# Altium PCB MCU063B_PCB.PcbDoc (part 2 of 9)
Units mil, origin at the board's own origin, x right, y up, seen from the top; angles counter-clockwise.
Board outline 4165.01 x 2371.03 mil, 10 copper layers (Top Layer, Internal Plane 2, Signal Layer 3, Signal Layer 4, Internal Plane 5, Internal Plane 6, Signal Layer 7, Signal Layer 8, Internal Plane 9, Bottom), stack 59.9 mil thick; 440 components, 394 nets, 1760 pads, 1251 vias.

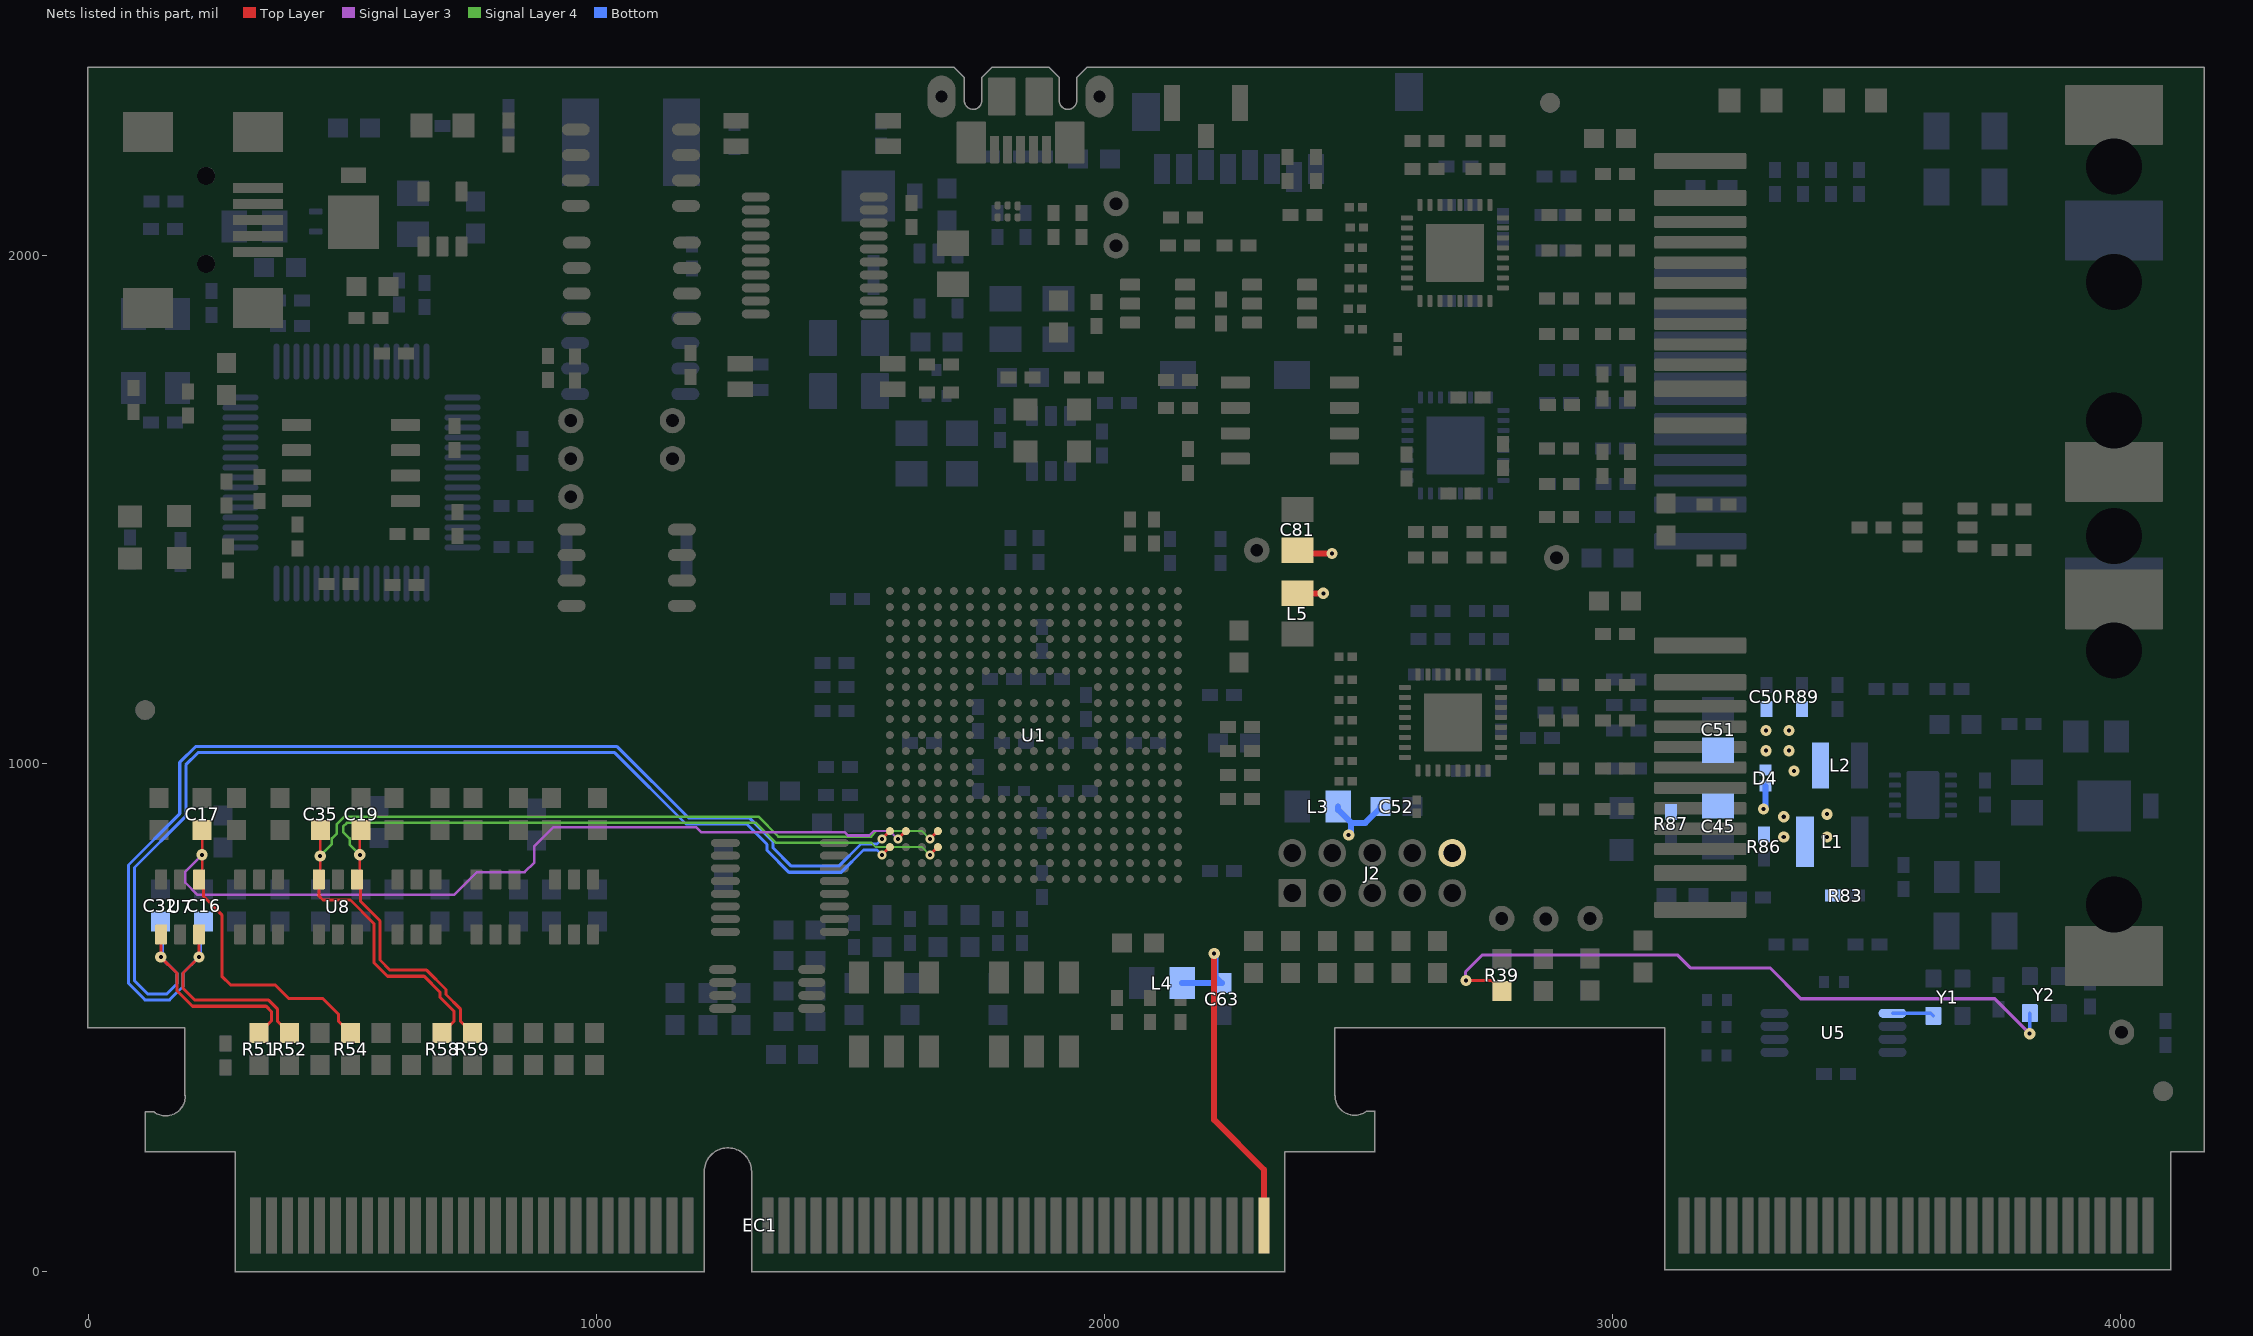
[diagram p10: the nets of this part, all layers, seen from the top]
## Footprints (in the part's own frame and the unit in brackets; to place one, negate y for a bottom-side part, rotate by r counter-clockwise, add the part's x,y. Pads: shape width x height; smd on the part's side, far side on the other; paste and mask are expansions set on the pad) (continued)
D0008B_N [mil] "SOIC, 8-Leads, Body 4.9x3.9mm, Pitch 1.27mm, IPC Medium Density"
  oval 55x23.62 smd: 1(-108.5,75) 2(-108.5,25) 3(-108.5,-25) 4(-108.5,-75) 5(108.5,-75) 6(108.5,-25) 7(108.5,25) 8(108.5,75)
  silkscreen extent -130,-98 35,98, body extent -118,-96 118,96, height 64
DBQ0016A_N [mm] "SOP, 16-Leads, Body 4.9x3.9mm, Pitch 0.635mm, IPC Medium Density"
  oval 1.45x0.4 smd: 1(-2.725,2.222) 2(-2.725,1.587) 3(-2.725,0.953) 4(-2.725,0.318) 5(-2.725,-0.318) 6(-2.725,-0.953) 7(-2.725,-1.587) 8(-2.725,-2.222) 9(2.725,-2.222) 10(2.725,-1.587) 11(2.725,-0.953) 12(2.725,-0.318) 13(2.725,0.318) 14(2.725,0.953) 15(2.725,1.587) 16(2.725,2.222)
  silkscreen extent -3.35,-2.5 1.1,2.68, body extent -3.01,-2.45 3.01,2.45, height 1.63
DBV0005A_N [mm] "SOT23, 5-Leads, Body 2.9x1.6mm, Pitch 0.95mm, Lead Span 2.8mm, IPC Medium Density"
  rrect17% 1x0.6 smd: 1(-1.375,0.95) 2(-1.375,0) 3(-1.375,-0.95) 4(1.375,-0.95) 5(1.375,0.95)
  silkscreen extent -0.25,-1.55 0.25,1.55, body extent -1.42,-1.46 1.42,1.46, height 1.09
DBV0006A_N [mm] "SOT23, 6-Leads, Body 2.9x1.6mm, Pitch 0.95mm, Lead Span 2.8mm, IPC Medium Density"
  rrect17% 1x0.6 smd: 1(-1.375,0.95) 2(-1.375,0) 3(-1.375,-0.95) 4(1.375,-0.95) 5(1.375,0) 6(1.375,0.95)
  silkscreen extent -1.68,-1.55 0.5,1.55, body extent -1.42,-1.46 1.42,1.46, height 1.12
DDC0006A_N [mm]
  rrect17% 1x0.6 smd: 1(-1.375,0.95) 2(-1.375,0) 3(-1.375,-0.95) 4(1.375,-0.95) 5(1.375,0) 6(1.375,0.95)
  silkscreen extent -1.75,-1.52 0.7,1.53, body extent -1.43,-1.48 1.43,1.49, height 0.92
DGK0008A_N [mm] "TSOP, 8-Leads, Body 3x3mm, Pitch 0.65mm, IPC Medium Density"
  oval 1.35x0.45 smd: 1(-2.225,0.975) 2(-2.225,0.325) 3(-2.225,-0.325) 4(-2.225,-0.975) 5(2.225,-0.975) 6(2.225,-0.325) 7(2.225,0.325) 8(2.225,0.975)
  silkscreen extent -2.75,-1.55 0.95,1.55, body extent -2.45,-1.5 2.45,1.5, height 0.96
DRC0010J [mm] "VSON-10"
  rrect42% 0.6x0.24 smd: 1(-1.4,1) 2(-1.4,0.5) 3(-1.4,0) 4(-1.4,-0.5) 5(-1.4,-1) 6(1.4,-1) 7(1.4,-0.5) 8(1.4,0) 9(1.4,0.5) 10(1.4,1)
  rrect12% 1.65x2.4 smd paste-1 mask-2: 11(0,0)
  Top Layer region: -0.375,-1.65 -0.375,-1.2 -0.775,-1.2 -0.794,-1.196 -0.81,-1.185 -0.821,-1.169 -0.825,-1.15 -0.825,-1.15 -0.825,1.15 -0.821,1.169 -0.81,1.185 -0.794,1.196 -0.775,1.2 -0.775,1.2 -0.375,1.2 -0.375,1.65 -0.371,1.669 -0.36,1.685 -0.344,1.696 -0.325,1.7 -0.325,1.7 -0.325,1.7 -0.175,1.7 -0.175,1.7 -0.156,1.696 -0.14,1.685 -0.129,1.669 -0.125,1.65 -0.125,1.65 -0.125,1.2 0.125,1.2 0.125,1.65 0.129,1.669 0.14,1.685 0.156,1.696 0.175,1.7 0.175,1.7 0.175,1.7 0.325,1.7 0.325,1.7 0.344,1.696 0.36,1.685 0.371,1.669 0.375,1.65 0.375,1.65 0.375,1.2 0.775,1.2 0.794,1.196 0.81,1.185 0.821,1.169 0.825,1.15 0.825,1.15 0.825,-1.15 0.821,-1.169 0.81,-1.185 0.794,-1.196 0.775,-1.2 0.775,-1.2 0.375,-1.2 0.375,-1.65 0.371,-1.669 0.36,-1.685 0.344,-1.696 0.325,-1.7 0.325,-1.7 0.175,-1.7 0.156,-1.696 0.14,-1.685 0.129,-1.669 0.125,-1.65 0.125,-1.65 0.125,-1.2 -0.125,-1.2 -0.125,-1.65 -0.129,-1.669 -0.14,-1.685 -0.156,-1.696 -0.175,-1.7 -0.175,-1.7 -0.325,-1.7 -0.344,-1.696 -0.36,-1.685 -0.371,-1.669 -0.375,-1.65
  body extent -1.5,-1.5 1.5,1.5, height 1
DRL0005A [mm] "SOTFL, 5-Flat Leads, Body 1.2x1.6x0.6mm, Pitch 0.5mm, TI recommended"
  rrect33% 0.67x0.3 smd: 1(-0.74,0.5) 2(-0.74,0) 3(-0.74,-0.5) 4(0.74,-0.5) 5(0.74,0.5)
  silkscreen extent -0.9,-0.95 0.5,0.95, body extent -0.85,-0.85 0.85,0.85, height 0.62
DRY0006A [mm] "USON-6"
  rrect67% 0.45x0.3 smd paste-0.05 mask-0.05: 1(-0.275,0.5)
  rrect67% 0.4x0.3 smd paste-0.05 mask-0.05: 2(-0.3,0) 3(-0.3,-0.5) 4(0.3,-0.5) 5(0.3,0) 6(0.3,0.5)
  body extent -0.5,-0.72 0.5,0.73, height 0.58
ECS_ECS-2520S [mm] "SMD, 4-Leads, Body 2x2.5mm"
  rrect12% 0.8x0.9 smd: 1(-0.725,0.925) 2(-0.725,-0.925) 3(0.725,-0.925) 4(0.725,0.925)
  silkscreen extent -1.7,0.9 -1.5,1.1, body extent -1.05,-1.3 1.05,1.3, height 1
ECS_ECX-53B [mm] "SMD, 4-Leads, Body 5x3.2mm"
  rect 1.25x1.6 smd: 1(-1.1,1.85) 2(-1.1,-1.85) 3(1.1,-1.85) 4(1.1,1.85)
  silkscreen extent -2.05,-2.7 1.83,2.73, body extent -1.7,-2.6 1.7,2.6, height 0.86
EtherCAT_label [mil] "ETHERCAT_LABEL"
FCC_disclaimer [mil]
Fiducial10-20 [mm]
  round 1 smd mask+0.5: 1(0,0)
  Top Layer keep-out circle w1.178: c0,0 r0.5
FP-TMM-105-01-T-D_HDR10-MFG [mm]
  rrect7% 1.39x1.39 hole 0.89 paste-1000 mask+0: 1(-4,-1)
  round 1.39 hole 0.89 paste-1000 mask+0: 2(-4,1) 3(-2,-1) 4(-2,1) 5(0,-1) 6(0,1) 7(2,-1) 8(2,1) 9(4,-1) 10(4,1)
  body extent -5.1,-2.13 5.1,2.13, height 0.25
Label_650x200 [mil] "Thermal Transfer Label"
  round 1 on Mech13: 0(0,0)
  silkscreen extent -325,-100 325,100, body extent -325,-100 325,100, height 1
LQFP64_N [mm] "Thin QFP, 64-Leads, Body 10x10mm, Pitch 0.5mm, IPC Medium Density"
  oval 1.8x0.3 smd: 1(-5.55,3.75) 2(-5.55,3.25) 3(-5.55,2.75) 4(-5.55,2.25) 5(-5.55,1.75) 6(-5.55,1.25) 7(-5.55,0.75) 8(-5.55,0.25) 9(-5.55,-0.25) 10(-5.55,-0.75) 11(-5.55,-1.25) 12(-5.55,-1.75) 13(-5.55,-2.25) 14(-5.55,-2.75) 15(-5.55,-3.25) 16(-5.55,-3.75) 33(5.55,-3.75) 34(5.55,-3.25) 35(5.55,-2.75) 36(5.55,-2.25) 37(5.55,-1.75) 38(5.55,-1.25) 39(5.55,-0.75) 40(5.55,-0.25) 41(5.55,0.25) 42(5.55,0.75) 43(5.55,1.25) 44(5.55,1.75) 45(5.55,2.25) 46(5.55,2.75) 47(5.55,3.25) 48(5.55,3.75)
  oval 0.3x1.8 smd: 17(-3.75,-5.55) 18(-3.25,-5.55) 19(-2.75,-5.55) 20(-2.25,-5.55) 21(-1.75,-5.55) 22(-1.25,-5.55) 23(-0.75,-5.55) 24(-0.25,-5.55) 25(0.25,-5.55) 26(0.75,-5.55) 27(1.25,-5.55) 28(1.75,-5.55) 29(2.25,-5.55) 30(2.75,-5.55) 31(3.25,-5.55) 32(3.75,-5.55) 49(3.75,5.55) 50(3.25,5.55) 51(2.75,5.55) 52(2.25,5.55) 53(1.75,5.55) 54(1.25,5.55) 55(0.75,5.55) 56(0.25,5.55) 57(-0.25,5.55) 58(-0.75,5.55) 59(-1.25,5.55) 60(-1.75,5.55) 61(-2.25,5.55) 62(-2.75,5.55) 63(-3.25,5.55) 64(-3.75,5.55)
  silkscreen extent -5.67,-4.25 4.25,4.57, body extent -5,-5 5,5, height 1.6
Molex_1051640001 [mm] "Receptacle, USB 2.0, Micro B, 5 Pos, 0.65mm Pitch, R/A, SMT"
  rrect22% 0.45x1.38 smd: 1(1.3,4.11) 2(0.65,4.11) 3(0,4.11) 4(-0.65,4.11) 5(-1.3,4.11)
  rrect7% 1.475x2.1 smd: 6(-2.462,3.75) 11(2.462,3.75)
  rrect100% 1.4x2.1 hole 0.6 slot 1.3 at 90 deg: 7(-3.95,1.45) 10(3.95,1.45)
  rrect7% 1.375x1.9 smd: 8(-0.937,1.45) 9(0.937,1.45)
  silkscreen extent 1.2,5.1 1.4,5.4, body extent -4.1,-0.7 4.1,4.47, height 2.45
PFL3215 [mm] "Coilcraft"
  rect 0.89x2.54 smd: 1(-1.37,0) 2(1.37,0)
  body extent -1.22,-1.14 1.22,1.14, height 1.5
POWERMITE [mil] "On Semi recommended land pattern, 457-04.pdf Rev 04E dated 2008-11-26"
  rect 105x100 smd: 1(-46,0)
  rect 30x50 smd: 2(46,0)
  silkscreen extent -124,-63 61,63, body extent -94,-40 59,40, height 45
PW0008A_N [mm] "TSOP, 8-Leads, Body 3x4.4mm, Pitch 0.65mm, IPC Medium Density"
  oval 1.4x0.45 smd: 1(-2.95,0.975) 2(-2.95,0.325) 3(-2.95,-0.325) 4(-2.95,-0.975) 5(2.95,-0.975) 6(2.95,-0.325) 7(2.95,0.325) 8(2.95,0.975)
  silkscreen extent -3.4,-1.55 1.85,1.55, body extent -3.21,-1.5 3.21,1.5, height 1.2
PW0020A_N [mm] "TSOP, 20-Leads, Body 6.5x4.4mm, Pitch 0.65mm, IPC Medium Density"
  oval 1.4x0.45 smd: 1(-2.95,2.925) 2(-2.95,2.275) 3(-2.95,1.625) 4(-2.95,0.975) 5(-2.95,0.325) 6(-2.95,-0.325) 7(-2.95,-0.975) 8(-2.95,-1.625) 9(-2.95,-2.275) 10(-2.95,-2.925) 11(2.95,-2.925) 12(2.95,-2.275) 13(2.95,-1.625) 14(2.95,-0.975) 15(2.95,-0.325) 16(2.95,0.325) 17(2.95,0.975) 18(2.95,1.625) 19(2.95,2.275) 20(2.95,2.925)
  Top Overlay keep-out lines w0.2: -1.85,-3.3 1.85,-3.3
  silkscreen extent -3.5,-3.3 1.85,3.4, body extent -3.21,-3.25 3.21,3.25, height 1
RHB0032B#1 [mm] "QFN, 32-Leads, Body 5x5mm, Pitch 0.5mm, Thermal Pad 2.9x2.9mm"
  rrect40% 0.6x0.25 smd: 1(-2.4,1.75) 2(-2.4,1.25) 3(-2.4,0.75) 4(-2.4,0.25) 5(-2.4,-0.25) 6(-2.4,-0.75) 7(-2.4,-1.25) 8(-2.4,-1.75) 17(2.4,-1.75) 18(2.4,-1.25) 19(2.4,-0.75) 20(2.4,-0.25) 21(2.4,0.25) 22(2.4,0.75) 23(2.4,1.25) 24(2.4,1.75)
  rrect40% 0.25x0.6 smd: 9(-1.75,-2.4) 10(-1.25,-2.4) 11(-0.75,-2.4) 12(-0.25,-2.4) 13(0.25,-2.4) 14(0.75,-2.4) 15(1.25,-2.4) 16(1.75,-2.4) 25(1.75,2.4) 26(1.25,2.4) 27(0.75,2.4) 28(0.25,2.4) 29(-0.25,2.4) 30(-0.75,2.4) 31(-1.25,2.4) 32(-1.75,2.4)
  rrect8% 1.27x1.27 on Bottom Paste: 33(-0.735,-0.735) 33(-0.735,0.735) 33(0.735,-0.735) 33(0.735,0.735)
  rrect3% 2.9x2.9 smd paste-1.725: 33(0,0)
  silkscreen extent -2.72,-2.73 2.72,2.73, body extent -2.57,-2.57 2.58,2.58, height 1.01
RHB0032B#2 [mm] "QFN, 32-Leads, Body 5x5mm, Pitch 0.5mm, Thermal Pad 2.9x2.9mm"
  rrect40% 0.6x0.25 smd: 1(-2.4,1.75) 2(-2.4,1.25) 3(-2.4,0.75) 4(-2.4,0.25) 5(-2.4,-0.25) 6(-2.4,-0.75) 7(-2.4,-1.25) 8(-2.4,-1.75) 17(2.4,-1.75) 18(2.4,-1.25) 19(2.4,-0.75) 20(2.4,-0.25) 21(2.4,0.25) 22(2.4,0.75) 23(2.4,1.25) 24(2.4,1.75)
  rrect40% 0.25x0.6 smd: 9(-1.75,-2.4) 10(-1.25,-2.4) 11(-0.75,-2.4) 12(-0.25,-2.4) 13(0.25,-2.4) 14(0.75,-2.4) 15(1.25,-2.4) 16(1.75,-2.4) 25(1.75,2.4) 26(1.25,2.4) 27(0.75,2.4) 28(0.25,2.4) 29(-0.25,2.4) 30(-0.75,2.4) 31(-1.25,2.4) 32(-1.75,2.4)
  rrect8% 1.27x1.27 on Top Paste: 33(-0.735,-0.735) 33(-0.735,0.735) 33(0.735,-0.735) 33(0.735,0.735)
  rrect3% 2.9x2.9 smd paste-1.725: 33(0,0)
  silkscreen extent -2.72,-2.73 2.72,2.73, body extent -2.57,-2.57 2.58,2.58, height 1.01
SOD-882L [mm] "Central Semiconductor"
  rect 0.55x0.6 smd: 1(-0.4,0)
  rect 0.55x0.6 smd paste-0.05: 2(0.4,0)
  silkscreen extent -1.1,-0.35 -0.87,0.35, body extent -0.52,-0.32 0.52,0.32, height 0.41
SOIC-8 [mm] "duplicate of SO-8.  SOIC, 8-Leads, Body 5.0x4.0mm (max), Pitch 1.27mm, IPC Medium Density"
  rrect17% 1.45x0.6 smd: 1(-2.725,1.905) 2(-2.725,0.635) 3(-2.725,-0.635) 4(-2.725,-1.905) 5(2.725,-1.905) 6(2.725,-0.635) 7(2.725,0.635) 8(2.725,1.905)
  silkscreen extent -3.5,-2.5 0.9,2.5, body extent -3,-2.45 3,2.45, height 1.63
SOT-416 [mm] "NXP recommended footprint."
  rect 0.6x0.5 smd: 1(-0.65,0.5) 2(-0.65,-0.5) 3(0.65,0)
  silkscreen extent -0.13,-0.9 0.5,0.9, body extent -0.8,-0.9 0.8,0.9, height 0.82
SW_218-2LP [mm] "SMD, 4-Leads, Body 3.71x5.8mm, Pitch 1.27mm"
  rect 1.27x0.76 smd: 1(-3.81,0.635) 2(-3.81,-0.635) 3(3.81,-0.635) 4(3.81,0.635)
  silkscreen extent -2.9,-1.86 2.9,2.09, body extent -4.22,-1.86 4.22,1.85, height 2.62
SW_B3U-1100P [mm] "SMD, 3-Leads, Body 3x2.5mm"
  rect 0.8x1.8 smd: 1(-1.7,0) 2(1.7,0)
  rect 0.8x1.2 smd: 3(0,1.65)
  silkscreen extent -2.83,-1.25 1.5,1.25, body extent -2,-1.25 2,1.9, height 1.6
SW_CAS-D20TA [mm] "SMD, 6-Leads, Body 5.4x3.9mm, Pitch 1.75mm"
  rect 1.6x1 smd: 1(-1.85,1.75) 2(-1.85,0) 3(-1.85,-1.75) 4(1.85,1.75) 5(1.85,0) 6(1.85,-1.75)
  silkscreen extent -1.95,-2.7 1.95,2.9, body extent -2.1,-2.7 2.1,2.7, height 2.5
TI_Stacked_Overlay_Small [mil]
  silkscreen extent -418,-98 418,98
TP_50MIL-25MILHOLE [mil]
  round 50 hole 25: 1(0,0)
WE-MAIA_2510 [mm] "WURTH"
  rect 0.85x2.3 smd: 1(-0.975,0) 2(0.975,0)
  silkscreen extent -0.3,-1.25 0.3,1.25, body extent -1.35,-1.1 1.35,1.1, height 1
WEEE_Minimum [mil] "WEEElie bin"
  silkscreen extent -95,-172 99,104
WL-SMCW_Blue_0805 [mm] "SMD, 2-Leads, Body 2x1.25mm"
  rect 1.1x1.2 smd: 1(-1.05,0) 2(1.05,0)
  silkscreen extent -2.4,-1.1 1.5,1.1, body extent -1,-0.62 1,0.63, height 0.7
WL-SMCW_Green_0805 [mm] "SMD, 2-Leads, Body 2x1.25mm"
  rect 1.1x1.2 smd: 1(-1.05,0) 2(1.05,0)
  silkscreen extent -2.4,-1.1 1.5,1.1, body extent -1,-0.62 1,0.63, height 0.7
WL-SMCW_RED_0805 [mm] "SMD, 2-Leads, Body 1.6x0.8mm"
  rect 1.1x1.2 smd: 1(-1.05,0) 2(1.05,0)
  silkscreen extent -2.4,-1.1 1.5,1.1, body extent -1,-0.62 1,0.63, height 0.7
Wurth_7498010210A [mm] "Connector, RJ45, 1x1, Gold, R/A, SMT"
  rrect12% 4.6x0.81 smd: 1(-20.69,6.61) 2(-20.69,4.77) 11(-20.69,-4.77) 12(-20.69,-6.61)
  rrect16% 4.6x0.61 smd: 3(-20.69,3.57) 4(-20.69,2.55) 5(-20.69,1.53) 6(-20.69,0.51) 7(-20.69,-0.51) 8(-20.69,-1.53) 9(-20.69,-2.55) 10(-20.69,-3.57)
  rrect3% 4.9x3 smd: 13(0,8.92) 14(0,-8.92)
  round 2.5 hole 2.8 unplated mask+0.102: ALIGN1(0,6.35) ALIGN2(0,-6.35)
  body extent -21.42,-9.65 5.43,9.65, height 15.22
Wurth_65100516121 [mm] "Connector, Receptacle, USB Mini B 2.0, 5 Position, SMT"
  rect 0.5x2.5 smd: 1(-1.6,8.5) 2(-0.8,8.5) 3(0,8.5) 4(0.8,8.5) 5(1.6,8.5)
  rect 2x2.5 smd: 6(-4.4,8.5) 7(4.4,8.5) 8(-4.4,3) 9(4.4,3)
  round 0.9 hole 0.9 unplated mask+0: ALIGN1(-2.2,5.9) ALIGN2(2.2,5.9)
  silkscreen extent -3.85,0.15 3.85,9.6, body extent -4.8,0 4.8,9.25, height 3.91
ZWT0337A [mm] "BGA, 337-Leads, Body 16x16mmx1.4mm, Pitch 0.80mm"
  round 0.4 smd: A1(-7.2,7.2) A2(-6.4,7.2) A3(-5.6,7.2) A4(-4.8,7.2) A5(-4,7.2) A6(-3.2,7.2) A7(-2.4,7.2) A8(-1.6,7.2) A9(-0.8,7.2) A10(0,7.2) A11(0.8,7.2) A12(1.6,7.2) A13(2.4,7.2) A14(3.2,7.2) A15(4,7.2) A16(4.8,7.2) A17(5.6,7.2) A18(6.4,7.2) A19(7.2,7.2) B1(-7.2,6.4) B2(-6.4,6.4) B3(-5.6,6.4) B4(-4.8,6.4) B5(-4,6.4) B6(-3.2,6.4) B7(-2.4,6.4) B8(-1.6,6.4) B9(-0.8,6.4) B10(0,6.4) B11(0.8,6.4) B12(1.6,6.4) B13(2.4,6.4) B14(3.2,6.4) B15(4,6.4) B16(4.8,6.4) B17(5.6,6.4) B18(6.4,6.4) B19(7.2,6.4) C1(-7.2,5.6) C2(-6.4,5.6) C3(-5.6,5.6) C4(-4.8,5.6) C5(-4,5.6) C6(-3.2,5.6) C7(-2.4,5.6) C8(-1.6,5.6) C9(-0.8,5.6) C10(0,5.6) C11(0.8,5.6) C12(1.6,5.6) C13(2.4,5.6) C14(3.2,5.6) C15(4,5.6) C16(4.8,5.6) C17(5.6,5.6) C18(6.4,5.6) C19(7.2,5.6) D1(-7.2,4.8) D2(-6.4,4.8) D3(-5.6,4.8) D4(-4.8,4.8) D5(-4,4.8) D6(-3.2,4.8) D7(-2.4,4.8) D8(-1.6,4.8) D9(-0.8,4.8) D10(0,4.8) D11(0.8,4.8) D12(1.6,4.8) D13(2.4,4.8) D14(3.2,4.8) D15(4,4.8) D16(4.8,4.8) D17(5.6,4.8) D18(6.4,4.8) D19(7.2,4.8) E1(-7.2,4) E2(-6.4,4) E3(-5.6,4) E4(-4.8,4) E5(-4,4) E6(-3.2,4) E7(-2.4,4) E8(-1.6,4) E9(-0.8,4) E10(0,4) E11(0.8,4) E12(1.6,4) E13(2.4,4) E14(3.2,4) E15(4,4) E16(4.8,4) E17(5.6,4) E18(6.4,4) E19(7.2,4) F1(-7.2,3.2) F2(-6.4,3.2) F3(-5.6,3.2) F4(-4.8,3.2) F5(-4,3.2) F6(-3.2,3.2) F7(-2.4,3.2) F8(-1.6,3.2) F9(-0.8,3.2) F10(0,3.2) F11(0.8,3.2) F12(1.6,3.2) F13(2.4,3.2) F14(3.2,3.2) F15(4,3.2) F16(4.8,3.2) F17(5.6,3.2) F18(6.4,3.2) F19(7.2,3.2) G1(-7.2,2.4) G2(-6.4,2.4) G3(-5.6,2.4) G4(-4.8,2.4) G5(-4,2.4) G6(-3.2,2.4) G14(3.2,2.4) G15(4,2.4) G16(4.8,2.4) G17(5.6,2.4) G18(6.4,2.4) G19(7.2,2.4) H1(-7.2,1.6) H2(-6.4,1.6) H3(-5.6,1.6) H4(-4.8,1.6) H5(-4,1.6) H6(-3.2,1.6) H8(-1.6,1.6) H9(-0.8,1.6) H10(0,1.6) H11(0.8,1.6) H12(1.6,1.6) H14(3.2,1.6) H15(4,1.6) H16(4.8,1.6) H17(5.6,1.6) H18(6.4,1.6) H19(7.2,1.6) J1(-7.2,0.8) J2(-6.4,0.8) J3(-5.6,0.8) J4(-4.8,0.8) J5(-4,0.8) J6(-3.2,0.8) J8(-1.6,0.8) J9(-0.8,0.8) J10(0,0.8) J11(0.8,0.8) J12(1.6,0.8) J14(3.2,0.8) J15(4,0.8) J16(4.8,0.8) J17(5.6,0.8) J18(6.4,0.8) J19(7.2,0.8) K1(-7.2,0) K2(-6.4,0) K3(-5.6,0) K4(-4.8,0) K5(-4,0) K6(-3.2,0) K8(-1.6,0) K9(-0.8,0) K10(0,0) K11(0.8,0) K12(1.6,0) K14(3.2,0) K15(4,0) K16(4.8,0) K17(5.6,0) K18(6.4,0) K19(7.2,0) L1(-7.2,-0.8) L2(-6.4,-0.8) L3(-5.6,-0.8) L4(-4.8,-0.8) L5(-4,-0.8) L6(-3.2,-0.8) L8(-1.6,-0.8) L9(-0.8,-0.8) L10(0,-0.8) L11(0.8,-0.8) L12(1.6,-0.8) L14(3.2,-0.8) L15(4,-0.8) L16(4.8,-0.8) L17(5.6,-0.8) L18(6.4,-0.8) L19(7.2,-0.8) M1(-7.2,-1.6) M2(-6.4,-1.6) M3(-5.6,-1.6) M4(-4.8,-1.6) M5(-4,-1.6) M6(-3.2,-1.6) M8(-1.6,-1.6) M9(-0.8,-1.6) M10(0,-1.6) M11(0.8,-1.6) M12(1.6,-1.6) M14(3.2,-1.6) M15(4,-1.6) M16(4.8,-1.6) M17(5.6,-1.6) M18(6.4,-1.6) M19(7.2,-1.6) N1(-7.2,-2.4) N2(-6.4,-2.4) N3(-5.6,-2.4) N4(-4.8,-2.4) N5(-4,-2.4) N6(-3.2,-2.4) N14(3.2,-2.4) N15(4,-2.4) N16(4.8,-2.4) N17(5.6,-2.4) N18(6.4,-2.4) N19(7.2,-2.4) P1(-7.2,-3.2) P2(-6.4,-3.2) P3(-5.6,-3.2) P4(-4.8,-3.2) P5(-4,-3.2) P6(-3.2,-3.2) P7(-2.4,-3.2) P8(-1.6,-3.2) P9(-0.8,-3.2) P10(0,-3.2) P11(0.8,-3.2) P12(1.6,-3.2) P13(2.4,-3.2) P14(3.2,-3.2) P15(4,-3.2) P16(4.8,-3.2) P17(5.6,-3.2) P18(6.4,-3.2) P19(7.2,-3.2) R1(-7.2,-4) R2(-6.4,-4) R3(-5.6,-4) R4(-4.8,-4) R5(-4,-4) R6(-3.2,-4) R7(-2.4,-4) R8(-1.6,-4) R9(-0.8,-4) R10(0,-4) R11(0.8,-4) R12(1.6,-4) R13(2.4,-4) R14(3.2,-4) R15(4,-4) R16(4.8,-4) R17(5.6,-4) R18(6.4,-4) R19(7.2,-4) T1(-7.2,-4.8) T2(-6.4,-4.8) T3(-5.6,-4.8) T4(-4.8,-4.8) T5(-4,-4.8) T6(-3.2,-4.8) T7(-2.4,-4.8) T8(-1.6,-4.8) T9(-0.8,-4.8) T10(0,-4.8) T11(0.8,-4.8) T12(1.6,-4.8) T13(2.4,-4.8) T14(3.2,-4.8) T15(4,-4.8) T16(4.8,-4.8) T17(5.6,-4.8) T18(6.4,-4.8) T19(7.2,-4.8) U1(-7.2,-5.6) U2(-6.4,-5.6) U3(-5.6,-5.6) U4(-4.8,-5.6) U5(-4,-5.6) U6(-3.2,-5.6) U7(-2.4,-5.6) U8(-1.6,-5.6) U9(-0.8,-5.6) U10(0,-5.6) U11(0.8,-5.6) U12(1.6,-5.6) U13(2.4,-5.6) U14(3.2,-5.6) U15(4,-5.6) U16(4.8,-5.6) U17(5.6,-5.6) U18(6.4,-5.6) U19(7.2,-5.6) V1(-7.2,-6.4) V2(-6.4,-6.4) V3(-5.6,-6.4) V4(-4.8,-6.4) V5(-4,-6.4) V6(-3.2,-6.4) V7(-2.4,-6.4) V8(-1.6,-6.4) V9(-0.8,-6.4) V10(0,-6.4) V11(0.8,-6.4) V12(1.6,-6.4) V13(2.4,-6.4) V14(3.2,-6.4) V15(4,-6.4) V16(4.8,-6.4) V17(5.6,-6.4) V18(6.4,-6.4) V19(7.2,-6.4) W1(-7.2,-7.2) W2(-6.4,-7.2) W3(-5.6,-7.2) W4(-4.8,-7.2) W5(-4,-7.2) W6(-3.2,-7.2) W7(-2.4,-7.2) W8(-1.6,-7.2) W9(-0.8,-7.2) W10(0,-7.2) W11(0.8,-7.2) W12(1.6,-7.2) W13(2.4,-7.2) W14(3.2,-7.2) W15(4,-7.2) W16(4.8,-7.2) W17(5.6,-7.2) W18(6.4,-7.2) W19(7.2,-7.2)
  silkscreen extent -8.15,-8.15 8.15,8.15, body extent -8,-8 8,8, height 1.34

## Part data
C1 C1:A C2 C4 C6 C6:A C7 C7:A C8:A C9:A C10:A C11:A C12:A C14:A C16:A C20:A C21:A C22:A C23:A C24:A C25:A C26:A C27:A C28:A C115 C134: library part CMP-0006343-2, "CAP, CERM, 0.1 uF, 10 V, +/- 10%, X7R, 0402", Cap_Case=0402, Manufacturer="Samsung Electro-Mechanics", TempCo=X7R, Tolerance_%=10%, Value1=Unknown, Value2=10V, ValueDisplayed=0.1uF
C2:A C3:A C5:A C13:A C15:A C83: library part CMP-0006950-5, "CAP, CERM, 4.7 uF, 6.3 V, +/- 10%, X5R, 0603", Cap_Case=0603, Manufacturer=Kemet, Supplier Part Number 1=399-3482-1-ND, TempCo=X5R, Tolerance_%=10%, Value1="0.006 ohm", Value2=6.3V, ValueDisplayed=4.7uF
C3 C5: library part CMP-0006236-2, "CAP, CERM, 0.01 uF, 50 V, +/- 5%, X7R, 0402", Cap_Case=0402, Manufacturer=Kemet, Supplier Part Number 1=399-7758-1-ND, TempCo=X7R, Tolerance_%=5%, Value1=Unknown, Value2=50V, ValueDisplayed=0.01uF
C4:A: library part CMP-0006203-2, "CAP, CERM, 0.01 uF, 10 V, +/- 10%, X7R, 0402", Cap_Case=0402, Manufacturer=AVX, Supplier Part Number 1=478-7890-1-ND, TempCo=X7R, Tolerance_%=10%, Value1=Unknown, Value2=10V, ValueDisplayed=0.01uF
C8 C9 C10 C13 C44: library part CMP-0006862-5, "CAP, CERM, 0.1 uF, 10 V, +/- 10%, X7R, 0603", Cap_Case=0603, Manufacturer=Kemet, Supplier Part Number 1=399-1095-1-ND, TempCo=X7R, Tolerance_%=10%, Value1=Unknown, Value2=10V, ValueDisplayed=0.1uF
C11 C12 C15: library part CMP-0006871-4, "CAP, CERM, 1 uF, 6.3 V, +80/-20%, Y5V, 0603", Cap_Case=0603, Manufacturer=Kemet, Supplier Part Number 1=399-3217-1-ND, TempCo=Y5V, Tolerance_%=80%, Value1=Unknown, Value2=6.3V, ValueDisplayed=1uF
C14: library part CMP-0006907-5, "CAP, CERM, 2.2 uF, 6.3 V, +/- 10%, X5R, 0603", Cap_Case=0603, Manufacturer=Kemet, Supplier Part Number 1=399-3362-1-ND, TempCo=X5R, Tolerance_%=10%, Value1=Unknown, Value2=6.3V, ValueDisplayed=2.2uF
C16 C17 C18 C19 C20 C21 C22 C23 C24 C25 C26 C27 C32 C33 C34 C35 C36 C37 C38 C39 C40 C41 C42 C43: library part CMP-0006920-4, "CAP, CERM, 330 pF, 50 V, +/- 5%, C0G/NP0, 0603", Cap_Case=0603, Manufacturer=Kemet, Supplier Part Number 1=399-1068-1-ND, TempCo=C0G/NP0, Tolerance_%=5%, Value1=Unknown, Value2=50V, ValueDisplayed=330pF
C17:A C86: library part CMP-0006319-2, "CAP, CERM, 3300 pF, 50 V, +/- 10%, X7R, AEC-Q200 Grade 1, 0402", Cap_Case=0402, Manufacturer=TDK, Supplier Part Number 1=445-6891-1-ND, TempCo=X7R, Tolerance_%=10%, Value1="0.785178 ohm", Value2=50V, ValueDisplayed=3300pF
C18:A C19:A: library part CMP-0750098-1, "CAP, CERM, 27 pF, 50 V,+/- 5%, C0G/NP0, 0402", Cap_Case=0402, Manufacturer=Kemet, TempCo=C0G/NP0, Tolerance_%=5%, Value2=50V, ValueDisplayed=27pF
C28 C29 C30 C31: library part CMP-0007324-5, "CAP, CERM, 22 uF, 10 V, +/- 20%, X5R, 0603", Cap_Case=0603, Manufacturer=MuRata, Supplier Part Number 1=490-10476-1-ND, TempCo=X5R, Tolerance_%=20%, Value1=Unknown, Value2=10V, ValueDisplayed=22uF
C29:A: library part CMP-0082066-1, "CAP, CERM, 10 pF, 3000 V,+/- 5%, C0G/NP0, AEC-Q200 Grade 1, 1812", Cap_Case=1812, Manufacturer=Kemet, Supplier Part Number 1=399-7113-1-ND, TempCo=C0G/NP0, Tolerance_%=5%, Value2=3000V, ValueDisplayed=10pF
C45 C47 C51: library part CMP-0008294-2, "CAP, CERM, 22 uF, 16 V, +/- 20%, X5R, 0805", Cap_Case=0805, Manufacturer=MuRata, Supplier Part Number 1=490-10747-1-ND, TempCo=X5R, Tolerance_%=20%, Value1=Unknown, Value2=16V, ValueDisplayed=22uF
C46 C48 C49 C54 C55 C56 C57 C58 C59 C60 C61 C62 C65 C66 C67 C68 C69 C70 C71 C72 C73 C74 C75 C76 C77 C78 C79 C80: library part CMP-0006201-2, "CAP, CERM, 0.1 uF, 16 V, +/- 10%, X7R, 0402", Cap_Case=0402, Manufacturer=AVX, Supplier Part Number 1=478-7888-1-ND, TempCo=X7R, Tolerance_%=10%, Value1=Unknown, Value2=16V, ValueDisplayed=0.1uF
C50: library part CMP-0006213-2, "CAP, CERM, 33 pF, 25 V, +/- 5%, C0G/NP0, 0402", Cap_Case=0402, Manufacturer="Wurth Elektronik", Supplier Part Number 1=710-885012005043, TempCo=C0G/NP0, Tolerance_%=5%, Value1=Unknown, Value2=25V, ValueDisplayed=33pF
C52 C53 C63 C64: library part CMP-0006906-5, "CAP, CERM, 2.2 uF, 10 V, +/- 10%, X5R, 0603", Cap_Case=0603, Manufacturer=Kemet, Supplier Part Number 1=399-4911-1-ND, TempCo=X5R, Tolerance_%=10%, Value1=Unknown, Value2=10V, ValueDisplayed=2.2uF
C81: library part CMP-0007732-2, "CAP, CERM, 10 uF, 10 V, +/- 10%, X5R, 0805", Cap_Case=0805, Manufacturer=Kemet, Supplier Part Number 1=399-4925-1-ND, TempCo=X5R, Tolerance_%=10%, Value1="0.003 ohm", Value2=10V, ValueDisplayed=10uF
C82: library part CMP-0007318-5, "CAP, CERM, 10 uF, 10 V, +/- 20%, X5R, 0603", Cap_Case=0603, Manufacturer=MuRata, TempCo=X5R, Tolerance_%=20%, Value1=Unknown, Value2=10V, ValueDisplayed=10uF
C84: library part CMP-0011440-2, "CAP, TA, 0.1 uF, 35 V, +/- 10%, 20 ohm, SMD", Cap_Case=A, Manufacturer=Vishay-Sprague, Supplier Part Number 1=718-1109-1-ND, Tolerance_%=10%, Value1="20 ohm", Value2=35V, ValueDisplayed=0.1uF
C85: library part CMP-0081926-1, "CAP, TA, 68 µF, 10 V, +/- 20%, 1.5 ohm, SMD", Cap_Case=3216-18, Manufacturer=AVX, Supplier Part Number 1=478-4925-1-ND, Tolerance_%=20%, Value1="1.5 ohm", Value2=10V, ValueDisplayed=68µF
C87 C94 C104 C111 C122 C129: library part CMP-0006340-2, "CAP, CERM, 10 uF, 6.3 V, +/- 20%, X5R, 0402", Cap_Case=0402, Manufacturer="Samsung Electro-Mechanics", TempCo=X5R, Tolerance_%=20%, Value1=Unknown, Value2=6.3V, ValueDisplayed=10uF
C88 C93 C96 C97 C99 C102 C105 C110 C113 C114 C117 C120 C123 C128 C131 C132 C135 C138: library part CMP-0006347-2, "CAP, CERM, 1 uF, 16 V, +/- 10%, X5R, 0402", Cap_Case=0402, Manufacturer="Taiyo Yuden", Supplier Part Number 1=587-3709-2-ND, TempCo=X5R, Tolerance_%=10%, Value1=Unknown, Value2=16V, ValueDisplayed=1uF
C89 C92 C95 C98 C100 C101 C106 C109 C112 C116 C118 C119 C124 C127 C130 C133 C136 C137: library part CMP-0064930-2, "CAP, CERM, 0.1 uF, 10 V,+/- 10%, X5R, 0402", Cap_Case=0402, Manufacturer="Taiyo Yuden", Supplier Part Number 1=587-1227-1-ND, TempCo=X5R, Tolerance_%=10%, Value1=Unknown, Value2=10V, ValueDisplayed=0.1uF
C90 C91 C107 C108 C125 C126: library part CMP-0006227-2, "CAP, CERM, 0.01 uF, 16 V, +/- 10%, X7R, 0402", Cap_Case=0402, Manufacturer="Wurth Elektronik", Supplier Part Number 1=710-885012205031, TempCo=X7R, Tolerance_%=10%, Value1=Unknown, Value2=16V, ValueDisplayed=0.01uF
C103 C121 C139: library part CMP-0008501-2, "CAP, CERM, 4700 pF, 100 V, +/- 10%, X7R, 1206", Cap_Case=1206, Manufacturer=AVX, Supplier Part Number 1=478-1521-1-ND, TempCo=X7R, Tolerance_%=10%, Value1="0.178 ohm", Value2=100V, ValueDisplayed=4700pF
D1 D2 D7: library part CMP-0002951-3, "LED, Red, SMD", Color=Red, Manufacturer="Wurth Elektronik", Power_TotalModule=72mW, Value1=0.072W, Value2=1.9V
D1:A D3 D6: library part CMP-0028747-2, "Diode, Schottky, 10 V, 1 A, AEC-Q101, POWERMITE", Manufacturer="ON Semiconductor", Value1=1A, Value2=0.53V
D2:A D5 D8: library part CMP-0002960-2, "LED, Bright Green, SMD", Color="Bright Green", Manufacturer="Wurth Elektronik", Power_TotalModule=72mW, Supplier Part Number 1=732-4986-1-ND, Value1=0.072W, Value2=2V
D3:A D4:A: library part CMP-0002959-3, "LED, Blue, SMD", Color=Blue, Manufacturer="Wurth Elektronik", Power_TotalModule=105mW, Value1=0.105W, Value2=3.2V
D4: library part CMP-0028751-2, "Diode, Schottky, 20 V, 0.5 A, 1.0x0.35x0.6mm", Manufacturer="Central Semiconductor", Value1=0.5A, Value2=0.5V
EC1: library part CMP-0003813-2, "C2000 controlCARD-120HSEC Edge Connector for Samtec HSEC8-160-01-L-DV-A-BL", Manufacturer=Any
EC2: library part CMP-0081961-1, "C2000 controlCARD-180HSEC (60-pin addon) Edge connector for Samtec HSEC8-130-01-L-DV-A", Manufacturer=Any
FID1 FID2 FID3 FID4 FID5 FID6: library part CMP-0077181-1, "Fiducial mark.  There is nothing to buy or mount.", Manufacturer=N/A
J1: library part CMP-0075148-2, "Connector, Micro SD, R/A, SMD", Manufacturer=3M, Supplier Part Number 1=3M5607CT-ND
J1:A: library part CMP-0054809-1, "Connector, Receptacle, USB Mini B 2.0, SMT", Color=Black, Current_A=1A, Manufacturer="Wurth Elektronik", Supplier Part Number 1=732-2109-1-ND, Voltage_V=30V
J2: library part CMP-0086568-1, "Board-To-Board Connector, TMM Series, 10 Contacts, Header, 2 mm, Through Hole, 2 Rows", Current_A=3.2A, Manufacturer=Samtec, Voltage_V=281V
J3: library part CMP-0055311-1, "Receptacle, USB 2.0, Micro B, 5 Position, R/A, SMT", Color=Black, Current_A=1.8A, Manufacturer=Molex, Supplier Part Number 1=WM11263CT-ND, Voltage_V=30V
J4 J5 J6: library part CMP-0086350-1, "Connector, RJ45, 1x1, Gold, R/A, SMT", Manufacturer="Wurth Elektronik"
L1: library part CMP-0060725-1, "Inductor, Shielded, Composite, 2.2 uH, 1.1 A, 0.114 ohm, SMD", Manufacturer=Coilcraft, Supplier Part Number 1=994-PFL3215-222MEB, Value1="0.114 ohm", Value2=1.1A, ValueDisplayed=2.2uH
L1:A L2:A: library part CMP-0003398-1, "Ferrite Bead, 600 ohm @ 100 MHz, 0.5 A, 0805", Manufacturer="Laird-Signal Integrity Products", Supplier Part Number 1=240-2399-1-ND, Value1="0.3 ohm", Value2=0.5A, ValueDisplayed="600 ohm"
L2: library part CMP-0064350-1, "Inductor, Shielded, Powdered Iron, 3.3 uH, 1.25 A, 0.264 ohm, AEC-Q200 Grade 1, SMD", Manufacturer="Wurth Elektronik", Supplier Part Number 1=732-6915-1-ND, Value1="0.264 ohm", Value2=1.25A, ValueDisplayed=3.3uH
L3 L4: library part CMP-0003306-1, "Ferrite Bead, 60 ohm @ 100 MHz, 3 A, 0805", Manufacturer="Taiyo Yuden", Supplier Part Number 1=587-1932-1-ND, Value1="0.025 ohm", Value2=3A, ValueDisplayed="60 ohm"
L5: library part CMP-0003363-1, "Ferrite Bead, 220 ohm @ 100 MHz, 2 A, 0805", Manufacturer=MuRata, Supplier Part Number 1=490-1054-1-ND, Value1="0.045 ohm", Value2=2A, ValueDisplayed="220 ohm"
LBL1: library part CMP-0003625-1, "Thermal Transfer Printable Labels, 0.650\" W x 0.200\" H - 10,000 per roll", Manufacturer=Brady, Supplier Part Number 1=97C5133
Logo1: library part CMP-0074844-1
Logo2: library part CMP-0074838-1, "Texas Instrument Corporate Signature"
Logo3: library part CMP-0074847-1, "FCC_disclaimer"
Logo4: library part CMP-0074769-1
Logo5: library part CMP-0084011-3, "EtherCAT logo"
Q1: library part CMP-0081965-1, "MOSFET, N-CH, 30 V, 0.154 A, AEC-Q101, SOT-416", Alternate Manufacturer=None, Manufacturer="ON Semiconductor", Supplier Part Number 1=NTA7002NT1GOSCT-ND, Value1="7 ohm", Value2="? nC"
R1 R2 R120 R121: library part CMP-0026938-5, "RES, 4.7 k, 5%, 0.063 W, AEC-Q200 Grade 0, 0402", Manufacturer=Vishay-Dale, Power_W=63mW, Supplier Part Number 1=541-4.7KJCT-ND, TempCo="200 ppm/C", Tolerance_%=5%, Value2=0.063W, Value_Code=4k70, ValueDisplayed=4.7k
R1:A R9 R10 R87 R142: library part CMP-0026962-3, "RES, 680, 5%, 0.063 W, AEC-Q200 Grade 0, 0402", Manufacturer=Vishay-Dale, Power_W=63mW, Supplier Part Number 1=541-680JCT-ND, TempCo="200 ppm/C", Tolerance_%=5%, Value2=0.063W, Value_Code=680R, ValueDisplayed=680
R2:A R4:A R8:A R15:A R90: library part CMP-0026825-5, "RES, 10 k, 5%, 0.063 W, AEC-Q200 Grade 0, 0402", Manufacturer=Vishay-Dale, Power_W=63mW, Supplier Part Number 1=541-10KJCT-ND, TempCo="200 ppm/C", Tolerance_%=5%, Value2=0.063W, Value_Code=10k0, ValueDisplayed=10k
R3 R4 R5 R6 R7 R8 R15: library part CMP-0026916-3, "RES, 39, 5%, 0.063 W, AEC-Q200 Grade 0, 0402", Manufacturer=Vishay-Dale, Power_W=63mW, Supplier Part Number 1=541-39JCT-ND, TempCo="200 ppm/C", Tolerance_%=5%, Value2=0.063W, Value_Code=39R0, ValueDisplayed=39
R3:A R11:A R12:A R14:A R83 R95 R96 R102 R106: library part CMP-0026822-3, "RES, 0, 5%, 0.063 W, AEC-Q200 Grade 0, 0402", Manufacturer=Vishay-Dale, Power_W=63mW, Supplier Part Number 1=541-0.0JCT-ND, TempCo="200 ppm/C", Tolerance_%=5%, Value2=0.063W, Value_Code=0000, ValueDisplayed=0
R5:A R6:A R7:A R10:A: library part CMP-0026852-3, "RES, 1.0 k, 5%, 0.063 W, AEC-Q200 Grade 0, 0402", Manufacturer=Vishay-Dale, Power_W=63mW, Supplier Part Number 1=541-1.0KJCT-ND, TempCo="200 ppm/C", Tolerance_%=5%, Value2=0.063W, Value_Code=1k00, ValueDisplayed=1.0k
R9:A R16 R17 R20 R26 R36 R37 R112 R115 R127 R137 R152 R160: library part CMP-0026890-5, "RES, 2.2 k, 5%, 0.063 W, AEC-Q200 Grade 0, 0402", Manufacturer=Vishay-Dale, Power_W=63mW, Supplier Part Number 1=541-2.2KJCT-ND, TempCo="200 ppm/C", Tolerance_%=5%, Value2=0.063W, Value_Code=2k20, ValueDisplayed=2.2k
R11 R12 R143 R144: library part CMP-0026863-2, "RES, 1.5 M, 5%, 0.063 W, AEC-Q200 Grade 0, 0402", Manufacturer=Vishay-Dale, Power_W=63mW, Supplier Part Number 1=541-1.5MJCT-ND, TempCo="200 ppm/C", Tolerance_%=5%, Value2=0.063W, Value_Code=1M50, ValueDisplayed=1.5M
R13 R14 R18 R19 R113 R128 R151: library part CMP-0078669-1, "RES, 10.0 k, 1%, 0.063 W, 0402", Manufacturer="Yageo America", Power_W=63mW, Supplier Part Number 1=311-10.0KLRCT-ND, TempCo="100 ppm/C", Tolerance_%=1%, Value2=0.063W, Value_Code=10k0, ValueDisplayed=10.0k
R13:A: library part CMP-0026834-3, "RES, 12 k, 5%, 0.063 W, AEC-Q200 Grade 0, 0402", Manufacturer=Vishay-Dale, Power_W=63mW, Supplier Part Number 1=541-12KJCT-ND, TempCo="200 ppm/C", Tolerance_%=5%, Value2=0.063W, Value_Code=12k0, ValueDisplayed=12k
R21 R22 R23 R24 R25 R27 R28 R29 R30 R33 R34 R39 R43 R47 R48 R50 R51 R52 R53 R54 R55 R56 R57 R58 R59 R60 R61 R62 R63 R64 R65 R66 R67 R68 R69 R70 R71 R72 R73 R74 R75 R76 R81: library part CMP-0025697-4, "RES, 0, 5%, 0.1 W, AEC-Q200 Grade 0, 0603", Manufacturer=Vishay-Dale, Power_W=100mW, Supplier Part Number 1=541-0.0GCT-ND, TempCo="200 ppm/C", Tolerance_%=5%, Value2=0.1W, Value_Code=0000, ValueDisplayed=0
R31 R32: library part CMP-0026949-3, "RES, 56 k, 5%, 0.063 W, AEC-Q200 Grade 0, 0402", Manufacturer=Vishay-Dale, Power_W=63mW, Supplier Part Number 1=541-56KJCT-ND, TempCo="200 ppm/C", Tolerance_%=5%, Value2=0.063W, Value_Code=56k0, ValueDisplayed=56k
R35 R38 R40 R42: library part CMP-0026765-1, "RES, 10.0, 0.1%, 0.063 W, 0402", Manufacturer="TE Connectivity", Power_W=63mW, Supplier Part Number 1=A102583CT-ND, TempCo="25 ppm/C", Tolerance_%=0.1%, Value2=0.063W, Value_Code=10R0, ValueDisplayed=10.0
R41 R44 R45 R46: library part CMP-0081856-1, "RES, 0, 0%, 0.2 W, AEC-Q200 Grade 0, 0402", Manufacturer=Vishay-Dale, Power_W=200mW, Supplier Part Number 1=541-0.0YBTR-ND, Tolerance_%=0%, Value2=0.2W, Value_Code=0
R49: library part CMP-0022895-5, "RES, 1.00 k, 1%, 0.1 W, 0603", Manufacturer=Yageo, Power_W=100mW, Supplier Part Number 1=311-1.00KHRCT-ND, TempCo="100 ppm/C", Tolerance_%=1%, Value2=0.1W, Value_Code=1k00, ValueDisplayed=1.00k
R77 R78 R79 R80: library part CMP-0078660-1, "RES, 0.1, 1%, 0.25 W, 0402", Manufacturer=Panasonic, Power_W=250mW, Supplier Part Number 1=P17368CT-ND, TempCo="300 ppm/C", Tolerance_%=1%, Value2=0.25W, Value_Code=R100, ValueDisplayed=0.1
R82 R85: library part CMP-0020802-2, "RES, 0, 5%, 0.125 W, 0805", Manufacturer=Rohm, Power_W=125mW, Supplier Part Number 1=RHM0.0ARCT-ND, TempCo="400 ppm/C", Tolerance_%=5%, Value2=0.125W, Value_Code=0000, ValueDisplayed=0
R84: library part CMP-0026879-3, "RES, 22 k, 5%, 0.063 W, AEC-Q200 Grade 0, 0402", Manufacturer=Vishay-Dale, Power_W=63mW, Supplier Part Number 1=541-22KJCT-ND, TempCo="200 ppm/C", Tolerance_%=5%, Value2=0.063W, Value_Code=22k0, ValueDisplayed=22k
R86: library part CMP-0026300-2, "RES, 340 k, 1%, 0.063 W, AEC-Q200 Grade 0, 0402", Manufacturer=Vishay-Dale, Power_W=63mW, Supplier Part Number 1=541-340KLCT-ND, TempCo="100 ppm/C", Tolerance_%=1%, Value2=0.063W, Value_Code=340k
R88: library part CMP-0026676-1, "RES, 2.00 k, 1%, 0.1 W, AEC-Q200 Grade 0, 0402", Manufacturer=Panasonic, Power_W=100mW, Supplier Part Number 1=P2.00KLCT-ND, TempCo="100 ppm/C", Tolerance_%=1%, Value2=0.1W, Value_Code=2k00, ValueDisplayed=2.00k
R89: library part CMP-0026160-2, "RES, 205 k, 1%, 0.063 W, AEC-Q200 Grade 0, 0402", Manufacturer=Vishay-Dale, Power_W=63mW, Supplier Part Number 1=541-205KLCT-ND, TempCo="100 ppm/C", Tolerance_%=1%, Value2=0.063W, Value_Code=205k
R91: library part CMP-0025698-4, "RES, 100 k, 5%, 0.1 W, AEC-Q200 Grade 0, 0603", Manufacturer=Vishay-Dale, Power_W=100mW, Supplier Part Number 1=541-100KGCT-ND, TempCo="200 ppm/C", Tolerance_%=5%, Value2=0.1W, Value_Code=100k
R92: library part CMP-0026677-1, "RES, 200 k, 1%, 0.1 W, 0402", Manufacturer=Panasonic, Power_W=100mW, Supplier Part Number 1=P200KLCT-ND, TempCo="100 ppm/C", Tolerance_%=1%, Value2=0.1W, Value_Code=200k
R93: library part CMP-0025557-3, "RES, 75.0 k, 0.5%, 0.1 W, 0603", Manufacturer="Yageo America", Power_W=100mW, TempCo="50 ppm/C", Tolerance_%=0.5%, Value2=0.1W, Value_Code=75k0, ValueDisplayed=75.0k
R94: library part CMP-0026950-3, "RES, 56, 5%, 0.063 W, AEC-Q200 Grade 0, 0402", Manufacturer=Vishay-Dale, Power_W=63mW, Supplier Part Number 1=541-56JCT-ND, TempCo="200 ppm/C", Tolerance_%=5%, Value2=0.063W, Value_Code=56R0, ValueDisplayed=56
R97 R98 R99 R100 R101: library part CMP-0020620-3, "RES, 10 k, 5%, 0.125 W, AEC-Q200 Grade 0, 0805", Manufacturer=Panasonic, Power_W=125mW, Supplier Part Number 1=P10KACT-ND, TempCo="200 ppm/C", Tolerance_%=5%, Value2=0.125W, Value_Code=10k0, ValueDisplayed=10k
R103 R104 R105: library part CMP-0025875-3, "RES, 100 k, 5%, 0.1 W, AEC-Q200 Grade 0, 0603", Manufacturer=Panasonic, Power_W=100mW, Supplier Part Number 1=P100KGCT-ND, TempCo="200 ppm/C", Tolerance_%=5%, Value2=0.1W, Value_Code=100k
R107 R108 R110 R111 R118 R119 R125 R126 R139 R140 R149 R150: library part CMP-0026738-1, "RES, 49.9, 1%, 0.063 W, 0402", Manufacturer="Yageo America", Power_W=63mW, Supplier Part Number 1=311-49.9LRCT-ND, TempCo="100 ppm/C", Tolerance_%=1%, Value2=0.063W, Value_Code=49R9, ValueDisplayed=49.9
R109 R124 R148: library part CMP-0026413-2, "RES, 4.87 k, 1%, 0.063 W, AEC-Q200 Grade 0, 0402", Manufacturer=Vishay-Dale, Power_W=63mW, Supplier Part Number 1=541-4.87KLCT-ND, TempCo="100 ppm/C", Tolerance_%=1%, Value2=0.063W, Value_Code=4k87, ValueDisplayed=4.87k
R114 R130 R154: library part CMP-0026237-2, "RES, 2.49 k, 1%, 0.063 W, AEC-Q200 Grade 0, 0402", Manufacturer=Vishay-Dale, Power_W=63mW, Supplier Part Number 1=541-2.49KLCT-ND, TempCo="100 ppm/C", Tolerance_%=1%, Value2=0.063W, Value_Code=2k49, ValueDisplayed=2.49k
R116 R117 R129 R138 R153 R161: library part CMP-0025813-4, "RES, 470, 5%, 0.1 W, AEC-Q200 Grade 0, 0603", Manufacturer=Vishay-Dale, Power_W=100mW, Supplier Part Number 1=541-470GCT-ND, TempCo="200 ppm/C", Tolerance_%=5%, Value2=0.1W, Value_Code=470R, ValueDisplayed=470
R122 R123 R131 R132 R133 R134 R135 R136 R145 R146 R147 R155 R156 R157 R158 R159: library part CMP-0027010-2, "RES, 2.2 k, 5%, 0.05 W, 0201", Manufacturer=Vishay-Dale, Power_W=50mW, Supplier Part Number 1=541-2.2KAGCT-ND, TempCo="200 ppm/C", Tolerance_%=5%, Value2=0.05W, Value_Code=2k20, ValueDisplayed=2.2k
R141: library part CMP-0026081-3, "RES, 1.27 k, 1%, 0.063 W, AEC-Q200 Grade 0, 0402", Manufacturer=Vishay-Dale, Power_W=63mW, Supplier Part Number 1=541-1.27KLCT-ND, TempCo="100 ppm/C", Tolerance_%=1%, Value2=0.063W, Value_Code=1k27, ValueDisplayed=1.27k
S1: library part CMP-0002193-2, "Switch, SPST-NO, Off-Mom, 12 V, SMD", CurrentRating_mA=50A, Manufacturer="Omron Electronic Components", Supplier Part Number 1=SW1021CT-ND
S1:A S2: library part CMP-0002230-1, "Switch, SPST, 2 Pos, 25mA, 24VDC, SMD", CurrentRating_mA=25A, Manufacturer="CTS Electrocomponents", Supplier Part Number 1=CT2182LPST-ND
S3 S4: library part CMP-0002233-1, "Switch, Dual SPDT,  2 Pos, 0.1A, 6VDC, SMD", CurrentRating_mA=100A, Manufacturer="Copal Electronics", Supplier Part Number 1=CASD20JCT-ND
TP1 TP1:A TP2 TP2:A TP3 TP3:A TP4 TP5 TP6 TP7 TP8 TP9 TP10: library part CMP-0078143-3, "TEST POINT.  No entry in BOM.", Manufacturer=N/A
U1: library part CMP-0081777-3, "TMS320F28388DZWTS, ZWT0337A (NFBGA-337)", Alternate Manufacturer="Texas Instruments"
U1:A: library part CMP-0073823-1, "Low-Noise, High PSRR, RF 200-mA Low-Dropout Linear Regulators, DBV0005A (SOT-23-5)", Alternate Manufacturer="Texas Instruments", Alternate PartNumber=TPS73033DBVT
U2: library part CMP-0051789-2, "Dual Buffer/Driver with Open-Drain Output, DBV0006A, LARGE T&R", F @ Nom Voltage(Max)(Mhz)=150, Generic Part Number=SN74LVC2G07, ICC @ Nom Voltage(Max)(mA)=0.01, Manufacturer="Texas Instruments", Operating Temperature Range(C)="-40 to 125", Rating=Catalog, tpd @ Nom Voltage(Max)(ns)=8.6,4.4,3.7,2.9, Voltage(Nom)(V)=1.8,2.5,3.3,5
U2:A: library part CMP-0004796-1, "Dual High Speed USB To Multipurpose UART/FIFO IC, LQFP-64", Manufacturer=FTDI, Supplier Part Number 1=768-1024-1-ND
U3: library part CMP-0080903-1, "High-Accuracy, Fixed-Threshold OV/UV Monitor, DDC0006A (SOT-23-T-6)", Alternate Manufacturer="Texas Instruments", Alternate PartNumber=TPS3702CX33DDCR
U3:A: library part CMP-0043096-2, "Low-Capacitance + / - 15 kV ESD-Protection Array for High-Speed Data Interfaces, 2 Channels, -40 to +85 degC, 5-pin SOT (DRL), Green (RoHS & no Sb/Br)", Breakdown Voltage(Min)(V)=11, IO Capacitance(Typ)(pF)=1.5, IO Leakage Current(nA)=1, Manufacturer="Texas Instruments"
U4: library part CMP-0080906-1, "High-Accuracy, Fixed-Threshold OV/UV Monitor, DDC0006A (SOT-23-T-6)", Alternate Manufacturer="Texas Instruments", Alternate PartNumber=TPS3702CX12DDCR
U4:A: library part CMP-0005261-2, "2K Microwire Compatible Serial EEPROM, SOIC-8", Manufacturer=Microchip, Supplier Part Number 1=93LC56C-I/SN-ND
U5: library part CMP-0065661-2, "Low Jitter, 1:4 LVCMOS Fan-out Clock Buffer, PW0008A (TSSOP-8)", Alternate Manufacturer="Texas Instruments"
U5:A U6:A U8:A U9:A: library part CMP-0029375-1, "25 Mbps Dual Channels, 2 / 0, Digital Isolator, 3.3 V / 5 V, -40 to +125 degC, 8-pin SOIC (D), Green (RoHS & no Sb/Br)", Insulation Rating(VRMS)=2500, Manufacturer="Texas Instruments", Rating=Catalog, Supply Voltage(s)(V)="3.3, 5"
U6: library part CMP-0032596-2, "Low Noise, Very Low Drift, Precision Series Voltage Reference, DGK0008A (VSSOP-8)", Manufacturer="Texas Instruments", Rating=Catalog, Temp Coeff(Max)(ppm/ degree C)=3
U7 U8 U9 U10 U11 U12: library part CMP-0066599-1, "Automotive Low-Capacitance 4-Channel +/-15-kV ESD Protection Array for High-Speed Data Interfaces, DBV0006A (SOT-23-6)", Alternate Manufacturer="Texas Instruments"
U7:A: library part CMP-0047070-3, "Octal Buffer/Driver With 3-State OUtputs, PW0020A (TSSOP-20)", Alternate Manufacturer="Texas Instruments", Alternate PartNumber=SN74ALVC244PW, F @ Nom Voltage(Max)(Mhz)=100, Generic Part Number=SN74ALVC244, ICC @ Nom Voltage(Max)(mA)=0.024, Operating Temperature Range(C)="-40 to 85", Rating=Catalog, tpd @ Nom Voltage(Max)(ns)=4.4,3.1,2.8, Voltage(Nom)(V)=1.8,2.5,2.7,3.3
U13: library part CMP-0041147-1, "High-Speed, Single-Supply, Rail-to-Rail Operational Amplifier MicroAmplifier(TM) Series, 2.7 to 5.5 V, -55 to 150 degC, 16-pin SOP (DBQ16), Green (RoHS & no Sb/Br)", Manufacturer="Texas Instruments", Total Supply Voltage(Max)(+5V is 5, +/-5V is 10)=5.5, Total Supply Voltage(Min)(+5V is 5, +/-5V is 10)=2.7
U14: library part CMP-0037884-5, "Dual, Adjustable, 600mA and 1000mA, 2.25MHz Step-Down Converter with 1-Wire Interface in QFN, DRC0010J (VSON-10)", Dynamic Voltage Scaling=TRUE, Manufacturer="Texas Instruments", Operating Temperature Range="-40 to 85 C", Rating=Catalog, Switch Current Limit(Typ)(A)=1
U15: library part CMP-0074276-1, "Single, Current-Limited, Power-Distribution Switch, DBV0005A (SOT-23-5)", Alternate Manufacturer="Texas Instruments", Alternate PartNumber=TPS2051BDBVT
U16: library part CMP-0043122-3, "4-Channel USB ESD Solution with Power Clamp, DRY0006A (USON-6)", Breakdown Voltage(Min)(V)=6, IO Capacitance(Typ)(pF)=0.8, IO Leakage Current(nA)=10, Manufacturer="Texas Instruments", Operating Temperature Range="-40 to 85 C", Rating=Catalog
U17 U19 U21: library part CMP-0076010-4, "Robust, Low Power 10/100 Ethernet Physical Layer Transceiver, RHB0032B (VQFN-32)", Alternate Manufacturer="Texas Instruments", Alternate PartNumber=DP83822IRHBT
U18: library part CMP-0082059-1, "16 Kb I2C EEPROM Serial, SOIC-8", Manufacturer="ON Semiconductor", Supplier Part Number 1=CAT24C16WI-GT3CT-ND
U20: library part CMP-0051777-2, "Dual Inverter Buffer/Driver with Open-Drain Output, DBV0006A, LARGE T&R", F @ Nom Voltage(Max)(Mhz)=150, Generic Part Number=SN74LVC2G06, ICC @ Nom Voltage(Max)(mA)=0.01, Manufacturer="Texas Instruments", Operating Temperature Range(C)="-40 to 125,-40 to 85", Rating=Catalog, tpd @ Nom Voltage(Max)(ns)=8.2,4.4,3.9,3.4, Voltage(Nom)(V)=1.8,2.5,3.3,5
Y1: library part CMP-0082061-2, "Oscillator, 25 MHz, 15 pF, SMD", Frequency_Fixed=25MHz, Frequency Stability="10 ppm", Load Capacitance="15 pF", Manufacturer="ECS Inc.", Supplier Part Number 1=XC2198CT-ND
Y1:A: library part CMP-0004646-3, "Crystal, 12 MHz, 20pF, SMD", Frequency_Fixed=12MHz, Frequency Stability=+/-50ppm, Manufacturer="ECS Inc.", Supplier Part Number 1=XC1118CT-ND
Y2: library part CMP-0082062-2, "Oscillator, 20 MHz, 15 pF, SMD", Frequency_Fixed=20MHz, Frequency Stability="10 ppm", Load Capacitance="15 pF", Manufacturer="ECS Inc.", Supplier Part Number 1=XC2196CT-ND
ZZ1: library part CMP-0003616-3
ZZ2: library part CMP-0077236-1
ZZ3: library part CMP-0077237-1
ZZ4: library part CMP-0077238-1

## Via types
v1: diameter 22, hole 8, Top Layer to Bottom, tented both sides, 895 vias
v2: diameter 18, hole 8, Top Layer to Bottom, tented both sides, 334 vias
v3: diameter 19.68, hole 7.87, Top Layer to Bottom, tented both sides, 19 vias
v4: diameter 18, hole 7.87, Top Layer to Bottom, tented both sides, 1 vias
v5: diameter 18/18/18/18/18/18 (per signal layer), hole 8, Top Layer to Bottom, tented both sides, 1 vias
v6: diameter 22/22/22/22/22/22 (per signal layer), hole 8, Top Layer to Bottom, tented both sides, 1 vias

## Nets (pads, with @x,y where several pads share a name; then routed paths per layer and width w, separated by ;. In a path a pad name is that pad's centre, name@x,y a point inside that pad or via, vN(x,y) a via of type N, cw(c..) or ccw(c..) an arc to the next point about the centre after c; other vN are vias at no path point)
1V2: C50.1 C51.1 C81.2 D4.2 L2.2 L5.1 R89.2 | length 122
  Top Layer w12: L5.1@2380.01,1335 v1(2431.01,1335) ; C81.2@2380.01,1420 2386.7,1413.31 v1(2448.21,1413.31)
  other v1: 3357.21,985.31 3302.21,1025.31 3347.21,1025.31 3302.21,1065.31 3347.21,1065.31
3V3: C45.1 C52.2 C63.2 D4.1 EC1.119 J2.10 L1.2 L3.1 L4.1 R83.1 R86.2 R87.2 | length 905.4
  Top Layer w12: v1(2216.21,626.31) 2216.21,298.79 2313.98,201.02 EC1.119@2313.98,91
  Bottom w12: L4.1@2153.39,567.91 C63.2@2231.5,567.91 2218.8,580.61 2218.8,621.02 2216.21,623.61 v1(2216.21,626.31) ; L3.1@2460.01,915 2460.01,909 2485.8,883.21 ; v1(2480.9,859.6) 2485.8,864.5 2485.8,883.21 ; C52.2@2542.53,915 2542.53,911.93 2513.81,883.21 2485.8,883.21 ; v1(3297.21,910.31) 3301.11,914.22 D4.1@3301.11,955.64
  other v1: 3337.21,855.31 3422.21,855.31 3337.21,895.31 3422.21,900.31
20MHZ_CLK: R39.1 Y2.3 | length 1325.7
  Top Layer w6.25: v1(2711.9,573) 2761.8,573 2761.97,573.17 2782.31,552.83 R39.1@2782.31,551.85
  Signal Layer 3 w6.25: v1@2710.9,573 2710.9,590 2744.33,623.44 3127.76,623.44 3153.51,597.69 3310.2,597.69 3370.7,537.19 3752.33,537.19 v1(3821.21,468.31)
  Bottom w6.25: v1(3821.21,468.31) 3821.21,508.32 Y2.3@3821.47,508.58
25MHZ_CLK: U5.1 Y1.3 | length 82.3
  Bottom w6.25: U5.1@3551.15,508.39 3626.66,508.39 Y1.3@3631.47,503.58
1415_N: C19.1 R59.1 U1.U4 U8.4 | length 1814.2
  Top Layer w5: U8.4@528.82,772.01 534.61,777.79 v1(534.61,820.31) C19.1@534.61,868.82
  Top Layer w6: U8.4@528.82,772.01 536.21,764.62 536.21,728.28 574.21,690.28 574.21,613.28 594.18,593.31 666.18,593.31 704.21,555.28 704.21,545.28 732.42,517.07 732.42,493.37 R59.1@756.42,469.37
  Top Layer w6.25: v2(1656.7,819.88) U1.U4@1672.44,835.63
  Signal Layer 4 w4: 1541.21,844.31 1550.21,835.31 1641.26,835.31 v2(1656.7,819.88)
  Signal Layer 4 w5: v1(534.61,820.31) 514.71,840.21 514.71,852.56 501.61,865.66 501.61,875.74 509.18,883.31 1314.21,883.31 1353.21,844.31 1541.21,844.31
1415_P: C35.1 R58.1 U1.T4 U8.6 | length 1896.3
  Top Layer w5: C35.1@449.61,868.82 456.61,861.82 v1(456.61,818.31) 456.61,774.6 U8.6@454.02,772.01
  Top Layer w6: U8.6@454.02,772.01 454.02,739.5 462.21,731.31 516.21,731.31 562.21,685.31 562.21,608.31 589.21,581.31 661.21,581.31 692.21,550.31 692.21,540.31 712.21,520.31 720.42,512.1 720.42,493.37 R58.1@696.42,469.37
  Top Layer w6.25: v2(1656.7,851.38) U1.T4@1672.44,867.12
  Signal Layer 4 w4: 1541.21,856.31 1552.21,867.31 1640.76,867.31 v2(1656.7,851.38)
  Signal Layer 4 w5: v1(456.61,818.31) 479.71,841.41 479.71,852.56 489.61,862.46 489.61,880.71 504.21,895.31 1319.18,895.31 1358.18,856.31 1541.21,856.31
A0A1_N: C16.1 R52.1 U1.T1 U7.3 | length 2653.3
  Top Layer w6: U7.3@218.42,657.87 v1(218.42,619.41) 186.71,587.71 186.71,557.78 210.18,534.31 355.18,534.31 372.42,517.07 372.42,493.37 R52.1@396.42,469.37
  Top Layer w6.25: v2(1562.21,851.38) U1.T1@1577.96,867.12
  Bottom w6: v1(218.42,619.41) 186.71,587.71 186.71,561.34 163.2,537.83 159.68,534.31 112.24,534.31 108.72,537.83 79.21,567.34 79.21,800.31 180.21,901.31 180.21,1002.28 211.24,1033.31 1041.21,1033.31 1181.52,893 1300.97,893 1348,845.97 1348,834 1384,798 1477.4,798 1521.03,841.63 1543.07,841.63 1552.46,841.63 v2(1562.21,851.38) ; v1@221.01,619.41 221.01,669.5 C16.1@225.01,673.5
A0A1_P: C32.1 R51.1 U1.U1 U7.1 | length 2591.8
  Top Layer w6: v1(143.01,619) 174.71,587.3 174.71,552.8 194.65,532.87 205.21,522.31 350.21,522.31 360.42,512.1 360.42,493.37 R51.1@336.42,469.37 ; v1@143.62,619.61 U7.1@143.62,657.87
  Top Layer w6.25: v2(1562.21,819.88) U1.U1@1577.96,835.63
  Bottom w6: v1(143.01,619) 174.71,587.3 174.71,566.31 154.71,546.31 117.21,546.31 91.21,572.31 91.21,795.34 192.21,896.34 192.21,997.31 216.21,1021.31 1036.24,1021.31 1176.55,881 1296,881 1336,841 1336,829.03 1379.03,786 1482.37,786 1526,829.63 1532.49,829.63 1552.46,829.63 v2(1562.21,819.88) ; C32.1@145.01,673.5 146.01,672.5 v1@146.01,619
A2A3_N: C17.1 R54.1 U1.T2 U7.4 | length 2210.5
  Top Layer w5: U7.4@218.42,772.01 224.21,777.79 v1(224.21,820.31) C17.1@224.21,868.82
  Top Layer w6: U7.4@218.42,772.01 227.21,763.22 227.21,738.28 263.21,702.28 263.21,581.31 280.5,564.02 368.5,564.02 395.21,537.31 462.18,537.31 492.42,507.07 492.42,493.37 R54.1@516.42,469.37
  Top Layer w6.25: v2(1593.7,851.38) U1.T2@1609.45,867.12
  Signal Layer 3 w4: 1537.65,858.31 1546.46,867.12 1577.96,867.12 v2(1593.7,851.38)
  Signal Layer 3 w5: v1(224.21,820.31) 191.21,787.31 191.21,765.31 215.21,741.31 720.21,741.31 765.21,786.31 859.21,786.31 878.21,805.31 878.21,837.28 915.74,874.81 1196.43,874.81 1206.93,864.31 1489.18,864.31 1495.18,858.31 1537.65,858.31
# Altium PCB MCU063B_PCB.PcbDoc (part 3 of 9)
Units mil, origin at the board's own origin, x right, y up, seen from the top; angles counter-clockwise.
Board outline 4165.01 x 2371.03 mil, 10 copper layers (Top Layer, Internal Plane 2, Signal Layer 3, Signal Layer 4, Internal Plane 5, Internal Plane 6, Signal Layer 7, Signal Layer 8, Internal Plane 9, Bottom), stack 59.9 mil thick; 440 components, 394 nets, 1760 pads, 1251 vias.

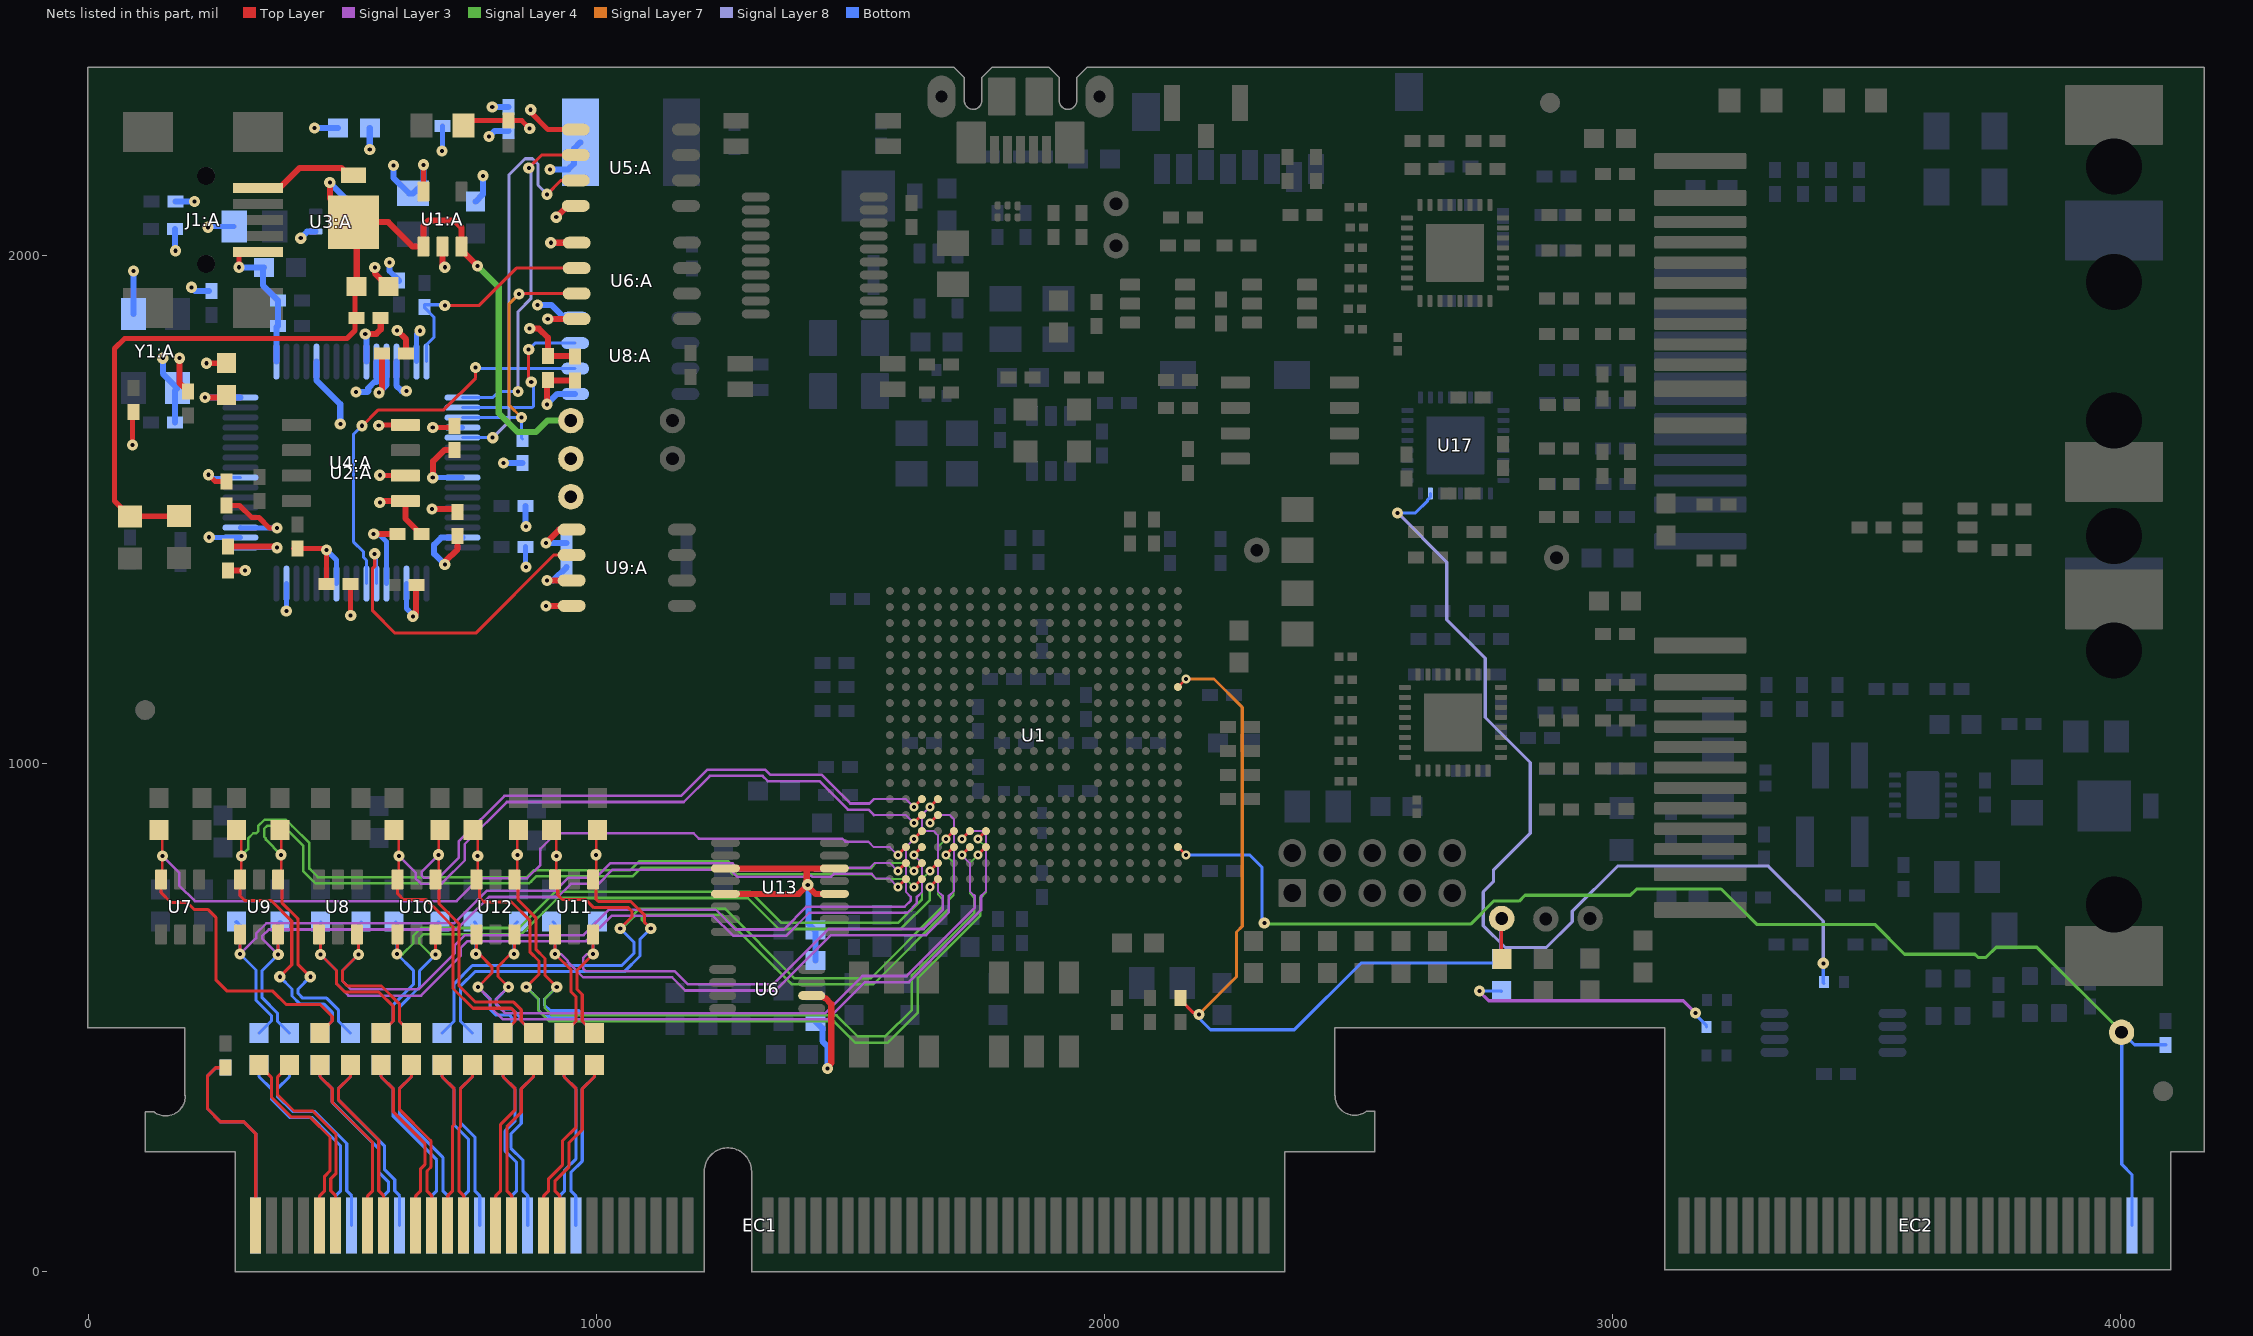
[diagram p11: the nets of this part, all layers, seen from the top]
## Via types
v1: diameter 22, hole 8, Top Layer to Bottom, tented both sides, 895 vias
v2: diameter 18, hole 8, Top Layer to Bottom, tented both sides, 334 vias
v3: diameter 19.68, hole 7.87, Top Layer to Bottom, tented both sides, 19 vias
v4: diameter 18, hole 7.87, Top Layer to Bottom, tented both sides, 1 vias
v5: diameter 18/18/18/18/18/18 (per signal layer), hole 8, Top Layer to Bottom, tented both sides, 1 vias
v6: diameter 22/22/22/22/22/22 (per signal layer), hole 8, Top Layer to Bottom, tented both sides, 1 vias

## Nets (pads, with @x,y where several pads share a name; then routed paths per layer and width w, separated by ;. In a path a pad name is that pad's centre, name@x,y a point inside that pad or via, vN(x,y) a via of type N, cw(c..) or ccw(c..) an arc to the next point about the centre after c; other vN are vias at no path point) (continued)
A2A3_P: C33.1 R53.1 U1.U2 U7.6 | length 2292.6
  Top Layer w5: C33.1@139.21,868.82 146.21,861.82 v1(146.21,818.31) 146.21,774.6 U7.6@143.62,772.01
  Top Layer w6: U7.6@143.62,772.01 143.62,745.9 163.21,726.31 195.21,726.31 209.21,712.31 236.21,712.31 251.21,697.31 251.21,574.31 273.5,552.02 363.53,552.02 390.24,525.31 457.21,525.31 480.42,502.1 480.42,493.37 R53.1@456.42,469.37
  Top Layer w6.25: v2(1593.7,819.88) U1.U2@1609.45,835.63
  Signal Layer 3 w4: 1535.77,846.31 1546.46,835.63 1577.96,835.63 v2(1593.7,819.88)
  Signal Layer 3 w5: v1(146.21,818.31) 179.21,785.31 179.21,760.34 210.24,729.31 725.18,729.31 770.18,774.31 864.18,774.31 890.21,800.34 890.21,832.31 920.71,862.81 1191.46,862.81 1201.71,852.56 1201.71,852.31 1484.21,852.31 1490.21,846.31 1535.77,846.31
A4A5_N: C18.1 R56.1 U1.T3 U8.3 | length 1828.8
  Top Layer w6: U8.3@532.01,663.74 532.01,624.18 v1(532.19,624) 500.69,592.5 500.69,571.83 510.21,562.31 577.18,562.31 612.42,527.07 612.42,493.37 R56.1@636.42,469.37
  Top Layer w6.25: v2(1625.2,851.38) U1.T3@1640.95,867.12
  Signal Layer 3 w4: 1619.21,737.31 1609.21,747.31 1609.21,835.38 v2(1625.2,851.38)
  Signal Layer 3 w5: v1(532.19,624) 500.69,592.5 500.69,571.83 517.21,555.31 650.21,555.31 721.21,626.31 721.21,642.28 741.24,662.31 975.21,662.31 1025.21,712.31 1235.18,712.31 1274.18,673.31 1369.21,673.31 1414.21,718.31 1607.21,718.31 1619.21,730.31 1619.21,737.31
  Bottom w6: v1(532.19,624) 532.19,682.49 C18.1@538.2,688.5
A4A5_P: C34.1 R55.1 U1.U3 U8.1 | length 1834.2
  Top Layer w6: U8.1@457.21,663.74 v1(457.19,624) 488.69,592.5 488.69,566.86 498.21,557.34 ; 498.72,556.83 505.24,550.31 572.21,550.31 600.42,522.1 600.42,493.37 R55.1@576.42,469.37
  Top Layer w6.25: v2(1625.2,819.88) U1.U3@1640.95,835.63
  Signal Layer 3 w4: v2(1625.2,819.88) 1641.21,803.87 1641.21,747.31 1631.21,737.31
  Signal Layer 3 w5: v1(457.19,624) 488.69,592.5 488.69,566.86 512.24,543.31 655.18,543.31 696.69,584.83 733.21,621.34 733.21,637.31 746.21,650.31 980.18,650.31 1030.18,700.31 1230.21,700.31 1269.21,661.31 1374.18,661.31 1419.18,706.31 1612.18,706.31 1631.21,725.34 1631.21,737.31
  Bottom w6: v1(457.19,624) 457.19,687.49 C34.1@458.2,688.5
ADC_3V0_REF: R48.2 U6.6 | length 277.6
  Top Layer w12: U6.6@1424.02,543.3 1443.28,543.3 1448.01,538.57 1450.37,538.57 1462.59,526.35 1462.59,410.29 1455.01,402.71 v1(1455.01,400)
  Bottom w12: R48.2@1431.42,492.12 1432.4,492.12 1445.1,479.42 1445.1,453.8 1455.01,443.89 v1(1455.01,400)
ADC_A0A1_N: EC1.11 R52.2 | length 403.3
  Top Layer w6: R52.2@396.42,406.38 372.42,382.38 372.42,348.58 405,316 441.97,316 488,269.97 488,193.54 477.46,183 477.46,158.87 487.21,149.12 EC1.11@487.21,91
ADC_A0A1_P: EC1.9 R51.2 | length 403.3
  Top Layer w6: R51.2@336.42,406.38 360.42,382.38 360.42,343.61 400.03,304 437,304 476,265 476,198.51 465.46,187.97 465.46,158.87 455.71,149.12 EC1.9@455.71,91
ADC_A2A3_N: EC1.17 R54.2 | length 362.3
  Top Layer w6: R54.2@516.42,406.38 516.42,383.69 492.42,359.69 492.42,338.55 571.95,259.02 571.95,158.87 581.7,149.12 EC1.17@581.7,91
ADC_A2A3_P: EC1.15 R53.2 | length 362.3
  Top Layer w6: R53.2@456.42,406.38 456.42,383.69 480.42,359.69 480.42,333.58 483.93,330.06 559.95,254.05 559.95,158.87 550.2,149.12 EC1.15@550.2,91
ADC_A4A5_N: EC1.23 R56.2 | length 358.4
  Top Layer w6: R56.2@636.42,406.38 636.42,383.69 612.42,359.69 612.42,319.55 671,260.97 674.51,257.46 674.51,205.51 671,202 666.44,197.44 666.44,158.87 676.19,149.12 EC1.23@676.19,91
ADC_A4A5_P: EC1.21 R55.2 | length 358.4
  Top Layer w6: R55.2@576.42,406.38 576.42,383.69 600.42,359.69 600.42,314.58 662.51,252.49 662.51,210.49 654.44,202.41 654.44,158.87 644.69,149.12 EC1.21@644.69,91
ADC_B0B1_N: EC1.14 R61.2 | length 411.4
  Bottom w6: R61.2@396.42,406.38 396.42,383.69 372.42,359.69 372.42,345 402.42,315 445.97,315 508.96,252.01 508.96,158.87 518.71,149.12 EC1.14@518.71,91
ADC_B0B1_P: EC1.12 R60.2 | length 411.4
  Bottom w6: R60.2@336.42,406.38 336.42,383.69 360.42,359.69 360.42,340.03 397.45,303 441,303 496.96,247.04 496.96,158.87 487.21,149.12 EC1.12@487.21,91
ADC_B2B3_N: EC1.20 R63.2 | length 375.3
  Bottom w6: R63.2@516.42,406.38 516.42,383.69 492.42,359.69 492.42,338.55 583,247.97 583,201.42 603.45,180.97 603.45,158.87 613.19,149.12 EC1.20@613.19,91
ADC_B2B3_P: EC1.18 R62.2 | length 375.3
  Bottom w6: R62.2@456.42,406.38 456.42,383.69 480.42,359.69 480.42,333.58 571,243 571,196.45 591.45,176 591.45,158.87 581.7,149.12 EC1.18@581.7,91
ADC_B4B5_N: EC1.26 R65.2 | length 364.8
  Bottom w6: R65.2@636.42,406.38 636.42,383.69 612.42,359.69 612.42,310.55 697.93,225.04 697.93,158.87 707.68,149.12 EC1.26@707.68,91
ADC_B4B5_P: EC1.24 R64.2 | length 364.8
  Bottom w6: R64.2@576.42,406.38 576.42,383.69 600.42,359.69 600.42,305.58 685.93,220.06 685.93,158.87 676.19,149.12 EC1.24@676.19,91
ADC_C2C3_N: EC1.33 R68.2 | length 341.2
  Top Layer w6: EC1.33@833.67,91 833.67,149.12 823.92,158.87 823.92,284.95 852.42,313.45 852.42,359.69 876.42,383.69 R68.2@876.42,406.38
ADC_C2C3_P: EC1.31 R67.2 | length 341.2
  Top Layer w6: EC1.31@802.17,91 802.17,149.12 811.92,158.87 811.92,289.92 840.42,318.42 840.42,359.69 816.42,383.69 R67.2@816.42,406.38
ADC_C4C5_N: EC1.39 R70.2 | length 351.7
  Top Layer w6: EC1.39@928.15,91 928.15,149.12 918.41,158.87 918.41,178 946,205.59 946,253 972.42,279.42 972.42,359.69 996.42,383.69 R70.2@996.42,406.38
ADC_C4C5_P: EC1.37 R69.2 | length 351.7
  Top Layer w6: EC1.37@896.66,91 896.66,149.12 906.41,158.87 906.41,182.97 934,210.56 934,257.97 960.42,284.39 960.42,359.69 936.42,383.69 R69.2@936.42,406.38
ADC_D0D1_N: EC1.30 R73.2 | length 341.2
  Bottom w6: R73.2@756.42,406.38 756.42,383.69 732.42,359.69 732.42,293.55 760.93,265.04 760.93,158.87 770.67,149.12 EC1.30@770.67,91
ADC_D0D1_P: EC1.28 R72.2 | length 341.2
  Bottom w6: R72.2@696.42,406.38 696.42,383.69 720.42,359.69 720.42,288.58 748.93,260.07 748.93,158.87 739.18,149.12 EC1.28@739.18,91
ADC_D2D3_N: EC1.36 R75.2 | length 347.5
  Bottom w6: EC1.36@865.16,91 865.16,149.12 855.41,158.87 855.41,219.55 832,242.97 832,271.03 852.42,291.45 852.42,359.69 876.42,383.69 R75.2@876.42,406.38
ADC_D2D3_P: EC1.34 R74.2 | length 347.5
  Bottom w6: R74.2@816.42,406.38 816.42,383.69 840.42,359.69 840.42,296.42 820,276 820,238 838.97,219.03 843.41,214.58 843.41,158.87 833.67,149.12 EC1.34@833.67,91
ADC_D4D5_N: EC1.42 R81.2 | length 338.7
  Bottom w6: EC1.42@959.65,91 959.65,149.12 949.9,158.87 949.9,194.93 972.42,217.45 972.42,359.69 996.42,383.69 R81.2@996.42,406.38
ADC_D4D5_P: EC1.40 R76.2 | length 338.7
  Bottom w6: EC1.40@928.15,91 928.15,149.12 937.9,158.87 937.9,199.9 960.42,222.42 960.42,359.69 936.42,383.69 R76.2@936.42,406.38
ADC_IN1415_N: EC1.27 R59.2 | length 330.6
  Top Layer w6: EC1.27@739.18,91 739.18,149.12 729.43,158.87 729.43,281.46 732.42,284.45 732.42,359.69 756.42,383.69 R59.2@756.42,406.38
ADC_IN1415_P: EC1.25 R58.2 | length 329.5
  Top Layer w6: R58.2@696.42,406.38 696.42,383.69 720.42,359.69 720.42,289.42 717.43,286.43 ; EC1.25@707.68,91 707.68,149.12 717.43,158.87 717.43,246.03 717.43,285.38
ADC_REF: C12.1 R49.2 U13.3 U13.5 U13.12 U13.14 | length 633.8
  Top Layer w12: U13.5@1254.14,743.6 1398.61,743.6 1413.62,758.61 v1@1416.21,758.61 ; U13.3@1254.14,793.6 1415.21,793.6 ; U13.12@1468.7,743.6 1431.21,743.6 v1@1416.21,758.61 ; U13.14@1468.7,793.6 1415.21,793.6 ; 1415.21,793.6 1414.29,792.69 1414.29,763.23 v1(1416.21,761.31) v1@1416.21,758.61
  Bottom w12: v1(1416.21,761.31) 1417.73,759.78 1417.73,684.82 1430.44,672.12 C12.1@1431.42,672.12 R49.2@1431.42,612.12
B0B1_N: C20.1 R61.1 U1.W2 U9.3 | length 1694.9
  Top Layer w6: U9.3@373.82,663.74 374,663.56 v1(374,624)
  Top Layer w6.25: v2(1593.7,756.89) U1.W2@1609.45,772.63
  Signal Layer 3 w4: 1541.69,782.83 1551.21,773.31 1577.28,773.31 v2(1593.7,756.89)
  Signal Layer 3 w5: v1(374,624) 342.5,655.5 342.5,660.31 355.5,673.31 725.18,673.31 789.18,737.31 924.18,737.31 950.18,763.31 1004.18,763.31 1032.18,791.31 1263.21,791.31 1277.21,777.31 1407.46,777.31 1408.96,778.81 1423.46,778.81 1424.96,777.31 1462.18,777.31 1467.69,782.83 1541.69,782.83
  Bottom w6: C20.1@377.21,688.82 374,685.61 v1(374,624) 342.5,592.5 342.5,539.02 372.42,509.1 372.42,493.37 R61.1@396.42,469.37 ; C20.1@378.76,687.26 C20.1@380.01,688.5
B0B1_P: C36.1 R60.1 U1.V2 U9.1 | length 1713.6
  Top Layer w6: v1(299,625) U9.1@299.02,663.74
  Top Layer w6.25: v2(1593.7,788.38) U1.V2@1609.45,804.13
  Signal Layer 3 w4: 1538.72,794.83 1548.21,804.31 1577.77,804.31 v2(1593.7,788.38)
  Signal Layer 3 w5: v1(299,625) 330.5,656.5 330.5,665.28 350.53,685.31 720.21,685.31 784.21,749.31 919.21,749.31 945.21,775.31 999.21,775.31 1027.21,803.31 1268.18,803.31 1282.18,789.31 1402.49,789.31 1403.99,790.81 1428.43,790.81 1429.93,789.31 1457.21,789.31 1459.21,791.31 1462.72,794.83 1538.72,794.83
  Bottom w6: C36.1@290.01,688.5 C36.1@290.95,687.56 ; C36.1@292.21,688.82 299,682.02 v1(299,625) 330.5,593.5 330.5,534.05 360.42,504.13 360.42,493.37 R60.1@336.42,469.37
B2B3_N: C21.1 R63.1 U1.W3 U9.4 | length 1981.5
  Top Layer w5: U9.4@373.82,772.01 379.61,777.79 v1(379.61,820.31) C21.1@379.61,868.82
  Top Layer w6: U9.4@373.82,772.01 381.21,764.62 381.21,726.28 409.21,698.28 412.72,694.77 412.72,604.8 v1(437.21,580.31)
  Top Layer w6.25: v2(1625.2,756.89) U1.W3@1640.95,772.63
  Signal Layer 4 w4: 1541.21,782.31 1551.21,772.31 1609.77,772.31 v2(1625.2,756.89)
  Signal Layer 4 w5: v1(379.61,820.31) 349.71,850.21 349.71,852.56 346.61,855.66 346.61,871.71 352.21,877.31 384.21,877.31 423.21,838.31 423.21,788.34 443.72,767.83 447.24,764.31 868.18,764.31 871.69,767.83 882.18,778.31 1072.18,778.31 1089.18,795.31 1255.21,795.31 1268.21,782.31 1541.21,782.31
  Bottom w6: v1(437.21,580.31) 413.21,556.31 413.21,547.31 422.21,538.31 469.39,538.31 492.42,515.28 492.42,493.37 R63.1@516.42,469.37
B2B3_P: C37.1 R62.1 U1.V3 U9.6 | length 2064.9
  Top Layer w5: C37.1@294.61,868.82 301.61,861.82 v1(301.61,818.31) 301.61,774.6 U9.6@299.02,772.01
  Top Layer w6: U9.6@299.02,772.01 299.02,739.5 308.21,730.31 360.21,730.31 400.72,689.8 400.72,603.83 v1(377.21,580.31)
  Top Layer w6.25: v2(1625.2,788.38) U1.V3@1640.95,804.13
  Signal Layer 4 w4: 1541.21,794.31 1551.21,804.31 1609.27,804.31 v2(1625.2,788.38)
  Signal Layer 4 w5: v1(301.61,818.31) 314.71,831.41 314.71,852.56 324.96,862.81 331.11,862.81 334.61,866.31 334.61,876.68 347.24,889.31 389.18,889.31 401.69,876.8 435.21,843.28 435.21,793.31 452.21,776.31 863.21,776.31 877.21,790.31 1067.21,790.31 1084.21,807.31 1260.18,807.31 1273.18,794.31 1541.21,794.31
  Bottom w6: v1(377.21,580.31) 401.21,556.31 401.21,542.34 417.24,526.31 464.42,526.31 480.42,510.31 480.42,493.37 R62.1@456.42,469.37
B4B5_N: C22.1 R65.1 U1.W4 U10.3 | length 1486
  Top Layer w6: U10.3@683.82,663.74 683.82,624.18 v1(684,624)
  Top Layer w6.25: v2(1656.7,756.89) U1.W4@1672.44,772.63
  Signal Layer 4 w5: v1(684,624) 674.31,624 652,646.31 652,656.13 660.18,664.31 853.18,664.31 924.18,735.31 1298.21,735.31 1359.21,674.31 1599.18,674.31 1656.7,731.83 v2(1656.7,756.89)
  Bottom w6: R65.1@636.42,469.37 612.42,493.37 612.42,520.52 652,560.1 652,592 v1(684,624) 684,682.49 C22.1@690.01,688.5
B4B5_P: C38.1 R64.1 U1.V4 U10.1 | length 1520.2
  Top Layer w6: v1(608,625) 609.02,626.02 U10.1@609.02,663.74
  Top Layer w6.25: v2(1656.7,788.38) U1.V4@1672.44,804.13
  Signal Layer 4 w4: 1640.71,732.81 1641.21,733.31 1641.21,772.89 v2(1656.7,788.38)
  Signal Layer 4 w5: v1(608,625) 618.69,625 640,646.31 640,661.1 655.21,676.31 848.21,676.31 919.21,747.31 1303.18,747.31 1364.18,686.31 1594.21,686.31 1640.71,732.81
  Bottom w6: R64.1@576.42,469.37 600.42,493.37 600.42,525.5 640,565.07 640,593 v1(608,625) 608,685.51 C38.1@605.01,688.5
C2C3_N: C23.1 R68.1 U1.P3 U10.4 | length 1717.6
  Top Layer w5: U10.4@683.82,772.01 689.61,777.79 v1(689.61,820.31) C23.1@689.61,868.82
  Top Layer w6: U10.4@683.82,772.01 690.69,765.13 690.69,723.8 730.21,684.28 730.21,562.31 762.21,530.31 837.42,530.31 852.42,515.31 852.42,493.37 R68.1@876.42,469.37
  Top Layer w6.25: v2(1625.2,914.37) U1.P3@1640.95,930.12
  Signal Layer 3 w4: 1546.46,930.12 1600.58,930.12 1609.45,930.12 v2(1625.2,914.37)
  Signal Layer 3 w5: v1(689.61,820.31) 656.61,787.31 656.61,778.91 660.21,775.31 690.21,775.31 729.21,814.31 729.21,846.28 819.24,936.31 1167.21,936.31 1218.72,987.83 1332.19,987.83 1342.52,977.5 1443.99,977.5 1500.18,921.31 1537.66,921.31 1546.46,930.12
C2C3_P: C39.1 R67.1 U1.R3 U10.6 | length 1790.2
  Top Layer w5: C39.1@604.61,868.82 611.61,861.82 v1(611.61,818.31) 611.61,774.6 U10.6@609.02,772.01
  Top Layer w6: U10.6@609.02,772.01 609.02,743.5 620.21,732.31 665.21,732.31 718.21,679.31 718.21,557.34 757.24,518.31 832.45,518.31 840.42,510.34 840.42,493.37 R67.1@816.42,469.37
  Top Layer w6.25: v2(1625.2,882.87) U1.R3@1640.95,898.62
  Signal Layer 3 w4: 1546.46,898.62 1609.45,898.62 v2(1625.2,882.87)
  Signal Layer 3 w5: v1(611.61,818.31) 644.61,785.31 644.61,773.94 651.72,766.83 655.24,763.31 695.18,763.31 698.69,766.83 741.21,809.34 741.21,841.31 824.21,924.31 1172.18,924.31 1223.69,975.83 1327.22,975.83 1337.55,965.5 1439.02,965.5 1459.02,945.5 1495.21,909.31 1535.77,909.31 1546.46,898.62
C4C5_N: C24.1 R70.1 U1.P4 U11.3 | length 1370.4
  Top Layer w6: U11.3@993.82,663.74 993.82,625.18 v1(994,625) 962.5,593.5 962.5,555.28 972.42,545.36 972.42,493.37 R70.1@996.42,469.37
  Top Layer w6.25: v2(1656.7,914.37) U1.P4@1672.44,930.12
  Signal Layer 3 w4: v2(1656.7,914.37) 1640.95,898.62 1640.95,875 1648.82,867.12 1664.57,867.12 1672.44,859.25 1672.44,749.01 1672.51,749.01 1682.21,739.31
  Signal Layer 3 w5: v1(994,625) 981.89,625 974.21,617.31 974.21,596.31 979.21,591.31 1154.18,591.31 1180.18,565.31 1348.21,565.31 1457.21,674.31 1644.21,674.31 1682.21,712.31 1682.21,739.31
  Bottom w6: v1(994,625) 994,682.49 C24.1@1000.01,688.5
C4C5_P: C40.1 R69.1 U1.R4 U11.1 | length 1423.2
  Top Layer w6: v1(919,625) 950.5,593.5 950.5,550.31 960.42,540.39 960.42,493.37 R69.1@936.42,469.37 ; v1(919,625) U11.1@919.02,663.74
  Top Layer w6.25: v2(1656.7,882.87) U1.R4@1672.44,898.62
  Signal Layer 3 w4: v2(1656.7,882.87) 1672.44,898.62 1696.07,898.62 1703.94,890.75 1703.94,749.01 ; 1694.21,739.31 1703.91,749.01
  Signal Layer 3 w5: v1(919,625) 930.52,625 944.21,611.31 944.21,609.34 974.24,579.31 1149.21,579.31 1175.21,553.31 1353.18,553.31 1462.18,662.31 1649.18,662.31 1694.21,707.34 1694.21,739.31
  Bottom w6: C40.1@915.01,688.5 919,684.51 v1(919,625)
D0D1_N: C25.1 R73.1 U1.U5 U11.4 | length 1719.8
  Top Layer w5: U11.4@993.82,772.01 999.61,777.79 v1(999.61,820.31) C25.1@999.61,868.82
  Top Layer w6: U11.4@993.82,772.01 999.21,766.62 999.21,733.31 1004.21,728.31 1068.18,728.31 1095.21,701.28 1095.21,687.31 v1(1107.21,675.31)
  Top Layer w6.25: v2(1688.19,819.88) U1.U5@1703.94,835.63
  Signal Layer 4 w4: v2(1688.19,819.88) 1703.21,804.86 1703.21,741.31 1694.21,732.31
  Signal Layer 4 w5: v1@1103.21,675.31 v1(1107.21,675.31) 1089.21,693.31 1089.21,696.31 1095.21,702.31 1248.21,702.31 1385.21,565.31 1545.18,565.31 1694.21,714.34 1694.21,732.31
  Bottom w6: R73.1@756.42,469.37 732.42,493.37 732.42,561.52 761.21,590.31 1055.18,590.31 1086.21,621.34 1086.21,654.31 v1(1107.21,675.31)
D0D1_P: C41.1 R72.1 U1.T5 U11.6 | length 1817
  Top Layer w5: C41.1@914.61,868.82 921.61,861.82 v1(921.61,818.31) 921.61,774.6 U11.6@919.02,772.01
  Top Layer w6: U11.6@919.02,772.01 924.21,766.82 924.21,741.31 933.21,732.31 979.21,732.31 995.21,716.31 1063.21,716.31 1070.21,709.31 1070.21,698.31 v1(1047.21,675.31)
  Top Layer w6.25: v2(1688.19,851.38) U1.T5@1703.94,867.12
  Signal Layer 4 w4: 1682.21,732.31 1672.21,742.31 1672.21,835.39 v2(1688.19,851.38)
  Signal Layer 4 w5: v1(1047.21,675.31) 1051.21,675.31 1074.72,698.83 1074.72,703.8 1085.24,714.31 1253.18,714.31 1390.18,577.31 1540.21,577.31 1682.21,719.31 1682.21,732.31
  Bottom w6: R72.1@696.42,469.37 720.42,493.37 720.42,566.5 756.24,602.31 1050.21,602.31 1074.21,626.31 1074.21,648.31 v1(1047.21,675.31)
D2D3_N: C26.1 R75.1 U1.U6 U12.3 | length 1555.4
  Top Layer w6: v1(827.21,560.31) 806.5,581.02 806.5,600.31 831.19,625 v1(838,625) 838.82,625.82 U12.3@838.82,663.74
  Top Layer w6.25: v2(1719.69,819.88) U1.U6@1735.44,835.63
  Signal Layer 3 w4: v2(1719.69,819.88) 1735.44,804.13 1735.44,749.01 1743.31,741.14
  Signal Layer 3 w5: v1(827.21,560.31) 803.21,536.31 803.21,526.31 821.21,508.31 1450.21,508.31 1520.21,578.31 1523.72,581.83 1610.75,581.83 1745.21,716.28 1745.21,739.24 1743.31,741.14
  Bottom w6: v1(827.21,560.31) 803.21,536.31 803.21,526.31 812.21,517.31 833.45,517.31 852.42,498.34 852.42,493.37 R75.1@876.42,469.37 ; v1(838,625) 838,681.49 C26.1@845.01,688.5
D2D3_P: C42.1 R74.1 U1.T6 U12.1 | length 1684.2
  Top Layer w6: U12.1@764.02,663.74 764.02,626.02 v1(763,625) 769.81,625 794.5,600.31 794.5,587.6 v1(767.21,560.31)
  Top Layer w6.25: v2(1719.69,851.38) U1.T6@1735.44,867.12
  Signal Layer 3 w4: v2(1719.69,851.38) 1735.44,867.12 1759.06,867.12 1766.93,859.25 1766.93,749.01 1759.06,741.14
  Signal Layer 3 w5: v1(767.21,560.31) 791.21,536.31 791.21,521.34 816.24,496.31 1455.18,496.31 1528.69,569.83 1615.72,569.83 1757.21,711.31 1757.21,739.29 1759.06,741.14
  Bottom w6: C42.1@760.01,688.5 763,685.51 v1(763,625) ; v1(767.21,560.31) 791.21,536.31 791.21,516.31 802.21,505.31 828.48,505.31 834.45,499.34 834.45,487.4 R74.1@816.42,469.37
D4D5_N: C27.1 R81.1 U1.U7 U12.4 | length 1727.6
  Top Layer w5: U12.4@838.82,772.01 844.61,777.79 v1(844.61,820.31) C27.1@844.61,868.82
  Top Layer w6: U12.4@838.82,772.01 846.21,764.62 846.21,731.28 881.21,696.28 881.21,634.28 899.21,616.28 899.21,583.31 v1(922.21,560.31)
  Top Layer w6.25: v2(1751.18,819.88) U1.U7@1766.93,835.63
  Signal Layer 4 w4: 1744.21,735.31 1735.21,744.31 1735.21,803.9 v2(1751.18,819.88)
  Signal Layer 4 w5: v1(922.21,560.31) 898.21,536.31 898.21,519.31 913.21,504.31 1473.18,504.31 1514.69,462.8 1568.69,462.8 1621.21,515.31 1621.21,583.28 1744.21,706.28 1744.21,735.31
  Bottom w6: v1(922.21,560.31) 898.21,536.31 898.21,524.31 908.21,514.31 965.18,514.31 972.42,507.07 972.42,493.37 R81.1@996.42,469.37
D4D5_P: C43.1 R76.1 U1.T7 U12.6 | length 1860.1
  Top Layer w5: C43.1@759.61,868.82 766.61,861.82 v1(766.61,818.31) 766.61,774.6 U12.6@764.02,772.01
  Top Layer w6: U12.6@764.02,772.01 770.21,765.82 770.21,736.31 779.21,727.31 833.21,727.31 869.21,691.31 869.21,629.31 887.21,611.31 887.21,585.31 v1(862.21,560.31)
  Top Layer w6.25: v2(1751.18,851.38) U1.T7@1766.93,867.12
  Signal Layer 4 w4: v2(1751.18,851.38) 1767.21,835.35 1767.21,746.31 1756.21,735.31
  Signal Layer 4 w5: v1(862.21,560.31) 886.21,536.31 886.21,514.34 908.24,492.31 1468.21,492.31 1506.21,454.31 1509.72,450.8 1573.66,450.8 1577.18,454.31 1633.21,510.34 1633.21,578.31 1756.21,701.31 1756.21,735.31
  Bottom w6: v1(862.21,560.31) 886.21,536.31 886.21,514.34 898.24,502.31 955.84,502.31 960.42,497.73 960.42,493.37 R76.1@936.42,469.37
EMU0: EC1.2 R2.2 | length 402.3
  Bottom w6.25: R2.2@270.01,401.38 250.89,401.38 235.01,385.5 235.01,320 260.01,295 306.11,295 329.73,271.38 EC1.2@329.73,91
EMU1: EC1.1 R1.1 | length 402.3
  Top Layer w6.25: R1.1@270.01,401.38 250.89,401.38 235.01,385.5 235.01,320 260.01,295 306.11,295 329.73,271.38 EC1.1@329.73,91
EMU_1V8: C5:A.2 C6:A.2 C7:A.2 C8:A.2 U2:A.12 U2:A.37 U2:A.49 U2:A.64 | length 639.3
  Top Layer w12: v1(230.17,1720.27) 267.32,1720.27 C5:A.2@272.16,1725.11 ; C7:A.2@274.77,1427.45 369.28,1427.45 v1(371.96,1424.77) ; v1(561.96,1451.77) C8:A.2@608.34,1451.77 ; v1(572.21,1729.88) 578.54,1736.21 C6:A.2@578.54,1806.61
  Bottom w10: U2:A.49@299.68,1425 371.73,1425 v1(371.96,1424.77) ; v1(561.96,1451.77) 571.96,1451.77 587.08,1436.65 U2:A.37@587.08,1354.13 ; 587.08,1743.08 U2:A.12@587.08,1791.14
  Bottom w12: v1(230.17,1720.27) U2:A.64@299.68,1720.27 ; v1(572.21,1729.88) 587.08,1744.75 U2:A.12@587.08,1791.14
EMU_3V3: C2:A.1 C9:A.2 C10:A.2 C11:A.2 C12:A.2 C20:A.2 C22:A.2 C25:A.2 C27:A.2 L1:A.2 L2:A.2 R1:A.1 R2:A.2 R4:A.2 R8:A.1 R10:A.1 TP2:A.1 U1:A.5 U2:A.20 U2:A.31 U2:A.42 U2:A.50 U2:A.56 U4:A.6 U4:A.8 U5:A.1 U6:A.1 U8:A.8 U9:A.1 | length 1754.7
  Top Layer w10: v1(236.95,1568.41) 250.13,1555.23 C10:A.2@272.16,1555.23 ; R8:A.1@404.15,1423.21 466.28,1423.21 v1(469.27,1420.22) 468.69,1419.64 C12:A.2@468.69,1353.11 ; v1@573.16,1666.61 U4:A.8@624.44,1666.61 ; v1@574.75,1566.61 U4:A.6@624.44,1566.61 ; v1(659.95,2178.41) 659.76,2178.21 U1:A.5@659.76,2125.74 U1:A.5@663.89,2121.61 ; v1(678.18,1661.22) C9:A.2@717.75,1661.22 ; v1@868.46,2284.27 905.1,2247.63 U5:A.1@960.9,2247.63
  Top Layer w12: v1(701.96,1391.77) 701.96,1396.77 727.16,1421.96 C11:A.2@727.16,1447.99 ; v1(869,1856) 887,1856 905,1838 C22:A.2@905,1802.24 905.12,1802.37 956.96,1802.37 C25:A.2@958.34,1800.99 ; v1(901.21,1434.31) 927.21,1460.32 U9:A.1@951.51,1460.32 ; v1(910.52,2025) U6:A.1@961.51,2025
  Bottom w6.25: v1(236.95,1568.41) 242.59,1562.77 U2:A.56@299.68,1562.79
  Bottom w10: v1(235.95,2055.41) 237.16,2056.61 L2:A.2@287.16,2056.61 ; v1@236.96,1446.77 239.05,1444.68 U2:A.50@299.68,1444.68 ; v1@469.27,1420.03 488.65,1400.65 U2:A.42@488.65,1354.13 ; v1(678.18,1661.22) U2:A.20@736.69,1661.22 ; v1@697.06,2206.09 R1:A.1@697.06,2254.68 ; v1@860.78,1472.58 R4:A.2@860.78,1501.61
  Bottom w12: v1(554.21,2208.31) 554.21,2250.76 C2:A.1@554.46,2251.02 ; v1(593.03,1985.8) 593.03,1969.36 R10:A.1@612.16,1950.23 ; v1(601.21,2177.31) 601.21,2152.31 631.46,2122.06 L1:A.2@639.53,2122.06 659.95,2142.48 v1(659.95,2178.41) ; v1(701.96,1391.77) 680.99,1412.74 680.99,1430.8 694.88,1444.68 U2:A.31@736.69,1444.68 ; v1(795.36,2292.31) 795.28,2292.39 C20:A.2@826.96,2292.39 ; v1(817.38,1591.38) R2:A.2@855,1591.38 ; R4:A.2@860.58,1506.77 860.58,1468.15 v1(861.96,1466.77) ; v1(884.21,1902.31) 912.21,1902.31 937.15,1877.37 U8:A.8@958.34,1877.37 ; v1(901.21,1434.31) 941.45,1434.31 C27:A.2@941.82,1433.94
  other v1: 238.23,1445.34 573.95,1567.41 571.95,1665.41 696.68,2205.72 870.96,2286.77
EMU_5V0: C1:A.2 C3:A.1 D1:A.1 D3:A.2 D4:A.2 TP1:A.1 U1:A.1 U1:A.3 U3:A.1 | length 2091.7
  Top Layer w10: D4:A.2@178.95,1486.74 82.33,1486.74 D3:A.2@82.16,1486.57 51.96,1516.76 51.96,1816.77 71.75,1836.55 509.46,1836.55 525.39,1852.48 525.39,1935.59 C3:A.1@528.54,1938.74
  Top Layer w12: D1:A.1@475.62,2112.15 v1(475.62,2143.35) ; C3:A.1@528.54,1938.74 528.54,2059.23 D1:A.1@522.16,2065.61 590.72,2065.61 638.86,2017.48 U1:A.1@659.76,2017.48 659.76,2058.6 669.53,2068.38 721.33,2068.38 734.56,2055.15 734.56,2010.96 v1(766.21,1979.31)
  Signal Layer 4 w12: v1(766.21,1979.31) 808.07,1937.45 808.07,1689.45 845.21,1652.31 881.21,1652.31 903.9,1675 TP1:A.1@950.01,1675
  Bottom w12: v1(475.62,2143.35) 506.29,2112.68 U3:A.1@506.29,2086.3
EMU_GND: C1:A.1 C2:A.2 C3:A.2 C4:A.1 C5:A.1 C6:A.1 C7:A.1 C8:A.1 C9:A.1 C10:A.1 C11:A.1 C12:A.1 C13:A.2 C14:A.1 C15:A.2 C16:A.1 C17:A.1 C18:A.1 C19:A.1 C20:A.1 C22:A.1 C25:A.1 C27:A.1 C29:A.2 D2:A.1 J1:A.5 R5:A.2 R11:A.2 R12:A.1 R13:A.1 R14:A.1 TP3:A.1 U1:A.2 U2:A.1 U2:A.5 U2:A.10 U2:A.11 U2:A.13 U2:A.15 U2:A.25 U2:A.35 U2:A.47 U2:A.51 U3:A.4 U4:A.5 U5:A.4 U6:A.4 U8:A.5 U9:A.3 U9:A.4 Y1:A.2 Y1:A.4 | length 3136.3
  Top Layer w10: v1(86.96,1626.77) 86.96,1682.79 C19:A.1@87.16,1682.99 ; v1(232.96,1787.77) 271.82,1787.77 C5:A.1@272.16,1788.11 ; C10:A.1@272.16,1507.99 297.9,1507.99 321.87,1484.02 336.26,1484.02 356.51,1463.77 v1(371.96,1463.77) ; v1(296.96,1976.77) 296.96,2000.82 305.78,2009.64 J1:A.5@341.82,2009.64 ; v1@390.11,1299.8 v1@390.23,1299.92 ; C12:A.1@515.94,1353.11 515.94,1292.32 v1@516.83,1291.42 ; R14:A.1@643.96,1351.61 R14:A.1@643.96,1352.77 ; D2:A.1@736.96,2256.77 745.43,2265.23 C4:A.1@823.43,2265.23 ; C4:A.1@826.96,2268.77 C4:A.1@823.43,2265.23 ; v1(868.96,2249.77) 853.5,2265.23 C4:A.1@823.43,2265.23
  Top Layer w12: v1(179.96,1797.77) 179.96,1748.77 R12:A.1@196.96,1731.77 ; C7:A.1@274.77,1380.2 v1(309.1,1380.2) ; v1(545.39,1845.57) 566.95,1845.57 575.78,1854.4 C1:A.1@575.78,1876.61 ; v1(564.21,1976.31) 564.21,1965.31 590.78,1938.74 C3:A.2@591.53,1938.74 ; v1(573.96,1513.77) 576.8,1516.61 U4:A.5@624.44,1516.61 624.44,1482.29 C8:A.1@653.96,1452.77 ; v1(608.21,1852.31) 625.78,1834.74 C6:A.1@625.78,1806.61 ; v1(638.96,1289.77) 644.96,1295.77 R14:A.1@644.96,1352.77 ; C8:A.1@655.58,1451.77 C8:A.1@655.58,1452.77 ; v1(676.96,1500.77) 721.62,1500.77 C11:A.1@727.16,1495.23 ; v1(678.18,1562.63) 679.04,1563.49 679.04,1594.97 700.95,1616.89 C9:A.1@720.66,1616.89 ; U1:A.2@697.16,2017.48 697.16,1981.57 v1(701.96,1976.77) ; v1(901.21,1310.32) U9:A.4@951.51,1310.32 ; v1(903,1707) 903,1753 C22:A.1@905,1755 906.25,1753.75 C25:A.1@958.34,1753.75 ; v1(903.2,1360.32) U9:A.3@951.51,1360.32 ; v1(904.52,1875) U6:A.4@961.51,1875 ; v1(921.21,2075.31) 943.53,2097.63 U5:A.4@959.68,2097.63
  Bottom w10: U2:A.51@299.68,1464.37 300.28,1463.77 v1(371.96,1463.77) ; v1@390.23,1299.92 U2:A.47@390.23,1354.13 ; U2:A.35@626.45,1354.13 626.45,1305.28 637.96,1293.77 v1@637.96,1288.77 ; U2:A.15@646.13,1791.14 646.13,1844.94 v1(652.96,1851.77) ; v1@678.18,1562.79 U2:A.25@736.69,1562.79 ; v1@860.78,1395.58 R5:A.2@860.78,1426.61
  Bottom w12: Y1:A.4@88.85,1884.44 88.85,1968.96 v1(89.21,1969.31) ; v1(146.96,1797.77) 146.96,1767.28 Y1:A.2@175.46,1738.77 170.78,1734.09 C14:A.1@170.78,1671.61 ; R11:A.2@170.78,2051.61 170.78,2010.19 v1(171.68,2009.28) ; C17:A.1@171.71,2106.02 208.91,2106.02 v1(209.21,2106.31) ; v1(203.21,1937.31) 210.29,1930.23 C18:A.1@237.74,1930.23 ; v1(296.96,1976.77) 297.12,1976.61 C15:A.2@345.66,1976.61 343.89,1974.84 343.89,1941.25 C16:A.1@373.54,1911.61 R13:A.1@373.54,1861.61 370.54,1858.62 U2:A.1@370.54,1791.14 ; v1(418.35,2034) 431.28,2046.93 U3:A.4@447.63,2046.93 ; v1(445.5,2251.02) C2:A.2@491.47,2251.02 ; U2:A.5@449.28,1791.14 449.28,1754.45 496.21,1707.52 v1(496.21,1668.31) ; v1(527.21,1731.31) 549.21,1731.31 551.21,1733.31 551.21,1738.58 563.51,1750.88 567.39,1750.88 U2:A.11@567.39,1791.14 ; v1(545.39,1845.57) 547.71,1843.25 U2:A.10@547.71,1791.14 ; U2:A.13@606.76,1791.14 606.76,1743.75 617.21,1733.31 v1(626.21,1733.31) ; v1@637.96,1288.77 v1(638.96,1289.77) ; C13:A.2@762.5,2105.91 776.96,2120.37 v1(776.96,2156.77) ; v1(789.21,2234.31) 800.04,2245.15 C20:A.1@826.96,2245.15 ; v1(903,1707) 923.37,1727.37 U8:A.5@958.34,1727.37 ; v1(903.2,1360.32) 915.44,1360.32 C27:A.1@941.82,1386.69 ; v1(909.21,2169.31) 945.21,2169.31 956.21,2180.31 956.21,2210.26 C29:A.2@968.58,2222.63
  other v1: 516.64,1291.04 389.95,1300.27 861.96,1386.77
EMU_SCI-RX: U2:A.38 U9:A.2 | length 646.2
  Top Layer w6.25: v1(563.96,1412.77) 563.96,1388.32 559.9,1384.25 559.9,1300.71 603.84,1256.77 762.66,1256.77 916.21,1410.32 U9:A.2@951.51,1410.32
  Bottom w6: v1@563.96,1411.77 567.39,1408.34 U2:A.38@567.39,1354.13
EMU_SCI-TX: U2:A.39 U8:A.6 | length 809.3
  Top Layer w6.2: v1@538.96,1663.77 571.13,1695.94 699.89,1695.94 762.47,1758.51 v1(762.47,1779.53)
  Bottom w6: v1(538.96,1664.77) 521.96,1647.77 521.96,1436.77 541.96,1416.77 541.96,1405.77 547.71,1400.02 U2:A.39@547.71,1354.13
  Bottom w6.25: v1@762.14,1779.86 v1(762.47,1779.53) 764.63,1777.37 U8:A.6@958.34,1777.37
EMU_TCK: R3:A.1 U2:A.16 U6:A.2 | length 457.1
  Top Layer w6.2: v1(701.96,1901.77) 769.66,1901.77
  Top Layer w6.25: 769.66,1901.77 842.9,1975 892.21,1975 U6:A.2@962.73,1975
  Bottom w6.25: U2:A.16@665.82,1791.14 665.82,1823.88 680.75,1838.81 680.75,1878.51 662.16,1897.1 662.16,1902.99 700.74,1902.99 v1(701.96,1901.77)
EMU_TDI: U2:A.17 U5:A.2 | length 669.5
  Top Layer w6.25: v1(867.21,2172.31) 892.53,2197.63 U5:A.2@959.68,2197.63
  Signal Layer 8 w6: v1(845.83,1731.96) 845.83,1889.39 871.21,1914.77 871.21,2168.31 v1(867.21,2172.31)
  Bottom w6: U2:A.17@736.69,1720.27 796.37,1720.27 808.07,1731.96 v1(845.83,1731.96)
EMU_TDO: U2:A.18 U8:A.7 | length 352.9
  Top Layer w6: v1(867,1815) 867,1756 v1(872,1751)
  Bottom w6: U2:A.18@736.69,1700.59 873.93,1700.59 876.21,1702.86 876.21,1746.79 v1(872,1751) ; v1(867,1815) 879.37,1827.37 U8:A.7@958.34,1827.37
EMU_TMS: R2:A.1 U2:A.19 U6:A.3 | length 535.2
  Top Layer w6.25: v1(848.21,1924.31) 848.9,1925 U6:A.3@961.51,1925
  Signal Layer 7 w6: v1(848.21,1924.31) 827.83,1903.93 827.83,1705.99 v1(852.92,1680.9)
  Bottom w6: U2:A.19@736.69,1680.9 v1(852.92,1680.9) 852.92,1640.71 R2:A.1@855,1638.62
EMU_TRSTn: U2:A.21 U5:A.3 | length 799.5
  Top Layer w6.25: v1(903.21,2120.31) 930.53,2147.63 U5:A.3@959.68,2147.63
  Signal Layer 8 w6: v1(796.21,1641.31) 827.83,1672.93 827.83,2158.39 859.75,2190.31 874.66,2190.31 885.21,2179.77 885.21,2138.31 v1(903.21,2120.31)
  Bottom w6: U2:A.21@736.69,1641.53 795.99,1641.53 v1(796.21,1641.31)
EMU_USB_5V0: D1:A.2 J1:A.1 | length 209.9
  Top Layer w12: J1:A.1@334.66,2132.99 376.89,2132.99 416.21,2172.31 498.21,2172.31 512.91,2157.61 D1:A.2@522.16,2157.61
ENET_PHY_CLK: R35.2 U17.23 | length 1979.7
  Signal Layer 8 w6.25: v1(2577.21,1493.31) 2674.08,1396.44 2674.08,1283.07 2749.83,1207.32 2749.83,1090.5 2838.33,1002 2838.33,862.8 2765.76,790.24 2765.76,767.26 2745.88,747.38 2745.88,680.87 2788.56,638.19 2820.18,638.19 2820.49,637.88 2835.51,637.88 2835.82,638.19 2870.19,638.19 2920.88,688.88 2920.88,709.14 3009.87,798.13 3306.87,798.13 3415,690 v1(3415,606.8)
  Bottom w6.25: v1(2577.21,1493.31) 2577.21,1494.31 2578.21,1493.31 2612.4,1493.31 2636.22,1517.14 2636.22,1519.05 2641.86,1524.69 U17.23@2641.86,1531.57 ; v1(3415,606.8) 3415,568.21 R35.2@3416.42,566.8
ERRORSTS: EC2.178 R18.2 TP1.1 U1.U19 | length 2637.6
  Top Layer w6.25: U1.U19@2144.88,835.63 v2(2160.63,819.88)
  Signal Layer 4 w6.25: v1(2314.8,686.4) 2312.9,686.4 2312.1,685.6 2313.65,684.05 2720.8,684.05 2765.87,729.13 2816.43,729.13 2827.98,740.68 3035.05,740.68 3047.5,753.13 3213.94,753.13 3283.69,683.38 3516.29,683.38 3574.92,624.75 3713.22,624.75 3719.79,618.17 3734.81,618.17 3755.13,638.5 3835.3,638.5 TP1.1@4002.3,471.5
  Bottom w6.25: v2(2160.63,819.88) 2286.27,819.88 2310.33,795.82 2310.33,687.37 2310.76,687.8 2312.16,686.4 v1(2314.8,686.4) ; EC2.178@4022.55,91 4022.55,190.95 4002.3,211.2 4002.3,471.5 4027.42,446.38 R18.2@4089,446.38
F2838x_25MHZ_CLK: R42.2 R43.2 | length 525
  Signal Layer 3 w6.25: v1@2737.21,552.31 2756.39,533.12 3139.39,533.12 v1(3163.68,508.84)
  Bottom w6.25: v1@2737.21,552.31 2780.85,552.31 R43.2@2781.31,551.85 ; v1(3163.68,508.84) 3163.68,505.18 3185.32,483.53 R42.2@3185.32,481.57
  other v1: 2738.21,552.31
F2838x_CLK: R17.2 R39.2 R43.1 TP6.1 U1.G19 | length 1678.6
  Top Layer w6.25: U1.G19@2144.88,1150.59 v2(2160.63,1166.34) ; R17.2@2150.01,538.62 2150.01,534.69 2175.37,509.33 2183.19,509.33 v1(2186.21,506.31) ; TP6.1@2781.01,695 2781.01,616.14 R39.2@2782.31,614.84
  Signal Layer 7 w6.25: v2(2160.63,1166.34) 2215.82,1166.34 2271.58,1110.57 2271.58,679.83 2260.21,668.46 2260.21,580.31 v1(2186.21,506.31)
  Bottom w6.25: v1(2186.21,506.31) 2189.22,503.3 2189.22,495.91 2209.02,476.11 2373.96,476.11 2505.29,607.44 2773.9,607.44 R43.1@2781.31,614.84 2780.01,616.14 TP6.1@2780.01,695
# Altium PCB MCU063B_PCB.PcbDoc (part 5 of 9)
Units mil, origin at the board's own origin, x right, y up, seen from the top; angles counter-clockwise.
Board outline 4165.01 x 2371.03 mil, 10 copper layers (Top Layer, Internal Plane 2, Signal Layer 3, Signal Layer 4, Internal Plane 5, Internal Plane 6, Signal Layer 7, Signal Layer 8, Internal Plane 9, Bottom), stack 59.9 mil thick; 440 components, 394 nets, 1760 pads, 1251 vias.

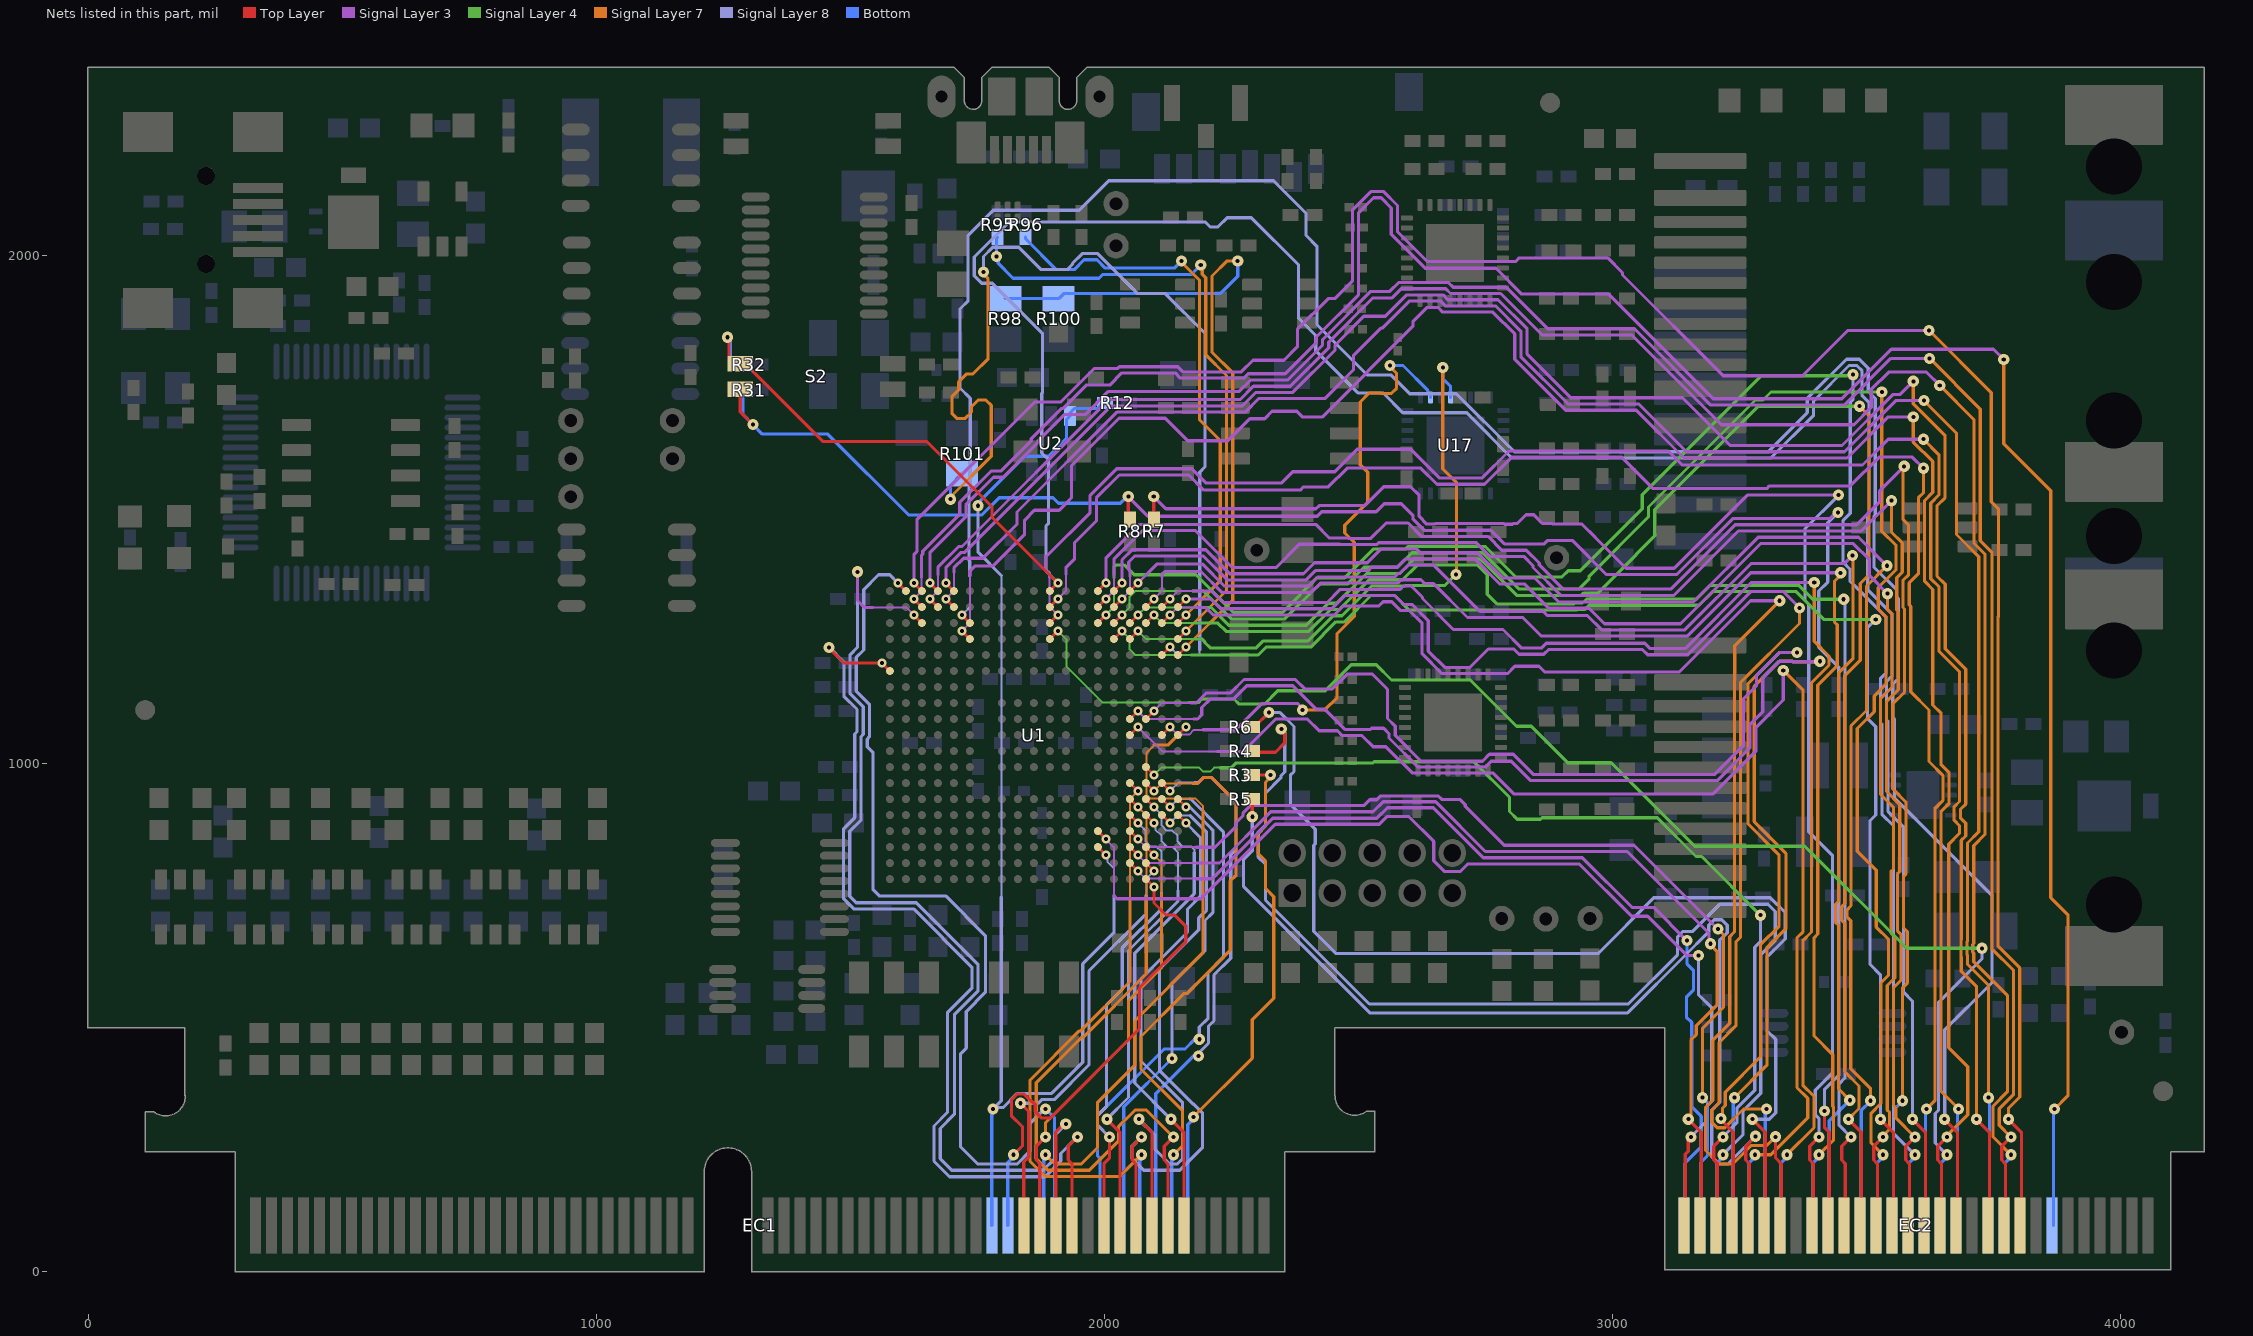
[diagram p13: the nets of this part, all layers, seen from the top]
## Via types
v1: diameter 22, hole 8, Top Layer to Bottom, tented both sides, 895 vias
v2: diameter 18, hole 8, Top Layer to Bottom, tented both sides, 334 vias
v3: diameter 19.68, hole 7.87, Top Layer to Bottom, tented both sides, 19 vias
v4: diameter 18, hole 7.87, Top Layer to Bottom, tented both sides, 1 vias
v5: diameter 18/18/18/18/18/18 (per signal layer), hole 8, Top Layer to Bottom, tented both sides, 1 vias
v6: diameter 22/22/22/22/22/22 (per signal layer), hole 8, Top Layer to Bottom, tented both sides, 1 vias

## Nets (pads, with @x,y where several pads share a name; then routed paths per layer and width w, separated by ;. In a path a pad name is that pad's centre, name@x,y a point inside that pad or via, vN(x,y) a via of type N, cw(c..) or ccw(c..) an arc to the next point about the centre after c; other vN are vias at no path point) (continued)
MCU_GPIO34: EC1.86 R12.1 U1.U14 U2.3 | length 2482.5
  Top Layer w6.25: U1.U14@1987.4,835.63 v2(2003.15,819.88)
  Signal Layer 8 w4: 1797.21,737.31 1797.21,750.2 1797.68,750.67 1797.68,1369.84 ; v2(2003.15,819.88) 2005.83,817.2 2005.83,806.92 2018.9,793.85 2018.9,741
  Signal Layer 8 w6.25: v1(1751.56,1507.31) 1751.56,1415.96 1797.68,1369.84 ; 1797.21,737.31 1797.21,336.21 v1(1780.99,320) 1784.01,323.01 1801.28,323.01 1828.95,350.69 1896.21,350.69 1957.46,411.93 1957.46,605.56 2018.9,667 2018.9,741
  Bottom w6.25: v1(1751.56,1507.31) 1754.58,1510.33 1754.58,1516.06 1843.19,1604.68 1890.32,1604.68 1925.73,1640.09 1925.73,1677.46 U2.3@1932.41,1684.13 1932.41,1690 1941.1,1698.69 1986.14,1698.69 1997.45,1710 R12.1@2001.39,1710 ; EC1.86@1778.55,91 1778.55,317.55 v1(1780.99,320)
MCU_GPIO35: EC2.121 U1.T14 | length 2071.8
  Top Layer w6.25: U1.T14@1987.4,867.12 v2(2003.15,851.38) ; EC2.121@3143.43,91 3143.43,230.84 3149.23,236.65 3149.23,259.86 v1(3154.38,265)
  Signal Layer 3 w4: v2(2003.15,851.38) 2018.9,835.63 2018.9,739.62
  Signal Layer 3 w6.25: 2018.9,739.62 2024.82,733.7 2189.6,733.7 2336.55,880.65 2541.18,880.65 2556.03,895.5 2599.7,895.5 2648.35,846.85 2648.35,808.73 2669.73,787.35 2699.95,787.35 2714.9,802.3 2934.9,802.3 3037.89,699.31 3069.21,699.31 3146.21,622.31 v1(3169.21,622.31)
  Signal Layer 8 w6.25: v1(3154.38,265) 3183.25,293.87 3183.25,322.72 3195.33,334.8 3195.33,519.19 3169.21,545.31 v1(3169.21,622.31)
MCU_GPIO36: EC2.122 U1.V16 | length 1871.8
  Top Layer w6.25: U1.V16@2050.4,804.13 v2(2066.14,788.38)
  Signal Layer 3 w4: v2(2066.14,788.38) 2081.21,773.31 2179.21,773.31
  Signal Layer 3 w6.25: 2179.21,773.31 2212.21,773.31 2331.1,892.2 2536.4,892.2 2557.2,913 2647.28,913 2745.58,814.7 2940.7,814.7 3038.52,716.88 3081.13,716.88 v1(3146.51,651.5)
  Bottom w6.25: EC2.122@3143.43,91 3143.43,214.05 3174.93,245.55 3174.93,305.59 3156.02,324.5 3156.02,490.47 3145.55,500.93 3145.55,540.28 3159.33,554.07 3159.33,593.42 3146.51,606.24 v1(3146.51,651.5)
MCU_GPIO37: EC2.123 U1.U16 | length 1925.4
  Top Layer w6.25: U1.U16@2050.4,835.63 v2(2066.14,819.88) ; v1(3149.38,300) 3174.93,274.45 EC2.123@3174.93,91
  Signal Layer 3 w4: v2(2066.14,819.88) 2081.71,804.31 2181.21,804.31
  Signal Layer 3 w6.25: 2181.21,804.31 2226.71,804.31 2327.4,905 2528.86,905 2548.64,924.78 2652,924.78 2749.96,826.81 3028.83,826.81 3190.19,665.45 3190.19,648.33 v1(3193.21,645.31)
  Signal Layer 7 w6.25: v1(3149.38,300) 3154.52,305.15 3154.52,456.1 3164.96,466.54 3164.96,484.09 3206.33,525.46 3206.33,629.62 3193.21,642.75 v1(3193.21,645.31)
MCU_GPIO38: EC2.124 U1.T16 | length 1944
  Top Layer w6.25: U1.T16@2050.4,867.12 v2(2066.14,851.38)
  Signal Layer 3 w4: v2(2066.14,851.38) 2082.21,835.31 2180.21,835.31
  Signal Layer 3 w6.25: 2180.21,835.31 2217.84,835.31 2259.33,876.8 2259.33,883.93 2273.08,897.68 2273.08,902.82 2287.39,917.13 2510.66,917.13 2522.3,928.77 2536.3,928.77 2543.85,936.33 2656.78,936.33 2663.78,929.32 2699.61,929.32 2710.22,918.71 2710.22,915.74 2786.91,839.06 3042.46,839.06 3207.12,674.4 v1(3207.7,674.4)
  Signal Layer 7 w6.25: v1(3177.21,342.31) 3177.21,479.01 3218.58,520.39 3218.58,662.94 3207.7,673.82 v1(3207.7,674.4)
  Bottom w6.25: EC2.124@3174.93,91 3174.93,216.03 3187.21,228.31 3187.21,332.31 v1(3177.21,342.31)
MCU_GPIO39: EC1.88 U1.W17 | length 1007.8
  Top Layer w6.25: v1(1820.99,230) 1839.12,248.13 1839.12,284.59 1817.08,306.62 1817.08,338.82 1827.7,349.44 1842.71,349.44 1863.86,328.29 1863.86,315.03 1876.7,302.19 1893.71,302.19 2069.07,477.55 2069.07,558.15 2160.33,649.41 2160.33,679.82 2138.38,701.77 2121.26,701.77 2097.64,725.39 v2(2097.64,756.89) U1.W17@2081.89,772.63
  Bottom w6.25: EC1.88@1810.04,91 1810.04,214.05 1825.99,230 v1(1820.99,230)
MCU_GPIO40: EC1.89 U1.V17 | length 873.7
  Top Layer w6.25: v1(1835.21,331.31) 1851.37,315.15 1851.37,225.47 1841.54,215.65 EC1.89@1841.54,91 ; U1.V17@2081.89,804.13 v2(2097.64,788.38)
  Signal Layer 8 w4: 2082.64,741 2082.64,773.38 v2(2097.64,788.38)
  Signal Layer 8 w6.25: v1(1835.21,331.31) 1869.57,331.31 1876.7,338.44 1901.29,338.44 1969.71,406.86 1969.71,591.78 2082.64,704.72 2082.64,741
MCU_GPIO41: EC1.91 U1.U17 | length 862.6
  Top Layer w6.25: EC1.91@1873.04,91 1873.04,212.49 1865.86,219.66 1865.86,246.88 v1(1883.99,265) ; U1.U17@2081.89,835.63 v2(2097.64,819.88)
  Signal Layer 7 w4: v2(2097.64,819.88) 2112.64,804.88 2112.64,741.88
  Signal Layer 7 w6.25: v1(1883.99,265) 1883.99,292.46 2047.58,456.05 2047.58,533.41 2112.64,598.46 2112.64,741.88
MCU_GPIO42: R95.1 U1.D19 | length 1272.3
  Top Layer w6.25: U1.D19@2144.88,1245.08 v2(2160.63,1260.82)
  Signal Layer 7 w6.25: v2(2160.63,1260.82) 2240.38,1340.58 2240.38,1763.67 2199.63,1804.42 2199.63,1956.25 2192.77,1963.11 2192.77,1978.13 v1(2189.76,1981.14)
  Bottom w6.25: R95.1@1790.01,2036.38 1788.01,2034.38 v1(1788.01,1998) 1791.02,1994.99 1791.02,1984.35 1820.19,1955.19 1989.45,1955.19 1996.7,1962.44 2171.06,1962.44 v1(2189.76,1981.14)
MCU_GPIO43: R96.1 U1.C19 | length 1135.2
  Top Layer w6.25: U1.C19@2144.88,1276.57 v2(2160.63,1292.32)
  Signal Layer 7 w6.25: v1(2151.96,1989.19) 2151.96,1986.61 2187.38,1951.18 2187.38,1676.63 2228.13,1635.88 2228.13,1359.82 v2(2160.63,1292.32)
  Bottom w6.25: R96.1@1845.01,2036.38 1845.01,2032.44 1905.26,1972.19 1940.66,1972.19 1959.91,1991.44 1985.56,1991.44 2002,1975 2137.77,1975 v1(2151.96,1989.19)
MCU_GPIO44: U1.K18 U17.2 | length 1272.3
  Top Layer w6.25: U1.K18@2113.39,1056.1 v2(2129.14,1071.85)
  Signal Layer 3 w4: v2(2129.14,1071.85) 2144.14,1056.85 2166.85,1056.85 2176.31,1066.31 2194.21,1066.31
  Signal Layer 3 w6.25: 2194.21,1066.31 2258.95,1066.31 2311.08,1118.44 2380.08,1118.44 v1@2391.36,1107.16
  Signal Layer 7 w6.25: v1(2389.7,1105.5) 2434.14,1105.5 2458.08,1129.44 2458.08,1255.82 2491.76,1289.49 2491.76,1435.13 2473.08,1453.8 2473.08,1468.82 2518.33,1514.07 2518.33,1573.23 2503.83,1587.73 2503.83,1711.57 2521.7,1729.44 2542.58,1729.44 2543.83,1728.19 2564.71,1728.19 2575.33,1738.8 2575.33,1767.62 2562.21,1780.75 v1(2562.21,1783.31)
  Bottom w6.25: v1(2562.21,1783.31) 2587.9,1783.31 2636.22,1734.99 2636.22,1733.08 2641.86,1727.44 U17.2@2641.86,1720.55
MCU_GPIO45: EC1.92 U1.K19 | length 1348.9
  Top Layer w6.25: U1.K19@2144.88,1056.1 v2(2160.63,1071.85)
  Signal Layer 7 w4: 2098.21,1036.31 2082.64,1020.74 2082.64,939.65 2091.43,930.86 2179.66,930.86 2194,916.52 2194,907
  Signal Layer 7 w6.25: v1(1883.99,230) 1902.11,211.88 1954.49,211.88 1986.85,244.23 1986.85,333.24 2059.83,406.23 2059.83,493.3 2194,627.47 2194,907 ; 2098.21,1036.31 2125.1,1036.31 v2(2160.63,1071.85)
  Bottom w6.25: EC1.92@1873.04,91 1880.74,98.7 1880.74,222.49 1883.99,225.74 v1(1883.99,230)
MCU_GPIO46: R98.1 R100.2 U1.E19 | length 1376.3
  Top Layer w6.25: U1.E19@2144.88,1213.58 v2(2160.63,1229.33)
  Signal Layer 7 w6.25: v2(2160.63,1229.33) 2252.63,1321.33 2252.63,1768.74 2211.88,1809.49 2211.88,1959.51 2241.57,1989.19 v1(2262.45,1989.19)
  Bottom w6.25: R98.1@1805.01,1915 R100.2@1910.01,1915 1919.88,1924.88 1995.33,1924.88 2228.49,1924.85 2262.45,1958.81 v1(2262.45,1989.19)
MCU_GPIO47: R101.1 U1.E18 | length 1997.6
  Top Layer w6.25: U1.E18@2113.39,1213.58 v2(2129.14,1229.33)
  Signal Layer 7 w6.25: v1(1697.21,1520.31) 1697.21,1524.57 1777.33,1604.7 1777.33,1704.82 1766.71,1715.44 1751.7,1715.44 1738.61,1702.35 1738.61,1691.97 1725.52,1678.88 1710.5,1678.88 1699.88,1689.49 1699.88,1721.99 1713.29,1735.4 1713.29,1751.03 1729.14,1766.88 1741.52,1766.88 1771.33,1796.69 1771.33,1953.93 1762.21,1963.05 v1(1762.21,1967.31)
  Signal Layer 8 w4: v2(2129.14,1229.33) 2145.15,1213.31 2184.31,1213.31 2187.67,1216.67 2187.67,1223.78
  Signal Layer 8 w6.25: v1(1762.21,1967.31) 1762.21,1997.83 1780.5,2016.13 1831.64,2016.13 1875.58,1972.19 1926.71,1972.19 1937.33,1982.8 1937.33,1984.39 1956.63,2003.69 1987.31,2003.69 2066.12,1924.88 2119.77,1924.88 2198.13,1846.51 2198.13,1583.76 2187.67,1573.29 2187.67,1223.78
  Bottom w6.25: v1(1697.21,1520.31) 1697.21,1548.13 1719.08,1570 R101.1@1720.01,1570
MCU_GPIO48: EC1.99 U1.R16 | length 906
  Top Layer w6.25: EC1.99@1999.02,91 1999.02,212.49 2009.97,223.44 v1(2009.97,265) ; U1.R16@2050.4,898.62 v2(2066.14,882.87)
  Signal Layer 8 w4: v2(2066.14,882.87) 2081.14,867.87 2081.14,846.66 2091.43,836.38 2102.36,836.38 2112.64,826.09 2112.64,745.88
  Signal Layer 8 w6.25: v1(2009.97,265) 1986.85,288.13 1986.85,307.51 2004.08,324.74 2004.08,524.55 2035.33,555.8 2035.33,637.06 2112.64,714.37 2112.64,745.88
MCU_GPIO49: EC1.101 U1.R17 | length 908.7
  Top Layer w6.25: v1(2004.97,300) 2030.52,274.45 EC1.101@2030.52,91 ; U1.R17@2081.89,898.62 v2(2097.64,882.87)
  Signal Layer 8 w4: v2(2097.64,882.87) 2100.32,880.19 2100.32,869.91 2112.64,857.59 2112.64,846.66 2123.3,836 2134.23,836 2144.88,825.34 2144.88,749.83
  Signal Layer 8 w6.25: v1(2004.97,300) 2047.58,342.61 2047.58,631.98 2144.88,729.29 2144.88,749.83
MCU_GPIO50: EC1.103 U1.R18 | length 1209.9
  Top Layer w6.25: EC1.103@2062.01,91 2062.01,212.49 2054.84,219.66 2054.84,246.88 v1(2072.96,265) ; U1.R18@2113.39,898.62 v2(2129.14,882.87)
  Signal Layer 8 w4: v2(2129.14,882.87) 2144.14,897.87 2168.44,897.87
  Signal Layer 8 w6.25: v1(2072.96,265) 2054.84,246.88 2054.84,222.49 2077.7,199.63 2148.54,199.63 2193.33,244.42 2193.33,311.82 2174.96,330.19 2173.7,330.19 2108.8,395.09 2108.8,595.95 2185.83,672.98 2185.83,696.09 2201.26,711.52 2201.26,864.97 2194.45,871.78 2194.45,871.86 2168.44,897.87
MCU_GPIO51: EC1.105 U1.R19 | length 1139.6
  Top Layer w6.25: v1(2067.96,300) 2093.51,274.45 EC1.105@2093.51,91 ; U1.R19@2144.88,898.62 v2(2160.63,882.87)
  Signal Layer 8 w6.25: v1(2067.96,300) 2099.71,268.25 2099.71,240.61 2128.45,211.88 2143.46,211.88 2154.08,222.49 2154.08,332.48 2072.08,414.48 2072.08,576.55 2163.71,668.18 2163.71,713.46 2189.01,738.76 2189.01,854.5 v2(2160.63,882.87)
MCU_GPIO52: EC1.107 U1.P16 | length 1364
  Top Layer w6.25: U1.P16@2050.4,930.12 v2(2066.14,914.37) ; EC1.107@2125.01,91 2125.01,212.49 2117.83,219.66 2117.83,246.88 v1(2135.95,265)
  Signal Layer 7 w4: v2(2066.14,914.37) 2082.64,897.87 2082.64,737.88
  Signal Layer 7 w6.25: 2082.64,737.88 2082.64,585.79 1958.47,461.62 1955.88,461.62 1865.86,371.6 1865.86,222.49 1888.73,199.63 1970.23,199.63 2028.1,257.49 2028.1,285.77 2060.45,318.13 2082.83,318.13 v1(2135.95,265)
MCU_GPIO53: EC1.109 U1.P17 | length 983.3
  Top Layer w6.25: U1.P17@2081.89,930.12 v2(2097.64,914.37) ; v1(2130.95,300) 2156.5,274.45 EC1.109@2156.5,91
  Signal Layer 8 w4: v2(2097.64,914.37) 2112.64,899.37 2112.64,878.15 2122.94,867.86 2133.87,867.86 2144.18,857.55 2144.18,846.62 2154.48,836.31 2171.21,836.31 2177,830.52 2177,825
  Signal Layer 8 w6.25: v1(2130.95,300) 2059.83,371.12 2059.83,626.91 2177,744.08 2177,825
MCU_GPIO54: EC1.100 U1.P18 | length 1072.4
  Top Layer w6.25: U1.P18@2113.39,930.12 v2(2129.14,914.37)
  Signal Layer 8 w4: v2(2129.14,914.37) 2145.08,930.31 2167.49,930.31 2167.69,930.12
  Signal Layer 8 w6.25: 2167.69,930.12 2169.77,930.12 2234.33,865.55 2234.33,618.8 2204.33,588.8 2204.33,498.8 2186.9,481.37 v1(2186.9,457.3)
  Bottom w6.25: EC1.100@1999.02,91 1991.32,98.7 1991.32,223.01 1986.85,227.49 1986.85,307.51 2117.52,438.19 2158.71,438.19 2177.83,457.3 v1(2186.9,457.3)
MCU_GPIO55: EC1.102 U1.P19 | length 948
  Top Layer w6.25: U1.P19@2144.88,930.12 v2(2160.63,914.37)
  Signal Layer 8 w6.25: v1@2133.08,419.52 2133.08,566.55 2198.08,631.55 2198.08,691.02 2213.71,706.64 2213.71,868.86 2206,876.56 2206,876.64 2168.27,914.37 v2(2160.63,914.37)
  Bottom w6.25: EC1.102@2030.52,91 2038.22,98.7 2038.22,324.62 v1(2133.1,419.5)
MCU_GPIO56: EC1.104 U1.N16 | length 1233.3
  Top Layer w6.25: U1.N16@2050.4,961.61 v2(2066.14,945.86)
  Signal Layer 7 w4: 2050.59,734.7 2050.59,930.31 v2(2066.14,945.86)
  Signal Layer 7 w6.25: 2050.59,734.7 2050.59,571.07 1953.4,473.87 1950.81,473.87 1853.61,376.67 1853.61,217.42 1883.65,187.38 2030.34,187.38 v1(2072.96,230)
  Bottom w6.25: EC1.104@2062.01,91 2069.71,98.7 2069.71,222.49 2072.96,225.74 v1(2072.96,230)
MCU_GPIO57: EC1.106 U1.N18 | length 1091.1
  Top Layer w6.25: U1.N18@2113.39,961.61 v2(2129.14,945.86)
  Signal Layer 8 w4: v2(2129.14,945.86) 2145.58,962.31 2177.21,962.31
  Signal Layer 8 w6.25: 2177.21,962.31 2184.98,962.31 2195.39,972.72 2210.41,972.72 2259.33,923.8 2259.33,831.05 2248.63,820.35 2248.63,616.77 2215.88,584.02 2215.88,494.02 2205.03,483.16 2205.03,449.79 2185.6,430.37 v1(2185.6,424.5)
  Bottom w6.25: EC1.106@2093.51,91 2101.21,98.7 2101.21,349.95 2175.76,424.5 v1(2185.6,424.5)
MCU_GPIO58: EC1.108 U1.N17 | length 1175.4
  Top Layer w6.25: U1.N17@2081.89,961.61 v2(2097.64,945.86)
  Signal Layer 7 w4: v2(2097.64,945.86) 2112.64,960.86 2174,960.86
  Signal Layer 7 w6.25: v1(2135.95,230) 2154.08,248.13 2154.08,316.6 2072.08,398.6 2072.08,462.82 2156.89,547.62 2163.15,547.62 2247.96,632.43 2247.96,768.94 2259.33,780.31 2259.33,923.8 2210.41,972.72 2195.39,972.72 2183.53,960.86 2174,960.86
  Bottom w6.25: EC1.108@2125.01,91 2132.71,98.7 2132.71,222.49 2135.95,225.74 v1(2135.95,230)
MCU_GPIO59: EC1.110 R3.1 | length 1018.8
  Top Layer w6.25: R3.1@2290.87,977.36 2290.92,977.31 v1(2327.21,977.31)
  Signal Layer 7 w6.25: v1(2175.21,304.31) 2291.08,420.19 2291.08,495.55 2333.4,537.87 2333.4,715.07 2333.39,737.98 2317.08,754.29 2317.08,808.4 2302.7,822.78 2302.7,861.82 2317.08,876.2 2317.08,962.93 2327.21,973.05 v1(2327.21,977.31)
  Bottom w6.25: EC1.110@2156.5,91 2164.2,98.7 2164.2,289.05 2175.21,300.05 v1(2175.21,304.31)
MCU_GPIO60: EC2.125 U1.M17 | length 2029
  Top Layer w6.25: U1.M17@2081.89,993.11 v2(2097.64,977.36) ; EC2.125@3206.42,91 3206.42,212.49 3199.25,219.67 3199.25,246.88 v1(3217.37,265)
  Signal Layer 4 w4: v2(2097.64,977.36) 2112.64,992.36 2186.12,992.36 2194.3,984.18 2208.39,984.18 2216.01,991.8 2227.9,991.8
  Signal Layer 4 w6.25: 2227.9,991.8 2250,991.8 2259.39,1001.19 2528.71,1001.19 2530.96,1003.44 2727.28,1003.44 2797.33,933.38 2797.33,905.55 2812.7,890.19 2858.45,890.19 2861.7,893.44 3088.08,893.44 3164.41,817.11 3175.59,817.11 v1(3291.2,701.5)
  Signal Layer 8 w6.25: v1(3217.37,265) 3244.99,292.62 3244.99,321.46 3280.21,356.68 3280.21,638.11 3291.2,649.11 v1(3291.2,701.5)
MCU_GPIO61: EC2.126 R4.1 | length 2337.9
  Top Layer w6.25: R4.1@2290.87,1024.6 2293.25,1022.23 2336.87,1022.23 2355.21,1040.57 2355.21,1060.89 v1(2348.3,1067.8)
  Signal Layer 8 w6.25: v1(2348.3,1067.8) 2355.21,1060.89 2355.21,983.27 2347.49,975.55 2347.49,971.96 2317.08,941.55 2317.08,879.6 2302.76,865.27 2302.76,815.92 2317.08,801.6 2317.08,731.22 2521.6,526.7 3031.1,526.7 3128.38,623.98 3128.38,659 3139,669.62 3158.12,669.62 3211.5,723 3306.1,723 3320.4,708.7 3320.4,652.46 3291.83,623.89 3291.83,350.98 3257.24,316.39 3257.24,269.87 v1(3217.37,230)
  Bottom w6.25: EC2.126@3206.42,91 3206.42,214.05 3222.37,230 v1(3217.37,230)
MCU_GPIO62: EC2.127 U1.J17 | length 2906.6
  Top Layer w6.25: U1.J17@2081.89,1087.6 v2(2097.64,1103.34) ; v1(3213.62,301.25) 3213.62,298.75 3237.92,274.45 EC2.127@3237.92,91
  Signal Layer 3 w4: v2(2097.64,1103.34) 2113.39,1119.09 2170.99,1119.09
  Signal Layer 3 w6.25: 2170.99,1119.09 2181.09,1119.09 2201.06,1139.06 2248.61,1139.06 2274.92,1165.38 2376.1,1165.38 2394.6,1146.88 2448.88,1146.88 2477.95,1175.94 2509.21,1175.94 2509.7,1176.44 2526.78,1176.44 2557.21,1146.01 2557.21,1088.69 2572.58,1073.31 2572.58,1055.29 2623.27,1004.6 2744.22,1004.6 2757.93,1018.32 2804.68,1018.32 2844.32,978.69 3201.23,978.69 3258.21,1035.66 3258.21,1127.99 3283.71,1153.49 3283.71,1173.77 3328.25,1218.31 v1(3363.21,1218.31)
  Signal Layer 7 w6.25: v1(3213.62,301.25) 3216.63,304.26 3216.63,321.46 3222.08,326.91 3222.08,353.19 3291.21,422.31 3291.21,643.11 3328.1,680 3328.1,819.83 3266.83,881.1 3266.83,1156.89 3328.25,1218.31 v1(3363.21,1218.31)
MCU_GPIO63: EC2.128 U1.J16 | length 2944.8
  Top Layer w6.25: U1.J16@2050.4,1087.6 v2(2066.14,1103.34)
  Signal Layer 3 w4: v2(2066.14,1103.34) 2081.89,1087.6 2175.21,1087.6
  Signal Layer 3 w6.25: 2175.21,1087.6 2183.6,1087.6 2191.7,1095.7 2191.7,1110.32 2208.19,1126.81 2253.68,1126.81 2279.99,1153.13 2371.03,1153.13 2417.28,1106.88 2433.77,1106.88 2473.46,1067.19 2523.71,1067.19 2525.96,1069.44 2549.71,1069.44 2560.33,1058.82 2560.33,1050.21 2617.5,993.05 2749.99,993.05 2761.38,1004.44 2801.24,1004.44 2839.24,966.44 3206.3,966.44 3270.46,1030.59 3270.46,1076.52 3295.96,1102.02 3295.96,1168.69 3328.7,1201.44 3354.45,1201.44 3355.7,1200.19 3407.08,1200.19 v1(3408.21,1201.31)
  Signal Layer 7 w6.25: v1(3240.21,342.31) 3304.08,406.19 3304.08,637.27 3341.5,674.69 3341.5,823.23 3279.08,885.65 3279.08,1151.82 3328.7,1201.44 3354.45,1201.44 3355.7,1200.19 3407.08,1200.19 v1(3408.21,1201.31)
  Bottom w6.25: EC2.128@3237.92,91 3237.92,340.02 v1(3240.21,342.31)
MCU_GPIO64: EC2.129 R5.1 | length 2091.5
  Top Layer w6.25: R5.1@2290.87,930.12 2291.21,929.78 v1(2291.21,895.31) ; EC2.129@3269.41,91 3269.41,212.49 3262.24,219.67 3262.24,246.88 v1(3281.61,266.25)
  Signal Layer 8 w6.25: v1(2291.21,895.31) 2291.21,828.27 2274.08,811.15 2274.08,757.72 2522.5,509.3 3029.94,509.3 3035.79,515.15 3035.88,515.15 3139.93,619.2 3139.93,619.29 3189.58,668.93 3189.58,681.91 3200.19,692.52 3215.21,692.52 3225.83,681.91 3225.83,666.89 3215.21,656.27 3214.79,656.27 3211.33,652.82 3211.33,333.48 3195.5,317.64 3195.5,226.24 3209.86,211.88 3227.24,211.88 v1(3281.61,266.25)
MCU_GPIO65: EC2.130 U1.K16 | length 2757.1
  Top Layer w6.25: U1.K16@2050.4,1056.1 v2(2066.14,1071.85)
  Signal Layer 3 w4: v2(2066.14,1071.85) 2114.14,1023.86 2166.85,1023.86 2167,1023.7 2221.7,1023.7
  Signal Layer 3 w6.25: 2221.7,1023.7 2273.23,1023.7 2336.9,1087.38 2399.76,1087.38 2422.7,1064.44 2458.88,1064.44 2468.38,1054.94 2507.21,1054.94 2528.96,1033.19 2553.96,1033.19 2605.65,981.5 2764.4,981.5 2805.71,940.19 3198.05,940.19 3282.71,1024.84 3282.71,1071.44 3336.21,1124.94 v1(3336.21,1183.31)
  Signal Layer 7 w6.25: v1(3280.36,230) 3311.53,230 3384.47,302.94 3384.47,341.02 3363.33,362.17 3363.33,657.12 3375.33,669.13 3375.33,1144.19 v1(3336.21,1183.31)
  Bottom w6.25: EC2.130@3269.41,91 3269.41,214.05 3285.36,230 v1(3280.36,230)
MCU_GPIO66: EC2.131 R6.1 | length 2223.8
  Top Layer w6.25: R6.1@2290.87,1071.85 2294.81,1071.85 2323.27,1100.31 v1(2324.21,1100.31) ; v1(3275.36,300) 3300.91,274.45 EC2.131@3300.91,91
  Signal Layer 8 w6.25: v1(2324.21,1100.31) 2345.84,1100.31 2373.33,1072.82 2373.33,984.07 2366.08,976.82 2366.08,919.65 2415.03,870.71 2415.03,841.85 2412.13,838.95 2412.13,670 2456.2,625.94 2971.58,625.94 3081.44,735.8 3311,735.8 3340,706.8 3340,654.74 3304.08,618.82 3304.08,474.36 3321.48,456.96 3321.48,312.49 3308.99,300 v1(3275.36,300)
MCU_GPIO67: EC2.132 U1.B19 | length 2876.8
  Top Layer w6.25: U1.B19@2144.88,1308.07 v2(2160.63,1323.82)
  Signal Layer 3 w6.25: v2(2160.63,1323.82) 2209.73,1323.82 2228.92,1304.63 2447.52,1304.63 2473.46,1330.56 2543.5,1330.56 2543.63,1330.69 2571.2,1330.69 2588.7,1313.19 2605.61,1313.19 2637.66,1281.14 2637.66,1221.23 2669.7,1189.19 2719.71,1189.19 2755.96,1225.44 2805.71,1225.44 2816.21,1214.94 2865.2,1214.94 2874.7,1224.44 3058.71,1224.44 3069.21,1213.94 3148.09,1213.94 3272.59,1338.44 3336.71,1338.44 3368.21,1306.94 v1(3368.21,1306.31)
  Signal Layer 7 w6.25: v1(3303.36,320) 3258,320 3221.13,283.13 3206.11,283.13 3195.5,293.74 3195.5,317.64 3209.83,331.98 3209.83,450.64 3243.08,483.89 3243.08,648.78 3251.8,657.5 3251.8,1159.19 3368.21,1275.59 v1(3368.21,1306.31)
  Bottom w6.25: EC2.132@3300.91,91 3300.91,317.56 v1(3303.36,320)
MCU_GPIO68: EC2.133 U1.C18 | length 2900.3
  Top Layer w6.25: U1.C18@2113.39,1276.57 v2(2129.14,1292.32) ; v1(3321.21,265.31) 3321.21,223.69 3332.41,212.49 EC2.133@3332.41,91
  Signal Layer 3 w4: v2(2129.14,1292.32) 2144.14,1307.32 2181.2,1307.32
  Signal Layer 3 w6.25: 2181.2,1307.32 2199.06,1307.32 2214,1292.38 2452.59,1292.38 2470.16,1309.94 2540.2,1309.94 2548.7,1318.44 2565.87,1318.44 2583.37,1300.94 2600.54,1300.94 2625.41,1276.07 2625.41,1216.16 2664.63,1176.94 2793.46,1176.94 2807.96,1191.44 2855.45,1191.44 2866.7,1180.19 3131.66,1180.19 3271.78,1320.31 v1(3329.21,1320.31)
  Signal Layer 7 w6.25: v1(3321.21,265.31) 3304.02,248.13 3272.86,248.13 3236.61,211.88 3209.86,211.88 3183.25,238.49 3183.25,322.72 3197.58,337.05 3197.58,455.71 3230.83,488.96 3230.83,659.13 3240.25,668.55 3240.25,1163.97 3240.7,1164.42 3240.7,1231.8 v1(3329.21,1320.31)
MCU_GPIO69: EC2.134 U1.B18 | length 2775.1
  Top Layer w6.25: U1.B18@2113.39,1308.07 v2(2129.14,1323.82)
  Signal Layer 3 w4: v2(2129.14,1323.82) 2144.63,1339.31 2173.21,1339.31
  Signal Layer 3 w6.25: 2173.21,1339.31 2211.56,1339.31 2234,1316.88 2438.52,1316.88 2464.45,1342.81 2538.43,1342.81 2538.55,1342.94 2582.2,1342.94 2588.7,1349.44 2603.71,1349.44 2626.08,1327.07 2626.08,1324.8 2687.07,1263.81 2784.66,1263.81 2821.29,1227.19 2860.13,1227.19 2869.63,1236.69 3063.79,1236.69 3074.29,1226.19 3143.01,1226.19 3273.14,1356.31 v1(3397.21,1356.31)
  Signal Layer 7 w6.25: v1(3343.36,230) 3396.72,283.37 3396.72,345.11 3374.87,366.95 3374.87,651.54 3391.83,668.5 3391.83,1159.3 3426.33,1193.8 3426.33,1211.55 3397.21,1240.68 v1(3397.21,1356.31)
  Bottom w6.25: EC2.134@3332.41,91 3332.41,214.05 3348.36,230 v1(3343.36,230)
MCU_GPIO70: EC2.137 R7.1 | length 3102.8
  Top Layer w6.25: v1(2097.21,1525.31) 2097.21,1480.98 R7.1@2097.64,1480.55 ; EC2.137@3395.4,91 3395.4,212.49 3388.22,219.67 3388.22,246.88 v1(3406.35,265)
  Signal Layer 3 w6.25: v1(2097.21,1525.31) 2121.08,1501.44 2416.38,1501.44 2422.63,1507.69 2512.86,1507.69 2549.93,1544.76 2602.66,1544.76 2619.42,1528 2619.42,1486.47 2634.7,1471.19 2649.71,1471.19 2650.96,1472.44 2786.43,1472.44 2787.99,1470.88 2803.01,1470.88 2804.57,1472.44 2812.9,1472.44 2829.99,1489.52 2845.01,1489.52 2862.1,1472.44 2881.1,1472.44 2882.1,1471.44 2939.71,1471.44 2966.08,1445.07 2966.08,1444.8 3026.7,1384.19 3121.43,1384.19 3265.56,1528.31 v1(3445.21,1528.31)
  Signal Layer 8 w6.25: v1(3406.35,265) 3406.35,301.54 3399.08,308.8 3399.08,357.19 3433.33,391.44 3433.33,818.55 3386.33,865.55 3386.33,1313.82 3379.08,1321.07 3379.08,1462.19 v1(3445.21,1528.31)
MCU_GPIO71: EC2.138 U1.B17 | length 2890.3
  Top Layer w6.25: U1.B17@2081.89,1308.07 v2(2097.64,1323.82)
  Signal Layer 3 w4: v2(2097.64,1323.82) 2113.21,1339.38 2113.21,1367.31
  Signal Layer 3 w6.25: 2113.21,1367.31 2113.21,1372.21 2119,1378 2190.19,1378 2231.32,1336.88 2407.25,1336.88 2425.56,1355.19 2577.13,1355.19 2583.63,1361.69 2623.2,1361.69 2630.7,1354.19 2647.96,1354.19 2714.71,1287.44 2823.71,1287.44 2860.46,1250.69 3147.26,1250.69 3271.88,1375.31 v1(3449.21,1375.31)
  Signal Layer 7 w6.25: v1(3406.35,230) 3435.33,258.99 3435.33,323.82 3433.58,325.57 3433.58,426.92 3396.87,463.62 3396.87,657.2 3404.08,664.41 3404.08,1154.23 3442.33,1192.48 3442.33,1273.08 3437.08,1278.33 3437.08,1358.93 3449.21,1371.05 v1(3449.21,1375.31)
  Bottom w6.25: EC2.138@3395.4,91 3395.4,214.05 3411.35,230 v1(3406.35,230)
MCU_GPIO72: EC2.139 R8.1 R31.2 S2.2 | length 4039
  Top Layer w6.25: S2.2@1283.36,1736.81 1283.36,1692.16 v1(1308.21,1667.31) ; v1(2047.21,1525.31) 2047.21,1483.74 R8.1@2050.4,1480.55 ; v1(3417.21,316.31) 3417.21,284.14 3426.89,274.45 EC2.139@3426.89,91
  Signal Layer 3 w6.25: v1(2047.21,1525.31) 2085.71,1486.81 2419.07,1486.81 2427.7,1495.44 2534.98,1495.44 2550.98,1511.44 2584.71,1511.44 2607.17,1488.98 2607.17,1481.39 2629.63,1458.94 2654.79,1458.94 2655.04,1459.19 2760.33,1459.19 2787.33,1432.19 2865.71,1432.19 2872.65,1439.13 2920.76,1439.13 2987.95,1371.94 3126.51,1371.94 3236.7,1482.13 3427.76,1482.13 3439.95,1494.31 v1(3444.21,1494.31)
  Signal Layer 8 w6.25: v1(3417.21,316.31) 3417.21,357.99 3445.58,386.36 3445.58,1189.57 3406.08,1229.07 3406.08,1339.55 3423.64,1357.11 3423.64,1473.74 v1(3444.21,1494.31)
  Bottom w6.25: R31.2@1276.39,1735 1280.32,1735 1289.01,1726.31 1289.01,1686.51 v1(1308.21,1667.31) 1327.08,1648.44 1455.94,1648.44 1615.19,1489.19 1759.07,1489.19 1792.82,1522.94 1898.95,1522.94 1909.7,1512.19 2031.52,1512.19 2044.64,1525.31 v1(2047.21,1525.31)
MCU_GPIO73: EC2.140 U1.A16 | length 2954.2
  Top Layer w6.25: U1.A16@2050.4,1339.56 v2(2066.14,1355.31)
  Signal Layer 3 w6.25: v2(2066.14,1355.31) 2103.83,1393 2192.52,1393 2236.39,1349.13 2402.18,1349.13 2420.49,1367.44 2572.05,1367.44 2578.55,1373.94 2581.79,1373.94 2598.29,1390.44 2648.45,1390.44 2739.2,1299.69 2863.46,1299.69 2871.71,1291.44 2950.71,1291.44 2979.21,1262.94 3142.18,1262.94 3272.68,1393.44 3456.33,1393.44 v1(3472.21,1409.31)
  Signal Layer 7 w6.25: v1(3467.21,337.31) 3445.13,359.38 3445.13,681.57 3438.78,687.92 3438.78,722.08 3444.82,728.11 3444.82,1177.65 3473.33,1206.16 3473.33,1408.19 v1(3472.21,1409.31)
  Bottom w6.25: EC2.140@3426.89,91 3426.89,297 v1(3467.21,337.31)
MCU_GPIO74: EC2.141 U1.C17 | length 2785.9
  Top Layer w6.25: U1.C17@2081.89,1276.57 v2(2097.64,1292.32) ; EC2.141@3458.39,91 3458.39,212.49 3451.21,219.67 3451.21,246.88 v1(3469.34,265)
  Signal Layer 4 w4: v2(2097.64,1292.32) 2113.65,1276.31 2176.21,1276.31
  Signal Layer 4 w6.25: 2176.21,1276.31 2223.56,1276.31 2239.81,1260.06 2402.47,1260.06 2445.59,1303.19 2462.66,1303.19 2521.16,1361.69 2586.86,1361.69 2615.61,1390.44 2734.71,1390.44 2753.71,1371.44 2753.71,1333.18 2772.7,1314.19 2923.8,1314.19 2925.55,1315.94 2941.11,1315.94 2948.86,1323.69 3165.21,1323.69 3192.21,1350.69 3366.79,1350.69 3394.16,1323.31 v1(3455.21,1323.31)
  Signal Layer 8 w6.25: v1(3455.21,1323.31) 3457.83,1320.69 3457.83,381.29 3446.21,369.67 3446.21,288.13 v1(3469.34,265)
MCU_GPIO75: U1.D16 U17.4 | length 1206.4
  Top Layer w6.25: U1.D16@2050.4,1245.08 v2(2066.14,1260.82)
  Signal Layer 4 w4: v2(2066.14,1260.82) 2081.66,1245.31 2178.21,1245.31
  Signal Layer 4 w6.25: 2178.21,1245.31 2191.69,1245.31 2197.63,1239.37 2197.63,1238.23 2208.24,1227.62 2299.26,1227.62 2313.02,1241.38 2401.1,1241.38 2450.67,1290.94 2467.73,1290.94 2526.23,1349.44 2591.94,1349.44 2592.94,1350.44 2670.33,1350.44 v1(2692.21,1372.31)
  Signal Layer 7 w6.25: v1(2666.21,1779.31) 2666.21,1579.69 2693.33,1552.56 2693.33,1373.44 v1(2692.21,1372.31)
  Bottom w6.25: v1(2666.21,1779.31) 2666.21,1757.68 2681.23,1742.66 U17.4@2681.23,1720.55
MCU_GPIO76: EC2.143 U1.C16 | length 3408.8
  Top Layer w6.25: U1.C16@2050.4,1276.57 v2(2066.14,1292.32) ; v1(3464.34,300) 3489.89,274.45 EC2.143@3489.89,91
  Signal Layer 4 w4: v2(2066.14,1292.32) 2081.14,1307.32 2181.2,1307.32
  Signal Layer 4 w6.25: 2181.21,1307.31 2209.88,1307.31 2244.88,1272.31 2397.39,1272.31 2440.52,1315.44 2457.59,1315.44 2516.09,1373.94 2581.79,1373.94 2610.54,1402.69 2739.79,1402.69 2811.54,1330.94 2938.79,1330.94 2943.79,1335.94 2972.46,1335.94 3046.08,1409.55 3046.08,1410.82 3083.21,1447.94 3083.21,1499.83 3286.69,1703.31 v1(3486.21,1703.31)
  Signal Layer 7 w6.25: v1(3464.34,300) 3485.33,320.99 3485.33,365.37 3457.38,393.32 3457.38,685.66 3450.33,692.71 3450.33,717.29 3457.38,724.34 3457.38,1172.88 3487.83,1203.33 3487.83,1354.26 3505.13,1371.56 3505.13,1684.38 v1(3486.21,1703.31)
MCU_GPIO77: EC2.144 U1.A15 | length 3098.1
  Top Layer w6.25: U1.A15@2018.9,1339.56 v2(2034.65,1355.31)
  Signal Layer 3 w6.25: v2(2034.65,1355.31) 2034.65,1400.71 2054.63,1420.69 2199.8,1420.69 2246.86,1373.63 2392.03,1373.63 2413.59,1395.19 2517.42,1395.19 2544.67,1422.44 2614.15,1422.44 2621.65,1414.94 2734.25,1414.94 2783.88,1365.31 2846.56,1365.31 2894.06,1317.81 3159.34,1317.81 3286.9,1445.38 3326.25,1445.38 3326.44,1445.19 3484.33,1445.19 v1(3540.21,1389.31)
  Signal Layer 7 w6.25: v1(3508.21,336.31) 3508.21,359.99 3468.93,399.27 3468.93,690.44 3461.88,697.49 3461.88,712.51 3469.63,720.26 3469.63,1073.99 3500.08,1104.44 3500.08,1349.19 v1(3540.21,1389.31)
  Bottom w6.25: EC2.144@3489.89,91 3489.89,317.56 3508.21,335.88 v1(3508.21,336.31)
MCU_GPIO78: EC2.145 U1.B15 | length 3110.9
  Top Layer w6.25: U1.B15@2018.9,1308.07 v2(2034.65,1323.82) ; EC2.145@3521.38,91 3521.38,212.49 3514.21,219.67 3514.21,246.88 v1(3532.33,265)
  Signal Layer 3 w4: v2(2034.65,1323.82) 2050.21,1339.38 2050.21,1368.31
  Signal Layer 3 w6.25: 2050.21,1368.31 2050.21,1379.79 2048,1382 2048,1396.74 2059.7,1408.44 2194.72,1408.44 2241.78,1361.38 2397.1,1361.38 2415.42,1379.69 2519.24,1379.69 2525.74,1386.19 2576.71,1386.19 2593.21,1402.69 2729.18,1402.69 2778.8,1353.06 2827.41,1353.06 2874.91,1305.56 2953.91,1305.56 2984.29,1275.19 3134.04,1275.19 3291.98,1433.13 3321.18,1433.13 3321.36,1432.94 3474.21,1432.94 3506.2,1400.95 3506.2,1369.32 v1(3541.21,1334.31)
  Signal Layer 7 w6.25: v1(3532.33,265) 3532.33,267.57 3545.46,280.69 3545.46,313.33 3540.83,317.95 3540.83,563.22 3555.58,577.97 3555.58,659.16 3548.58,666.16 3548.58,787.94 3553.13,792.49 3553.13,914.18 3527.38,939.93 3527.38,1127.66 3550.38,1150.66 3550.38,1294.09 3541.21,1303.27 v1(3541.21,1334.31)
MCU_GPIO79: EC2.146 U1.C15 | length 3588.1
  Top Layer w6.25: U1.C15@2018.9,1276.57 v2(2034.65,1292.32)
  Signal Layer 4 w4: v2(2034.65,1292.32) 2049.65,1307.32 2049.65,1328.53 2060.43,1339.31 2173.21,1339.31
  Signal Layer 4 w6.25: 2173.21,1339.31 2195.21,1339.31 2249.96,1284.56 2354.94,1284.56 2423.5,1353.13 2477.95,1353.13 2511.01,1386.19 2576.71,1386.19 2605.46,1414.94 2744.86,1414.94 2816.61,1343.19 2933.71,1343.19 2954.08,1363.55 2954.08,1368.82 3070.96,1485.69 3070.96,1504.9 3281.61,1715.56 3296.4,1715.56 3312.15,1731.31 v1(3530.21,1731.31)
  Signal Layer 7 w6.25: v1(3530.21,1731.31) 3530.21,1457.25 3558.33,1429.13 3558.33,1381.8 3523.08,1346.55 3523.08,1304.07 3538.13,1289.02 3538.13,1155.73 3515.13,1132.73 3515.13,1102.17 3481.88,1068.92 3481.88,827.49 3519.33,790.05 3519.33,678.08 3543.33,654.08 3543.33,583.04 3528.58,568.29 3528.58,331.05 3509.21,311.68 3509.21,253.13 v1(3532.33,230)
  Bottom w6.25: EC2.146@3521.38,91 3521.38,214.05 3537.33,230 v1(3532.33,230)
MCU_GPIO80: EC2.147 U1.D15 | length 2863.7
  Top Layer w6.25: U1.D15@2018.9,1245.08 v2(2034.65,1260.82) ; v1(3527.33,300) 3552.88,274.45 EC2.147@3552.88,91
  Signal Layer 4 w4: v2(2034.65,1260.82) 2049.65,1245.82 2049.65,1224.61 2060.68,1213.58 2170.94,1213.58
  Signal Layer 4 w6.25: 2170.94,1213.58 2302.55,1213.58 2318.09,1229.13 2406.18,1229.13 2455.74,1278.69 2472.81,1278.69 2524.81,1330.69 2571.2,1330.69 2599.95,1301.94 2928.88,1301.94 2930.63,1303.69 2946.19,1303.69 2953.94,1311.44 3170.29,1311.44 3197.29,1338.44 3361.71,1338.44 3416.84,1283.31 v1(3518.21,1283.31)
  Signal Layer 8 w6.25: v1(3518.21,1283.31) 3501.88,1266.99 3501.88,1088.87 3518.13,1072.62 3518.13,898.76 3506.88,887.51 3506.88,605 3527.33,584.55 v1@3527.33,302
MCU_GPIO81: EC2.148 U1.A14 | length 3403.8
  Top Layer w6.25: U1.A14@1987.4,1339.56 v2(2003.15,1355.31)
  Signal Layer 3 w6.25: v2(2003.15,1355.31) 2003.15,1403.86 2069.98,1470.69 2416.2,1470.69 2443.2,1443.69 2480.41,1443.69 2480.91,1443.19 2524.23,1443.19 2554.48,1473.44 2597.8,1473.44 2624.55,1446.69 2659.86,1446.69 2660.11,1446.94 2755.26,1446.94 2782.26,1419.94 2830.54,1419.94 2855.88,1394.59 2855.88,1390.87 2903.56,1343.19 3115.08,1343.19 3241.77,1469.88 3480.52,1469.88 3525.86,1515.21 3525.86,1536.59 v1(3574.21,1584.94)
  Signal Layer 7 w6.25: v1(3571.21,336.31) 3571.21,558.94 3580.08,567.82 3580.08,669.31 3573.08,676.31 3573.08,777.79 3577.63,782.34 3577.63,924.32 3551.88,950.07 3551.88,1117.51 3574.88,1140.51 3574.88,1304.24 3571.83,1307.29 3571.83,1360.66 3582.83,1371.66 3582.83,1469.29 3572.08,1480.04 3572.08,1582.82 v1(3574.21,1584.94)
  Bottom w6.25: EC2.148@3552.88,91 3552.88,317.56 3571.21,335.88 v1(3571.21,336.31)
MCU_GPIO82: EC2.149 U1.B14 | length 3333.9
  Top Layer w6.25: U1.B14@1987.4,1308.07 v2(2003.15,1323.82) ; EC2.149@3584.37,91 3584.37,212.49 3577.2,219.67 3577.2,246.88 v1(3595.32,265)
  Signal Layer 3 w4: v2(2003.15,1323.82) 2018.9,1339.56 2018.9,1371.06
  Signal Layer 3 w6.25: 2018.9,1371.06 2018.9,1402.29 2075.05,1458.44 2179.37,1458.44 2251.93,1385.88 2338.36,1385.88 2383.92,1431.44 2463.31,1431.44 2463.81,1430.94 2535.85,1430.94 2539.6,1434.69 2619.23,1434.69 2619.48,1434.44 2732.08,1434.44 2758.83,1407.69 2825.46,1407.69 2843.63,1389.52 2843.63,1385.79 2898.49,1330.94 3121.2,1330.94 3247.89,1457.63 3489.52,1457.63 v1(3549.21,1517.31)
  Signal Layer 7 w6.25: v1(3549.21,1517.31) 3549.21,1455.58 3570.58,1434.2 3570.58,1376.73 3559.58,1365.73 3559.58,1302.22 3562.63,1299.17 3562.63,1145.58 3539.63,1122.58 3539.63,945 3565.38,919.25 3565.38,787.42 3560.83,782.87 3560.83,671.23 3567.83,664.23 3567.83,572.89 3553.08,558.14 3553.08,327.66 3557.71,323.04 3557.71,302.62 v1(3595.32,265)
MCU_GPIO83: EC2.150 U1.C14 | length 3639.2
  Top Layer w6.25: U1.C14@1987.4,1276.57 v2(2003.15,1292.32)
  Signal Layer 4 w4: v2(2003.15,1292.32) 2018.9,1308.07 2018.9,1365
  Signal Layer 4 w6.25: 2018.9,1365 2018.9,1385.9 2024,1391 2039,1391 2058.56,1371.44 2180.41,1371.44 2255.03,1296.81 2349.86,1296.81 2418.43,1365.38 2472.88,1365.38 2529.94,1422.44 2592.66,1422.44 2597.41,1427.19 2749.94,1427.19 2809.94,1367.19 2900.46,1367.19 2912.71,1379.44 2936.96,1379.44 3058.71,1501.18 3058.71,1529.14 3292.76,1763.19 3471.08,1763.19 v1(3473.21,1765.31)
  Signal Layer 8 w6.25: v1(3473.21,1765.31) 3473.21,1715.94 3468.08,1710.82 3468.08,1492.55 3454.08,1478.55 3454.08,1396.07 3467.33,1382.82 3467.33,1359.82 3538.13,1289.02 3538.13,1177.49 3527.38,1166.74 3527.38,1080.69 3530.38,1077.69 3530.38,900.26 3553.13,877.51 3553.13,577.03 3553.08,576.98 3553.08,272.24 v1(3595.32,230)
  Bottom w6.25: EC2.150@3584.37,91 3584.37,214.05 3600.32,230 v1(3595.32,230)
MCU_GPIO84: EC2.151 R32.1 S2.1 U1.A11 | length 5601.5
  Top Layer w6.25: v1(1258.01,1839) 1258.01,1834.74 1261.48,1831.27 1261.48,1798.65 1273.32,1786.81 1293.4,1786.81 1446.66,1633.54 1650.96,1633.54 1778.69,1505.82 1778.69,1485.29 v2(1908.66,1355.31) U1.A11@1892.92,1339.56 ; v1(3590.32,300) 3615.87,274.45 EC2.151@3615.87,91
  Signal Layer 8 w6.25: v2(1908.66,1355.31) 1885.26,1378.71 1885.26,1467.73 1890.33,1472.8 1890.33,1597.7 1876.88,1611.15 1876.88,1728.46 1878.13,1729.71 1878.13,1847.01 1779.71,1945.44 1758.45,1945.44 1744.08,1959.8 1744.08,1997.03 1812.93,2065.88 1970,2065.88 2198.5,2065.88 2208.5,2055.88 2223.52,2055.88 2241.77,2074.13 2289.52,2074.13 2382.08,1981.56 2382.08,1876.56 2416.13,1842.51 2416.13,1812.24 2498.94,1729.44 2548.45,1729.44 2587.61,1690.27 2713.24,1690.27 2802.14,1601.38 3311.67,1601.38 3395.86,1685.57 3395.86,1713.6 3465.7,1783.44 3480.71,1783.44 3491.33,1772.82 3491.33,1723.82 3505.13,1710.02 3505.13,1494.49 3502.63,1491.99 3502.63,1341.84 3550.38,1294.09 3550.38,1172.42 3539.63,1161.67 3539.63,1085.77 3542.63,1082.77 3542.63,905.33 3573.08,874.88 3573.08,549.8 3590.32,532.56 v1(3590.32,300)
  Bottom w6.25: v1(1258.01,1839) 1258.01,1834.74 1263.76,1828.98 1263.76,1793.69 1272.45,1785 R32.1@1276.39,1785
MCU_GPIO85: EC2.152 U1.B11 | length 3568.7
  Top Layer w6.25: U1.B11@1892.92,1308.07 v2(1908.66,1323.82)
  Signal Layer 3 w4: v2(1908.66,1323.82) 1924.41,1339.56 1924.41,1372.11
  Signal Layer 3 w6.25: 1924.41,1372.11 1924.41,1385.41 1940.96,1401.96 1940.96,1434 1984.33,1477.37 1984.33,1522.72 2029.55,1567.94 2166.1,1567.94 2195.85,1538.19 2385.71,1538.19 2391.96,1544.44 2440.98,1544.44 2478.05,1581.51 2622.88,1581.51 2654.78,1549.6 2748.22,1549.6 2801.55,1602.94 3018.4,1602.94 3080.15,1541.19 3303.71,1541.19 3308.96,1546.44 3468.3,1546.44 3524.94,1603.07 3590.45,1603.07 v1(3612.21,1581.31)
  Signal Layer 7 w6.25: v1(3612.21,1581.31) 3612.21,1532.8 3602.13,1522.73 3602.13,1373.63 3584.08,1355.58 3584.08,1312.37 3587.13,1309.31 3587.13,1141.38 3623.13,1105.38 3623.13,1003.92 3650.43,976.62 3650.43,927.11 3634.63,911.32 3634.63,336.32 v1(3618.32,320)
  Bottom w6.25: EC2.152@3615.87,91 3615.87,317.56 v1(3618.32,320)
MCU_GPIO86: EC2.153 U1.C11 | length 3732.9
  Top Layer w6.25: U1.C11@1892.92,1276.57 v2(1908.66,1292.32) ; EC2.153@3647.37,91 3647.37,212.49 3640.19,219.67 3640.19,246.88 v1(3658.32,265)
  Signal Layer 3 w4: 1892.21,1366.31 1892.21,1308.78 v2(1908.66,1292.32)
  Signal Layer 3 w6.25: 1892.21,1366.31 1892.21,1374.79 1885.26,1381.74 1885.26,1407.11 1972.08,1493.93 1972.08,1527.79 2024.48,1580.19 2172.15,1580.19 2200.46,1551.88 2348.14,1551.88 2370.7,1574.44 2453.66,1574.44 2497.66,1618.44 2603.27,1618.44 2659.85,1561.85 2743.14,1561.85 2796.48,1615.19 3109.64,1615.19 3137.27,1587.56 3492.11,1587.56 3542.86,1638.31 v1(3612.21,1638.31)
  Signal Layer 7 w6.25: v1(3612.21,1638.31) 3642.58,1607.94 3642.58,1528.53 3626.63,1512.58 3626.63,1363.84 3642.83,1347.64 3642.83,1220.78 3683.13,1180.48 3683.13,925.17 3672.55,914.58 3672.55,888.1 3683.13,877.51 3683.13,862.49 3662.08,841.44 3662.08,440.8 3699.43,403.45 3699.43,308.76 3658.32,267.64 v1(3658.32,265)
MCU_GPIO87: EC2.154 U1.D11 | length 2805.2
  Top Layer w6.25: U1.D11@1892.92,1245.08 v2(1908.66,1260.82)
  Signal Layer 4 w4: v2(1908.66,1260.82) 1925.16,1244.33 1925.16,1191.62 1996.94,1119.84 2166.68,1119.84
  Signal Layer 4 w6.25: 2166.68,1119.84 2184.84,1119.84 2192,1127 2255.15,1127 2265.28,1116.88 2315.14,1116.88 2341.39,1143.13 2434.77,1143.13 2485.95,1194.31 2535.33,1194.31 2565.21,1164.44 2720.08,1164.44 2811.21,1073.31 2840.27,1073.31 2912.21,1001.38 2997.47,1001.38 3161.66,837.19 3378.81,837.19 3579.7,636.3 v1(3727.3,636.3)
  Signal Layer 8 w6.25: v1(3658.32,230) 3635.19,253.13 3635.19,311.24 3641.96,318.01 3641.96,530.06 3727.3,615.4 v1(3727.3,636.3)
  Bottom w6.25: EC2.154@3647.37,91 3647.37,214.05 3663.32,230 v1(3658.32,230)
MCU_GPIO88: EC2.155 U1.C6 | length 4893.4
  Top Layer w6.25: v2(1719.69,1292.32) U1.C6@1735.44,1276.57 ; v1(3653.32,300) 3678.86,274.45 EC2.155@3678.86,91
  Signal Layer 8 w4: v2(1719.69,1292.32) 1735.21,1307.84 1735.21,1369.31
  Signal Layer 8 w6.25: 1735.21,1369.31 1735.21,1398.23 1733.44,1400 1733.44,1543.57 1736.13,1546.27 1736.13,1718.75 1715.88,1739 1715.88,1894.51 1731.83,1910.46 1731.83,2039.46 1781.31,2088.94 1950.46,2088.94 2008.65,2147.13 2333.03,2147.13 2396.88,2083.27 2396.88,2039.49 2418.33,2018.05 2418.33,1864.05 2517.94,1764.44 2564.71,1764.44 2601.21,1727.94 2692.91,1727.94 2807.22,1613.63 3306.59,1613.63 3383.61,1690.64 3383.61,1718.67 3460.63,1795.69 3485.79,1795.69 3503.58,1777.89 3503.58,1732.3 3517.38,1718.5 3517.38,1489.42 3514.88,1486.92 3514.88,1386.27 3559.33,1341.82 3559.33,1327.91 3562.63,1324.6 3562.63,1167.34 3551.88,1156.59 3551.88,1090.84 3554.88,1087.84 3554.88,932.31 3747.33,739.86 3747.33,569.07 3654.21,475.95 3654.21,300.89 v1(3653.32,300)
MCU_GPIO89: EC2.156 U1.D6 | length 4164.3
  Top Layer w6.25: v2(1719.69,1260.82) U1.D6@1735.44,1245.08
  Signal Layer 3 w4: v2(1719.69,1260.82) 1735.21,1276.34 1735.21,1371.31
  Signal Layer 3 w6.25: 1735.21,1371.31 1735.21,1378.21 1746,1389 1781,1389 1843,1451 1843,1479.1 1862.33,1498.44 1910.96,1498.44 1935.33,1522.8 1935.33,1585.96 2028.81,1679.44 2119.71,1679.44 2163.91,1635.25 2243.04,1635.25 2286.49,1678.69 2315.33,1678.69 2330.08,1693.44 2378.71,1693.44 2390.28,1681.88 2428.52,1681.88 2607.33,1860.69 2607.33,1869.74 2635.42,1897.83 2656.65,1897.83 2666.04,1888.44 2764.71,1888.44 2807.58,1845.57 2807.58,1795.66 2907.8,1695.44 3046.71,1695.44 3140.78,1601.38 3461.88,1601.38 3542.81,1682.31 v1(3592.21,1682.31)
  Signal Layer 7 w6.25: v1(3592.21,1682.31) 3592.21,1632.68 3630.33,1594.55 3630.33,1533.6 3614.38,1517.66 3614.38,1358.77 3630.58,1342.57 3630.58,1115.26 3646.88,1098.96 3646.88,997.49 3662.68,981.7 3662.68,922.04 3646.88,906.24 3646.88,354.42 v1(3681.31,320)
  Bottom w6.25: EC2.156@3678.86,91 3678.86,317.56 v1(3681.31,320)
MCU_GPIO90: EC2.159 U1.A5 | length 4142.2
  Top Layer w6.25: v2(1688.19,1355.31) U1.A5@1703.94,1339.56 ; v1(3716.31,300) 3741.85,274.45 EC2.159@3741.85,91
  Signal Layer 3 w6.25: v2(1688.19,1355.31) 1688.19,1385.53 1718.22,1415.55 1725.59,1415.55 2013.97,1703.94 2271.99,1703.94 2298.43,1730.38 2370.99,1730.38 2453.88,1813.27 2453.88,1823.49 2510.58,1880.19 2553.02,1880.19 2595.15,1922.33 2666.8,1922.33 2676.18,1912.94 2774.86,1912.94 2832.08,1855.72 2832.08,1805.8 2917.95,1719.94 3137.81,1719.94 3231.87,1625.88 3451.73,1625.88 3552.41,1726.56 3566.46,1726.56 v1(3592.21,1752.31)
  Signal Layer 7 w6.25: v1(3592.21,1752.31) 3592.21,1707.94 3654.83,1645.32 3654.83,1523.46 3638.88,1507.51 3638.88,1368.92 3655.08,1352.72 3655.08,1225.85 3695.38,1185.55 3695.38,920.1 3684.8,909.51 3684.8,893.17 3695.38,882.58 3695.38,857.42 3686.58,848.62 3686.58,653.88 3686.08,653.38 3686.08,619.22 3686.58,618.72 3686.58,591.3 3716.31,561.58 v1(3716.31,300)
MCU_GPIO91: EC2.160 U1.B5 | length 4137.1
  Top Layer w6.25: v2(1688.19,1323.82) U1.B5@1703.94,1308.07
  Signal Layer 3 w4: v2(1688.19,1323.82) 1703.94,1339.56 1703.94,1376.58
  Signal Layer 3 w6.25: 1703.94,1376.58 1703.94,1384.94 1723,1404 1761,1404 1828,1471 1828,1495 2024.69,1691.69 2277.06,1691.69 2303.5,1718.13 2433.77,1718.13 2490.13,1774.49 2490.13,1802.87 2544.29,1857.03 2547.18,1857.03 2600.23,1910.08 2661.72,1910.08 2671.11,1900.69 2769.79,1900.69 2819.83,1850.64 2819.83,1800.73 2912.88,1707.69 3051.79,1707.69 3145.85,1613.63 3456.8,1613.63 3557.49,1714.31 v1(3613.21,1714.31)
  Signal Layer 7 w6.25: v1(3613.21,1714.31) 3677.13,1650.38 3677.13,1450.83 3721.05,1406.92 3721.05,865.76 3698.83,843.54 3698.83,649.8 3697.62,648.59 3697.62,624.01 3698.83,622.8 3698.83,604.73 3740.21,563.36 v1(3740.21,342.31)
  Bottom w6.25: v1(3740.21,342.31) 3741.85,340.66 EC2.160@3741.85,91
MCU_GPIO92: EC2.161 U1.A4 | length 4236.4
  Top Layer w6.25: v2(1656.7,1355.31) U1.A4@1672.44,1339.56 ; EC2.161@3773.35,91 3773.35,212.49 3766.17,219.67 3766.17,246.88 v1(3784.3,265)
  Signal Layer 3 w6.25: v2(1656.7,1355.31) 1656.7,1414.8 1727.58,1485.69 1727.58,1508.96 1781.92,1563.31 1801.27,1563.31 1869.97,1632 1869.97,1635.59 1921.19,1686.81 1962.2,1686.81 2007.88,1732.5 2265.9,1732.5 2288.28,1754.88 2360.84,1754.88 2429.38,1823.42 2429.38,1834.45 2524.13,1929.19 2561.71,1929.19 2579.35,1946.83 2676.94,1946.83 2686.33,1937.44 2790.76,1937.44 2872.63,1855.56 3043.4,1855.56 3193.44,1705.53 3456.38,1705.53 3548.16,1797.31 v1(3624.21,1797.31)
  Signal Layer 7 w6.25: v1(3624.21,1797.31) 3723.88,1697.63 3723.88,1438.73 3746.83,1415.78 3746.83,635.41 3789.58,592.66 3789.58,348.73 3761.17,320.32 3761.17,288.13 v1(3784.3,265)
MCU_GPIO93: EC2.162 U1.B4 | length 4248.2
  Top Layer w6.25: v2(1656.7,1323.82) U1.B4@1672.44,1308.07
  Signal Layer 3 w4: v2(1656.7,1323.82) 1672.44,1339.56 1672.44,1371.08
  Signal Layer 3 w6.25: 1672.44,1371.08 1672.44,1386.11 1713.43,1427.1 1719.81,1427.1 2008.9,1716.19 2266.92,1716.19 2293.35,1742.63 2365.92,1742.63 2441.63,1818.34 2441.63,1829.37 2528.7,1916.44 2566.29,1916.44 2584.43,1934.58 2671.87,1934.58 2681.26,1925.19 2779.94,1925.19 2861.81,1843.31 3038.33,1843.31 3214.77,1666.88 3475.4,1666.88 3509.55,1701.02 3509.55,1736.29 3543.7,1770.44 3618.08,1770.44 v1(3644.21,1744.31)
  Signal Layer 7 w6.25: v1(3644.21,1744.31) 3711.63,1676.88 3711.63,1433.66 3733.3,1411.99 3733.3,860.68 3711.08,838.47 3711.08,645.71 3709.17,643.81 3709.17,628.79 3711.08,626.89 3711.08,609.8 3777.33,543.55 3777.33,353.8 3748.92,325.4 3748.92,265.38 v1(3784.3,230)
  Bottom w6.25: EC2.162@3773.35,91 3773.35,214.05 3789.3,230 v1(3784.3,230)
MCU_GPIO94: EC2.163 U1.A3 | length 4601
  Top Layer w6.25: v2(1625.2,1355.31) U1.A3@1640.95,1339.56 ; v1(3779.3,300) 3804.85,274.45 EC2.163@3804.85,91
  Signal Layer 3 w6.25: v2(1625.2,1355.31) 1625.2,1411.2 1631,1417 1631,1479.74 1862.57,1711.31 1913.7,1711.31 1979.58,1777.19 2025.71,1777.19 2029.52,1781 2144.52,1781 2154.64,1770.88 2269.63,1770.88 2292.63,1793.88 2353.52,1793.88 2379.88,1820.24 2379.88,1854.51 2440.5,1915.13 2453.77,1915.13 2488.17,1949.53 2488.17,2089.24 2524.63,2125.69 2549.79,2125.69 2577.08,2098.39 2577.08,2046.69 2635.74,1988.03 2809.58,1988.03 2816.67,1995.13 2990.52,1995.13 3019.88,1965.76 3019.88,1961.49 3218.19,1763.19 3374.01,1763.19 3463.13,1852.31 v1(3623.21,1852.31)
  Signal Layer 7 w6.25: v1(3623.21,1852.31) 3745.71,1729.81 3745.71,1514.92 3760.13,1500.5 3760.13,1289.87 3759.08,1288.82 3759.08,640.48 3801.83,597.73 3801.83,343.66 3779.3,321.12 v1(3779.3,300)
MCU_GPIO95: EC2.168 U1.B3 | length 4675.8
  Top Layer w6.25: v2(1625.2,1323.82) U1.B3@1640.95,1308.07
  Signal Layer 3 w4: v2(1625.2,1323.82) 1640.21,1338.82 1640.21,1366.31
  Signal Layer 3 w6.25: 1640.21,1366.31 1640.21,1409.87 1642.55,1412.22 1642.55,1417.98 1715.33,1490.76 1715.33,1514.04 1776.85,1575.56 1796.2,1575.56 1856.16,1635.51 1856.16,1639.1 1916.11,1699.06 1918.78,1699.06 1964.47,1744.75 2010.6,1744.75 2034.6,1768.75 2139.44,1768.75 2149.57,1758.63 2274.71,1758.63 2283.21,1767.13 2355.77,1767.13 2417.13,1828.49 2417.13,1839.52 2500.42,1922.81 2500.42,2084.16 2529.7,2113.44 2544.71,2113.44 2564.83,2093.32 2564.83,2041.61 2631.72,1974.72 2770.8,1974.72 2821.64,1923.88 2992.42,1923.88 3198.51,1717.78 3451.31,1717.78 3548.96,1815.44 3750.08,1815.44 v1(3770.21,1795.31)
  Signal Layer 7 w6.25: v1(3770.21,1795.31) 3770.21,1629.17 3862.63,1536.74 3862.63,736.12 3896.33,702.42 3896.33,346.05 v1(3870.28,320)
  Bottom w6.25: EC2.168@3867.84,91 3867.84,317.56 v1(3870.28,320)
MCU_GPIO96: EC1.93 U1.C3 | length 2119.5
  Top Layer w6.25: v2(1625.2,1292.32) U1.C3@1640.95,1276.57 ; EC1.93@1904.53,91 1904.53,274.45 1920.39,290.31 v1(1924.21,290.31)
  Signal Layer 3 w4: 1544.21,1307.32 1610.2,1307.32 v2(1625.2,1292.32)
  Signal Layer 3 w6.25: v1(1514.21,1377.31) 1514.21,1320.79 1527.68,1307.32 1544.21,1307.32
  Signal Layer 8 w6.25: v1(1514.21,1377.31) 1514.21,1228.57 1499.63,1213.99 1499.63,1137.42 1525.38,1111.67 1525.38,1057.42 1520.99,1053.02 1520.99,888.53 1499.08,866.63 1499.08,738.8 1511.82,726.06 1629.73,726.06 1751.63,604.15 1751.63,552.7 1704.83,505.89 1704.83,309.54 1676.88,281.59 1676.88,222.49 1699.75,199.63 1879.24,199.63 1902.11,222.49 1902.11,268.22 v1(1924.21,290.31)
MCU_GPIO97: EC1.94 U1.A2 | length 1904.7
  Top Layer w6.25: v2(1593.7,1355.31) U1.A2@1609.45,1339.56
  Signal Layer 8 w6.25: v2(1593.7,1355.31) 1577.58,1371.44 1555.53,1371.44 1526.46,1342.37 1526.46,1223.49 1511.88,1208.92 1511.88,1142.49 1537.63,1116.74 1537.63,1052.34 1533.24,1047.95 1533.24,1032.84 1544.98,1021.1 1544.98,751.31 1556.73,739.56 1687.58,739.56 1765.96,661.18 1765.96,549.69 1728.08,511.82 1728.08,439.8 1717.08,428.8 1717.08,245.29 1750.49,211.88 1828.5,211.88 1853.32,236.69 1853.32,291.12 v1@1878.13,315.94
  Bottom w6.25: v1(1884.21,320.31) 1902.11,302.41 1902.11,93.42 EC1.94@1904.53,91
MCU_GPIO98: EC1.95 U1.F1 | length 1909.8
  Top Layer w6.25: v1(1458.39,1228.64) 1458.39,1227.13 1487.69,1197.83 v2(1562.21,1197.83) U1.F1@1577.96,1182.08 ; EC1.95@1936.03,91 1936.03,212.49 1928.85,219.66 1928.85,246.88 v1(1946.98,265)
  Signal Layer 8 w6.25: v1(1458.39,1228.64) 1487.38,1199.65 1487.38,1132.34 1513.13,1106.59 1513.13,1062.49 1508.74,1058.09 1508.74,893.6 1486.83,871.7 1486.83,733.73 1506.75,713.81 1624.65,713.81 1739.38,599.08 1739.38,557.77 1691.06,509.44 1691.06,313.09 1664.63,286.67 1664.63,217.42 1695.24,186.81 1883.75,186.81 1914.36,217.42 1914.36,232.38 v1(1946.98,265)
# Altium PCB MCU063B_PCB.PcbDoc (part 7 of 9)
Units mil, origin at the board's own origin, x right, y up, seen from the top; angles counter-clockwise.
Board outline 4165.01 x 2371.03 mil, 10 copper layers (Top Layer, Internal Plane 2, Signal Layer 3, Signal Layer 4, Internal Plane 5, Internal Plane 6, Signal Layer 7, Signal Layer 8, Internal Plane 9, Bottom), stack 59.9 mil thick; 440 components, 394 nets, 1760 pads, 1251 vias.

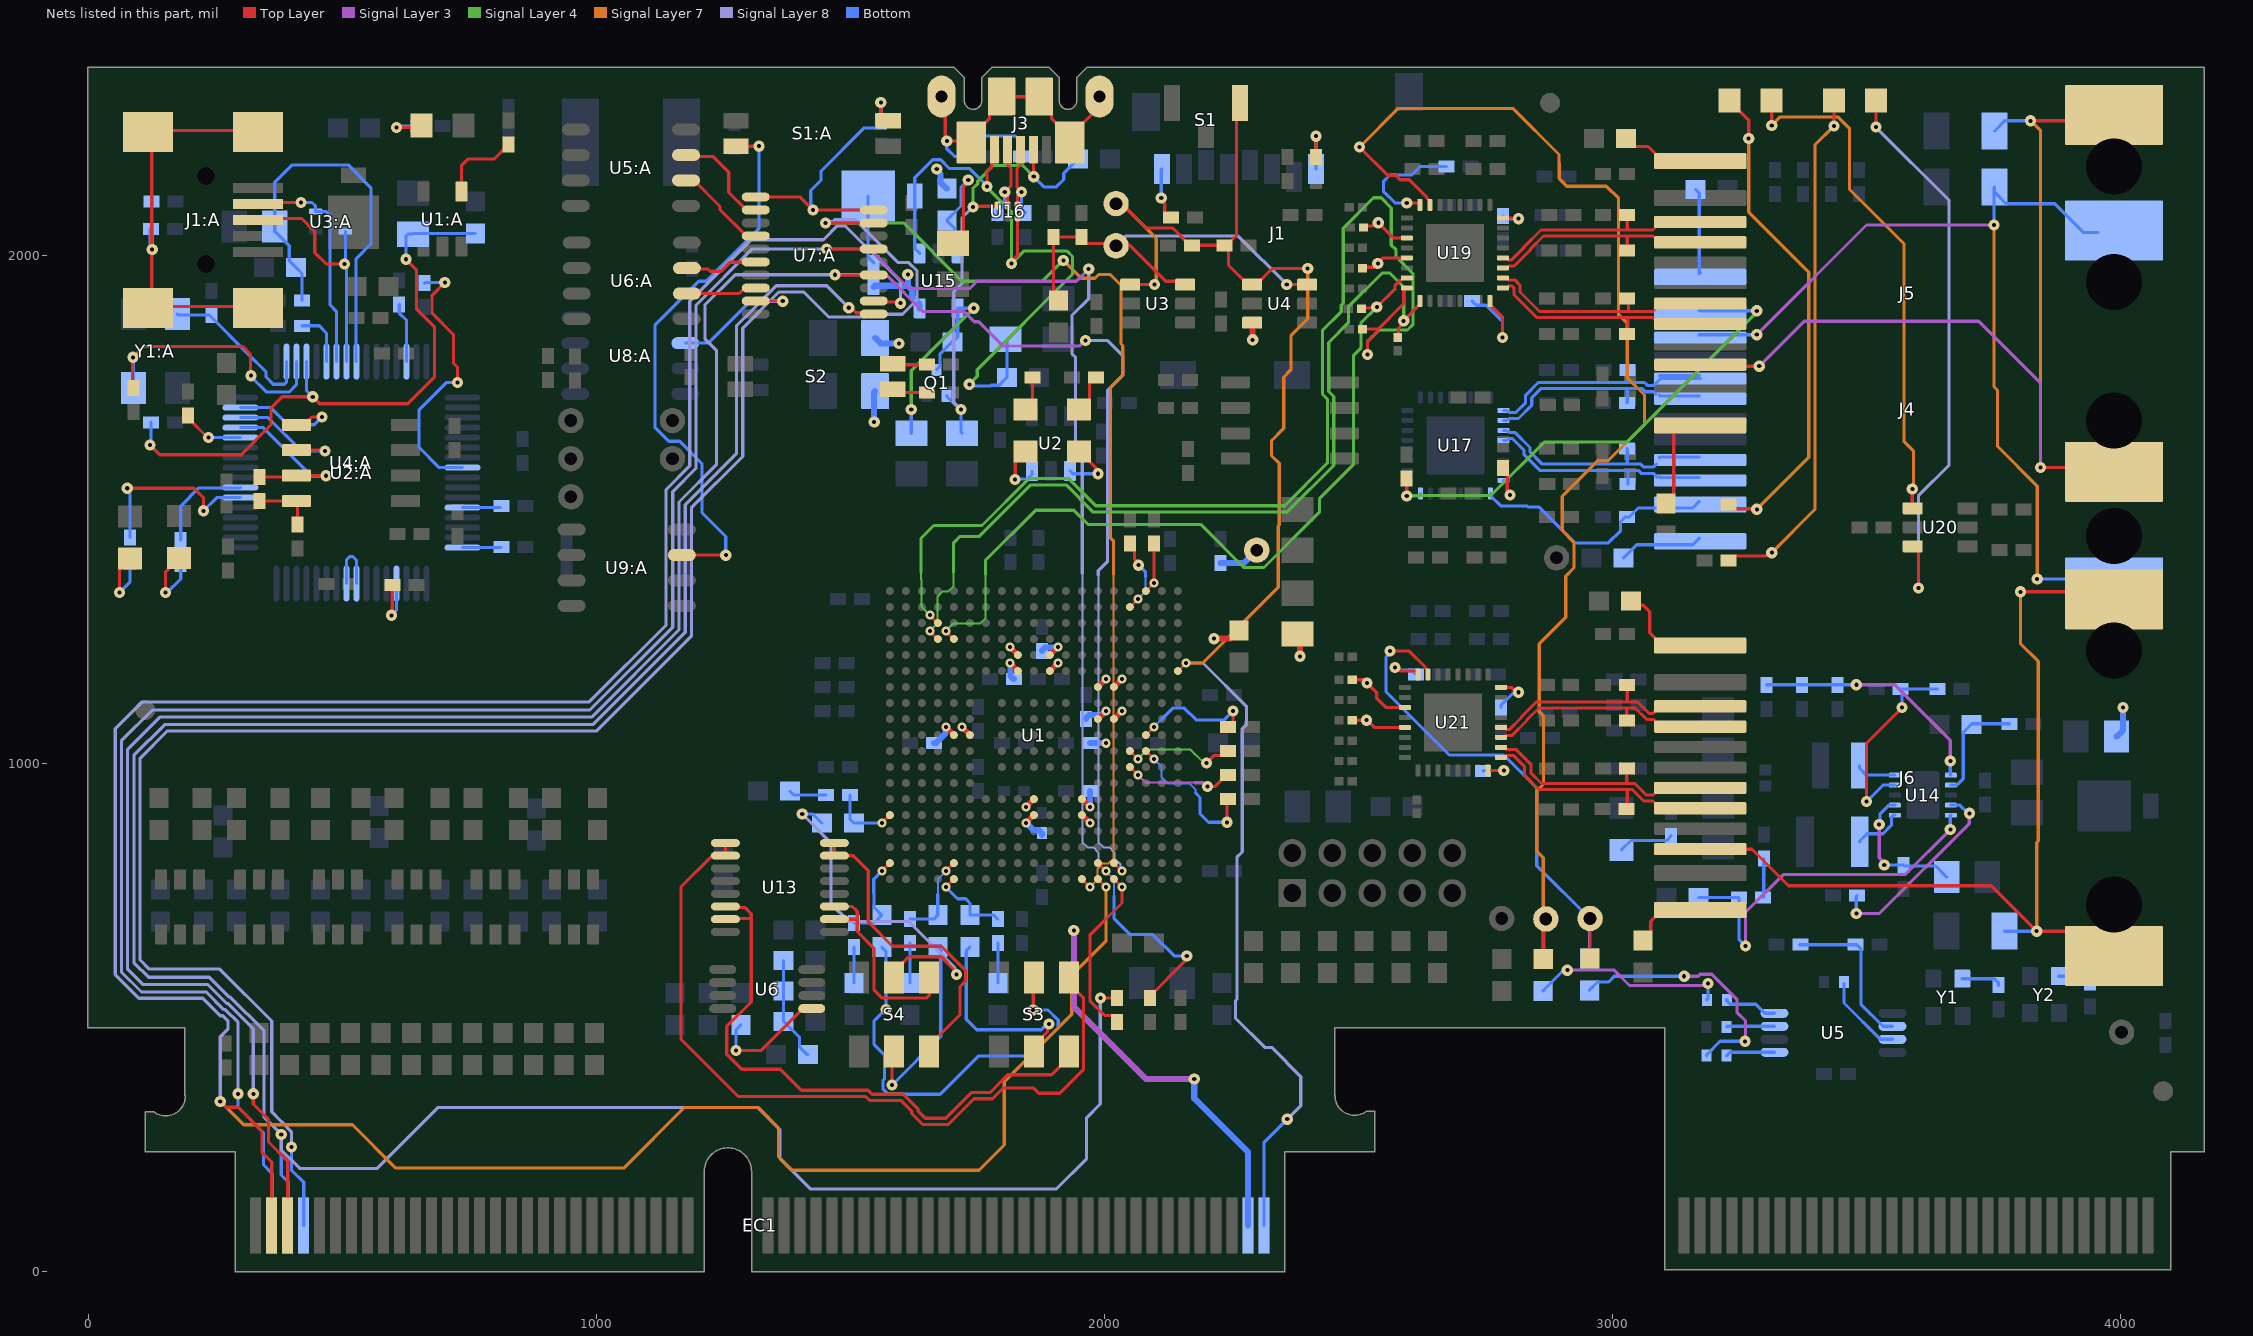
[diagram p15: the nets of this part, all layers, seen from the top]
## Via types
v1: diameter 22, hole 8, Top Layer to Bottom, tented both sides, 895 vias
v2: diameter 18, hole 8, Top Layer to Bottom, tented both sides, 334 vias
v3: diameter 19.68, hole 7.87, Top Layer to Bottom, tented both sides, 19 vias
v4: diameter 18, hole 7.87, Top Layer to Bottom, tented both sides, 1 vias
v5: diameter 18/18/18/18/18/18 (per signal layer), hole 8, Top Layer to Bottom, tented both sides, 1 vias
v6: diameter 22/22/22/22/22/22 (per signal layer), hole 8, Top Layer to Bottom, tented both sides, 1 vias

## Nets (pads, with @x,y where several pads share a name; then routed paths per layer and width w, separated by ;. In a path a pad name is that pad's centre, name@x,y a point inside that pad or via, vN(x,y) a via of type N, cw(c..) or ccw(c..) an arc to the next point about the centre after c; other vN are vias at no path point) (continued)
MCU_GPIO166: R133.2 U1.D5 U19.31 | length 1583.4
  Top Layer w6.25: v2(1688.19,1260.82) U1.D5@1703.94,1245.08 ; R133.2@2505.99,1895 2507.65,1896.66 2534.55,1896.66 2572.33,1934.44 2572.33,1941.4 2581.08,1950.15 2582.99,1950.15 2588.63,1955.79 U19.31@2595.52,1955.79
  Signal Layer 4 w4: v2(1688.19,1260.82) 1703.19,1275.82 1755.9,1275.82 1766.18,1286.11 1766.18,1372.29
  Signal Layer 4 w6.25: 1766.18,1372.29 1766.18,1399.92 1864.7,1498.44 1940.07,1498.44 1968.07,1470.44 2149.38,1470.44 2149.63,1470.69 2189.48,1470.69 2274.29,1385.88 2314.14,1385.88 2423.67,1495.4 2423.67,1521.73 2490.13,1588.2 2490.13,1802.87 2504.88,1817.62 2504.88,1866.99 v1(2536.21,1898.31)
MCU_GPIO167: R134.2 U1.C4 U19.32 | length 2267.3
  Top Layer w6.25: v2(1656.7,1292.32) U1.C4@1672.44,1276.57 ; R134.2@2508,1855 2536.9,1855 ; v1(2518.21,1805.31) 2518.21,1830.94 2537.9,1850.63 2537.9,1854 2588.8,1904.91 2588.8,1934.31 2590.6,1936.1 U19.32@2595.52,1936.1
  Signal Layer 4 w4: 1639.21,1376.31 1639.21,1362.52 1640.2,1361.53 1640.2,1308.82 v2(1656.7,1292.32)
  Signal Layer 4 w6.25: 1639.21,1376.31 1639.21,1443.21 1664.5,1468.5 1759.14,1468.5 1851.33,1560.69 1929.79,1560.69 1983.29,1507.19 2134.15,1507.19 2134.4,1507.44 2354.96,1507.44 2439.13,1591.61 2439.13,1717.3 2429.38,1727.05 2429.38,1852.74 2466.13,1889.49 2466.13,1902.2 2470.13,1906.2 2470.13,2053.87 2529.7,2113.44 2544.71,2113.44 2564.83,2093.32 2564.83,2020.32 2574.33,2010.82 2574.33,1997.47 2607.33,1964.47 2607.33,1863.8 2596.71,1853.19 2568.83,1853.19 2568.58,1853.44 2540.7,1853.44 2518.21,1830.94 v1(2518.21,1805.31)
MCU_GPIO168: R135.2 U1.D4 U19.1 | length 1714.3
  Top Layer w6.25: v2(1656.7,1260.82) U1.D4@1672.44,1245.08 ; R135.2@2577.21,1838.3 2578.89,1839.99 2578.89,1856.73 2589.21,1867.05 2589.21,1871.72 2621.11,1903.62 U19.1@2621.11,1910.51
  Signal Layer 4 w4: v2(1656.7,1260.82) 1671.7,1275.82 1671.7,1328.53 1682.08,1338.92 1693.01,1338.92 1703.4,1349.31 1703.4,1376.04
  Signal Layer 4 w6.25: 1703.4,1376.04 1703.4,1434.4 1716,1447 1753.98,1447 1855.41,1548.44 1924.71,1548.44 1978.21,1494.94 2139.23,1494.94 2139.48,1495.19 2360.04,1495.19 2451.38,1586.53 2451.38,1722.37 2441.63,1732.12 2441.63,1828.57 2480.38,1867.32 2480.38,1899.12 2546.7,1965.44 2561.71,1965.44 2589.21,1937.94 v1(2589.21,1871.31)
MCU_TCK: EC1.5 U1.V15 U7:A.14 | length 5087.4
  Top Layer w6.25: v1(325.01,350) 325.01,330 355.01,300 355.01,255 392.72,217.29 EC1.5@392.72,91 ; v1(1470.01,1962) 1470.2,1961.81 1545.96,1961.81 U7:A.14@1546.15,1961.61 ; U1.V15@2018.9,804.13 v2(2034.65,788.38)
  Signal Layer 3 w6.25: v1(1470.01,1962) 1570.56,1962 1643.13,1889.44 1723.94,1889.44 1743.94,1869.44 1752.71,1869.44 1800.28,1821.88 1951.77,1821.88 1963.21,1833.31 v1(1963.21,1832.31)
  Signal Layer 8 w4: 1988.15,1371 1988.15,845.16 1998.43,834.88 2009.36,834.88 2019.65,824.6 2019.65,813.67 2031.97,801.34 2031.97,791.06 v2(2034.65,788.38)
  Signal Layer 8 w6.25: v1(325.01,350) 325.01,477.79 274.86,527.94 272.26,527.94 234.88,565.31 107.21,565.31 77.71,594.81 77.71,1027.81 141.21,1091.31 990.88,1091.31 1162.83,1263.26 1162.83,1514.68 1236.91,1588.76 1236.91,1812.73 1213.88,1835.76 1213.88,1902.51 1273.38,1962 v1(1470.01,1962) ; v1(1963.21,1832.31) 2006.84,1832.31 2036.33,1802.82 2036.33,1763.96 2005.96,1733.58 2005.96,1397.06 1988.15,1379.26 1988.15,1371
MCU_TDI: EC1.8 U1.W13 U7:A.18 | length 5675.2
  Top Layer w6.25: v1(1450.99,2063.98) U7:A.18@1546.15,2063.98 ; U1.W13@1955.91,772.63 v2(1971.66,756.89)
  Signal Layer 4 w6.25: v1(1450.99,2063.98) 1604.91,2063.98 1719.7,1949.19 1878.08,1949.19 v1(1919.21,1990.31)
  Signal Layer 7 w4: v2(1971.66,756.89) 1986.66,771.89 1986.66,793.1 1996.94,803.38 2007.87,803.38 2018.15,813.67 2018.15,1372
  Signal Layer 7 w6.25: v1(1919.21,1990.31) 1954.33,1955.19 1981.53,1955.19 1988.78,1962.44 2011.71,1962.44 2032.75,1941.4 2032.75,1825.63 2036.33,1822.05 2036.33,1763.96 2011.88,1739.51 2011.88,1444 2018.15,1437.73 2018.15,1372
  Signal Layer 8 w6.25: v1(400.01,245) 400.01,275.63 379.73,295.91 379.61,295.91 361.21,314.31 361.21,493.31 259.21,595.31 120.21,595.31 102.21,613.31 102.21,1010.31 156.21,1064.31 1001.21,1064.31 1187.33,1250.44 1187.33,1503.2 1288.38,1604.25 1288.38,1857.01 1359.5,1928.13 1408.25,1928.13 1457.5,1878.88 1527.51,1878.88 1532.76,1884.13 1602.77,1884.13 1631.33,1912.69 1631.33,1969.82 1615.28,1985.88 1594.5,1985.88 1510,2070.38 1469.43,2070.38 1466.04,2066.99 1454,2066.99 v1(1450.99,2063.98)
  Bottom w6.25: v1@400.01,250 v1(400.01,245) 400.01,200 424.22,175.79 EC1.8@424.22,91
MCU_TDO: EC1.6 R15.1 U7:A.11 | length 5443.5
  Top Layer w6.25: v1(1497.01,1897) 1501.27,1897 1511.24,1887.04 1543.96,1887.04 U7:A.11@1546.15,1884.84 ; v1(1992.21,538.31) 2024.7,538.31 R15.1@2025.01,538.62
  Signal Layer 8 w6.25: v1(1497.01,1897) 1453.63,1940.38 1354.43,1940.38 1276.13,1862.08 1276.13,1610.66 1175.08,1509.61 1175.08,1258.19 993.46,1076.56 150.46,1076.56 89.96,1016.06 89.96,608.24 118.88,579.31 238.21,579.31 277.33,540.19 279.94,540.19 346.21,473.92 346.21,303.8 v1(380.01,270) 380.01,239.37 416.29,203.08 568.83,203.08 688.87,323.13 1317.52,323.13 1361.92,278.72 1361.92,222.49 1422.1,162.31 1904.92,162.31 1965.1,222.49 1965.1,303.09 1991.83,329.82 1991.83,537.94 v1(1992.21,538.31)
  Bottom w6.25: v1(380.01,270) 380.01,253.59 379.88,253.46 379.88,190.13 392.72,177.29 EC1.6@392.72,91
MCU_TMS: EC1.3 U1.W14 U7:A.12 | length 6016.4
  Top Layer w6.25: v1(260.01,335) 271.59,323.42 295.01,323.42 341.98,276.45 341.98,235 361.23,215.75 EC1.3@361.23,91 ; U7:A.12@1546.15,1910.43 1548.35,1908.24 1596.77,1908.24 v1(1599.01,1906) ; U1.W14@1987.4,772.63 v2(2003.15,756.89)
  Signal Layer 7 w6.25: v1(260.01,335) 305.88,289.12 520.25,289.12 605.69,203.69 1054.33,203.69 1173.77,323.13 1317.52,323.13 1358.81,281.83 1358.81,225.6 1384.79,199.63 1753.26,199.63 1802.87,249.23 1802.87,373.34 1935.91,506.39 1935.91,583 2003.15,650.24 v2(2003.15,756.89)
  Signal Layer 8 w6.25: v1(260.01,335) 260.01,462.48 275.33,477.8 275.33,492.82 264.71,503.44 260.08,503.44 225.46,538.06 99.81,538.06 53.21,584.66 53.21,1068.31 106.21,1121.31 986.23,1121.31 1137.21,1272.28 1137.21,1538.94 1184.13,1585.87 1184.13,1909.89 1305.17,2030.92 1447.3,2030.92 1474.5,2058.13 1489.52,2058.13 1599.01,1948.63 v1(1599.01,1906)
MCU_TRSTn: EC1.4 R16.2 U1.V14 U7:A.16 | length 5584.3
  Top Layer w6.25: v1(1453.21,2012.8) U7:A.16@1546.15,2012.8 ; U1.V14@1987.4,804.13 v2(2003.15,788.38) ; R16.2@2090.01,538.62 2090.01,542.56 2159.19,611.74 2159.19,618.3 v1(2162.21,621.31)
  Signal Layer 3 w6.25: v1(1453.21,2012.8) 1537.09,2012.8 1615.01,1934.88 1735.14,1934.88 1749.45,1949.19 1945.08,1949.19 v1(1969.21,1973.31)
  Signal Layer 8 w4: 1956.66,1373.86 1956.66,845.16 1966.94,834.88 1977.87,834.88 1988.15,824.6 1988.15,803.38 v2(2003.15,788.38)
  Signal Layer 8 w6.25: v1(295.01,350) 295.01,490.47 269.79,515.69 267.18,515.69 232.56,550.31 104.88,550.31 65.46,589.74 65.46,1044.56 126.21,1105.31 987.56,1105.31 1150.58,1268.34 1150.58,1534.99 1196.38,1580.79 1196.38,1902.33 1306.85,2012.8 v1(1453.21,2012.8) ; 1956.66,1373.86 1956.66,1617.48 1943.16,1630.98 1943.16,1799.81 1936.07,1806.89 1936.07,1881.69 1969.21,1914.82 v1(1969.21,1973.31)
  Bottom w4: v2(2003.15,788.38) 2019.21,772.33 2019.21,739.31
  Bottom w6.25: v1(295.01,350) 295.01,323.42 345.01,273.42 345.01,210 361.23,193.78 EC1.4@361.23,91 ; 2019.21,739.31 2019.21,694.79 2050.74,663.26 2095.26,663.26 2137.21,621.31 v1(2162.21,621.31)
MCU_XRSn: C3.1 EC1.120 R20.1 S1.1 TP2.1 U1.F19 U3.1 U4.1 | length 3201.7
  Top Layer w6.25: TP2.1@2034,2102 2081.94,2054.06 2134.25,2054.06 2168.32,2020 C3.1@2172.25,2020 R20.1@2236.39,2020 ; U3.1@2050.88,1942.4 2051.47,1943 v1(2099.01,1943) ; U1.F19@2144.88,1182.08 v2(2160.63,1197.83) ; S1.1@2266.94,2300 2260.13,2293.2 2260.13,2039.81 2240.32,2020 R20.1@2236.39,2020 ; v1(2400.21,1974.31) 2330.66,1974.31 2298.75,1942.4 U4.1@2290.88,1942.4 2283,1942.4 2244.33,1981.08 2244.33,2012.06 R20.1@2236.39,2020
  Signal Layer 7 w6.25: TP2.1@2034,2102 2102.13,2033.87 2102.13,1950.39 2099.01,1947.26 v1(2099.01,1943) ; v2(2160.63,1197.83) 2193.47,1197.83 2342.38,1346.74 2342.38,1467.81 2344.33,1469.75 2344.33,1590.82 2329.08,1606.07 2329.08,1635.55 2353.08,1659.55 2353.08,1760.57 2367.21,1774.69 2367.21,1842.31 2400.21,1875.31 v1(2400.21,1974.31)
  Signal Layer 8 w6.25: v2(2160.63,1197.83) 2194.17,1197.83 2280,1112 2280,1077 2271.58,1068.58 2271.58,825.97 2260.88,815.28 2260.88,535.83 2258.08,533.03 2258.08,498.8 2315.54,441.35 2329.13,441.35 2386.58,383.89 2386.58,326.57 v1(2360.01,300)
  Bottom w6.25: EC1.120@2313.98,91 2313.98,253.97 v1(2360.01,300)
MID_SCI-RX: S1:A.2 U9:A.7 | length 1100.1
  Top Layer w6.25: U9:A.7@1168.51,1410.32 1168.67,1410.16 1254.85,1410.16 v1(1255.01,1410) ; S1:A.2@1275.01,2215 v1(1320.01,2215)
  Bottom w6.25: v1(1255.01,1410) 1255.01,1446.88 1208.07,1493.82 1208.07,1590.2 1164.14,1634.13 1142.62,1634.13 1115.88,1660.87 1115.88,1863.21 1201.93,1949.26 1216.79,1949.26 1320.01,2052.48 v1(1320.01,2215)
MID_TCK: U6:A.7 U7:A.6 | length 145.5
  Top Layer w6.25: U6:A.7@1178.51,1975 1180.16,1973.35 1219.35,1973.35 1223.89,1968.81 1246.04,1968.81 1263.91,1986.69 1313.35,1986.69 U7:A.6@1313.87,1987.2
MID_TDI: U5:A.7 U7:A.2 | length 205.3
  Top Layer w6.25: U5:A.7@1176.68,2197.63 1179.29,2195.02 1229.62,2195.02 1260.92,2163.73 1260.92,2123.82 1295.17,2089.57 U7:A.2@1313.87,2089.57
MID_TDO: U7:A.9 U8:A.2 | length 279.2
  Top Layer w6.25: U7:A.9@1313.87,1910.43 1314.08,1910.22 1366.79,1910.22 v1(1367.01,1910)
  Bottom w6.25: U8:A.2@1175.34,1827.37 1220.74,1827.37 1303.38,1910 v1(1367.01,1910)
MID_TMS: U6:A.6 U7:A.8 | length 139.9
  Top Layer w6.25: U6:A.6@1178.51,1925 1178.63,1925.13 1281.17,1925.13 1292.06,1936.02 U7:A.8@1313.87,1936.02
MID_TRSTn: U5:A.6 U7:A.4 | length 187.4
  Top Layer w6.25: U5:A.6@1175.47,2147.63 1192.37,2147.63 1243.6,2096.41 1243.6,2089.96 1295.17,2038.39 U7:A.4@1313.87,2038.39
NetC4:A_2: C4:A.2 U1:A.4 | length 160.7
  Top Layer w6.2: U1:A.4@734.56,2125.74 734.56,2176.85 747.37,2189.67 798.84,2189.67 C4:A.2@827.16,2217.99
NetC5_1: C5.1 R26.1 R28.1 TP3.1 U3.6 U4.6 | length 853.1
  Top Layer w6.25: R28.1@1910.01,1911.5 1900.01,1921.5 R26.1@1900.01,2036.38 C5.1@1955.01,2036.38 1955.01,2032.44 1963.7,2023.76 2011.25,2023.76 2015.01,2020 2050.26,2020 2121.18,1949.08 2152.47,1949.08 U3.6@2159.14,1942.4 ; v1(2359.01,1943) 2398.54,1943 U4.6@2399.14,1942.4
  Signal Layer 8 w6.25: TP3.1@2023,2019 2042.13,2038.13 2263.88,2038.13 v1(2359.01,1943)
NetC11_1: C11.1 R47.2 R48.1 R49.1 | length 206
  Bottom w6.25: R49.1@1368.43,612.12 R47.2@1368.43,552.12 R48.1@1368.43,492.12 1369.41,492.12 1399.86,461.68 1399.86,442.7 1415.44,427.12 C11.1@1416.42,427.12
NetC13:A_1: C13:A.1 C14:A.2 L1:A.1 U2:A.4 | length 1221.5
  Top Layer w6.2: v1(121.96,1626.77) 140.99,1607.74 301.16,1607.74 359.64,1666.21 ; 381.96,1721.77 v1(441.96,1721.77) 455.54,1708.19 629,1708.19 681.96,1761.15 681.96,1858.77 645.92,1894.81 645.92,1971.97 v1(625.4,1992.49)
  Top Layer w6.25: 359.64,1666.21 359.64,1699.44 381.96,1721.77
  Bottom w6.25: v1(121.96,1626.77) 123.54,1628.34 C14:A.2@123.54,1671.61 ; U2:A.4@429.6,1791.14 429.6,1734.13 v1(441.96,1721.77) ; v1(625.4,1992.49) 625.4,2037.99 629.47,2042.06 L1:A.1@639.53,2042.06 640.39,2042.92 C13:A.1@762.5,2042.92
NetC15:A_1: C15:A.1 C16:A.2 L2:A.1 U2:A.9 | length 831.4
  Bottom w6.25: C16:A.2@420.78,1911.61 420.78,1964.48 C15:A.1@408.65,1976.61 395.81,1989.45 395.81,2019.06 367.16,2047.72 367.16,2144.05 401.29,2178.18 511.89,2178.18 556.48,2133.6 556.48,2022.58 527.27,1993.37 527.27,1791.89 U2:A.9@528.02,1791.14
NetC15_1: C15.1 U6.5 | length 238
  Top Layer w6.25: v1(1275.01,435) 1323.59,435 1406.3,517.71 U6.5@1424.02,517.71
  Bottom w6.25: v1(1275.01,435) 1275.01,475.71 C15.1@1284.92,485.63
NetC17:A_2: C17:A.2 J1:A.6 J1:A.7 J1:A.8 J1:A.9 R11:A.1 | length 872.3
  Top Layer w6.25: J1:A.7@341.82,1899.41 125.29,1899.41 125.29,2011.06 v1(125.97,2011.75) 125.29,2012.43 125.29,2245.86 J1:A.6@341.82,2245.86
  Bottom w6.25: R11:A.1@123.54,2051.61 124.46,2052.54 C17:A.2@124.46,2106.02
  Bottom w10: v1@123.54,2014.18 R11:A.1@123.54,2051.61
NetC18:A_2: C18:A.2 U2:A.2 Y1:A.1 | length 320
  Bottom w6.25: Y1:A.1@175.46,1884.44 176.92,1882.99 237.74,1882.99 313.96,1806.77 350.21,1770.52 350.21,1760.69 364.32,1746.58 386.47,1746.58 390.23,1750.33 U2:A.2@390.23,1791.14
NetC19:A_2: C19:A.2 U2:A.3 Y1:A.3 | length 574
  Top Layer w6: v1@319.21,1764.31 v1(320.21,1763.31)
  Top Layer w6.2: C19:A.2@87.16,1730.23 v1@87.16,1798.58 ; v1@88.85,1798.84 v1(88.14,1799.56) 109.55,1820.97 304,1820.97 319.21,1805.76 v1@319.21,1764.31
  Bottom w6: Y1:A.3@88.85,1738.77 v1@88.85,1798.84
  Bottom w6.25: v1(320.21,1763.31) 320.21,1761.64 350.37,1731.47 396.21,1731.47 409.91,1745.18 U2:A.3@409.91,1791.14
NetC28_1: C28.1 R77.2 | length 70.9
  Bottom w6.25: C28.1@1507.09,567.91 R77.2@1507.09,638.78
NetC29_1: C29.1 R78.2 | length 78.7
  Bottom w6.25: C29.1@1790.55,567.91 R78.2@1790.55,646.65
NetC30_1: C30.1 R79.2 | length 74.1
  Bottom w6.25: C30.1@1381.1,945.86 1388.98,937.99 R79.2@1451.97,937.99
NetC31_1: C31.1 R80.2 | length 78.7
  Bottom w6.25: C31.1@1617.33,567.91 R80.2@1617.33,646.65
NetC48_1: C48.1 R84.1 U14.9 | length 394.2
  Top Layer w6.25: v1(3500.01,925) 3500.01,1040 v1(3570.01,1110)
  Bottom w6.25: v1(3500.01,925) 3532.46,957.45 U14.9@3555.71,957.45 ; v1(3570.01,1110) 3570.01,1142.91 C48.1@3566.54,1146.38 R84.1@3639.77,1146.38
NetC49_2: C49.2 R85.2 U14.7 | length 274.4
  Signal Layer 3 w6.25: v1(3525.01,880) 3525.01,814.26 3535.01,804.26 v1(3535.01,800)
  Bottom w6.25: v1(3525.01,880) 3526.41,881.4 3526.41,900.38 3544.12,918.08 U14.7@3555.71,918.08 ; v1(3535.01,800) C49.2@3572.92,800.01 3574.66,798.26 3636.04,798.26 R85.2@3657.92,776.38
NetC50_2: C50.2 R89.1 R92.2 U14.1 | length 476.3
  Signal Layer 3 w6.25: v1(3480.01,1155) 3555.64,1155 3665.01,1045.63 v1(3665.01,1005)
  Bottom w6.25: C50.2@3302.92,1155.01 R89.1@3372.92,1155.01 R92.2@3442.92,1155.01 v1(3480.01,1155) ; v1(3665.01,1005) 3665.01,978.07 U14.1@3665.94,977.14
NetC83_1: C83.1 D6.2 J3.1 R98.2 U15.1 U16.6 | length 1293.6
  Top Layer w6.25: v1(1768.88,2135.88) 1768.88,2164.51 1778.04,2173.66 1778.04,2202.02 J3.1@1783.77,2207.75 ; v1(1817.01,1984) 1817.01,1988.07 1829.38,2000.44 U16.6@1829.38,2075
  Signal Layer 4 w6.25: v1(1734.21,1746.31) 1749.88,1761.99 1749.88,1775.24 1937.33,1962.69 1937.33,1997.82 1926.71,2008.44 1841.45,2008.44 v1(1817.01,1984) 1817.01,2086.37 1768.88,2134.49 v1(1768.88,2135.88)
  Bottom w6.25: U15.1@1636.56,2004.13 1627,2013.7 D6.2@1627,2117 1627,2152.85 1662.59,2188.44 1677.71,2188.44 1695.3,2170.85 1735.3,2170.85 1768.88,2137.27 v1(1768.88,2135.88) ; v1@1741.91,1742.88 1775.52,1742.88 1777.07,1744.42 1792.94,1744.42 C83.1@1808.51,1760 R98.2@1808.51,1831.5
NetC86_2: C86.2 J3.6 J3.7 J3.8 J3.9 J3.10 J3.11 R106.1 | length 796.1
  Top Layer w6.25: J3.10@1679.44,2312.48 1686.96,2304.96 1686.96,2224.05 v1@1687.99,2223.02 ; v1(1689.97,2225) 1734.93,2225 1738.01,2221.93 1738.01,2234.23 1774.1,2270.33 1774.1,2288.54 1798.05,2312.48 1848.15,2312.48 J3.8@1860.01,2300.62 ; J3.8@1871.86,2312.48 J3.8@1860.01,2300.62 ; J3.6@1931.9,2221.93 J3.6@1931.9,2234.23 ; J3.7@1990.47,2312.48 1990.47,2292.79 J3.6@1931.9,2234.23 ; J3.8@1860.01,2300.62 1873.38,2300.62 1895.81,2278.2 1895.81,2270.33 J3.6@1931.9,2234.23
  Bottom w6.25: v1(1689.97,2225) 1689.97,2210.03 1705,2195 R106.1@1731.38,2195 1735,2198.62 1735,2230 1740,2235 1825,2235 1836.38,2223.62 C86.2@1836.38,2195
NetC103_2: C103.2 J4.10 J4.13 J4.14 | length 1843.4
  Signal Layer 3 w6.25: v1(3284.01,1844) 3500.01,2060 v1(3751.01,2060)
  Signal Layer 7 w6.25: v1(3751.01,2060) 3751.01,1741.83 3757.96,1734.89 3757.96,1624.1 3836.01,1546.04 v1(3836.01,1363)
  Bottom w6.25: J4.10@3170.84,1844.18 3171.02,1844 v1(3284.01,1844) ; v1(3751.01,2060) 3751.01,2133.91 C103.2@3752.1,2135 3752.1,2124.17 3774.56,2101.71 3870.79,2101.71 3927.53,2044.97 J4.14@3955.09,2044.97 ; v1(3836.01,1363) 3954.38,1363 J4.13@3955.09,1362.29
NetC121_2: C121.2 J5.10 J5.13 J5.14 | length 1940.1
  Top Layer w6.25: J5.10@3170.84,1783.15 3171.98,1782 v1(3289.01,1782) ; v1(3823.01,2265) 3955.05,2265 J5.13@3955.09,2265.04 ; v1(3842.65,1582.36) J5.14@3955.09,1582.36
  Signal Layer 3 w6.25: v1(3289.01,1782) 3377.45,1870.44 3720.71,1870.44 3842.65,1748.5 v1(3842.65,1582.36)
  Signal Layer 7 w6.25: v1(3823.01,2265) 3842.65,2245.36 v1(3842.65,1582.36)
  Bottom w6.25: C121.2@3752.1,2245 3772.1,2265 v1(3823.01,2265)
NetC139_2: C139.2 J6.10 J6.13 J6.14 | length 1759.4
  Top Layer w6.25: J6.10@3172.89,831.2 3274.67,831.2 3346.59,759.29 3745.72,759.29 v1(3835.01,670) 3940.8,670 J6.14@3957.14,653.65 ; v1(3803.01,1338) 3955.47,1338 J6.13@3957.14,1336.33
  Signal Layer 7 w6.25: v1(3803.01,1338) 3803.01,1236.14 3838.13,1201.02 3838.13,847.49 3835.01,844.37 v1(3835.01,670)
  Bottom w6.25: C139.2@3772.1,670 v1(3835.01,670)
NetD1_1: D1.1 U2.6 | length 109.2
  Top Layer w6.25: v1(1824.01,1559) 1824.51,1559.5 1824.51,1595.13 1843.04,1613.66 D1.1@1845.01,1613.66
  Bottom w6.25: v1(1824.01,1559) 1825.17,1560.16 1848.92,1560.16 1857.61,1568.84 U2.6@1857.61,1575.87
NetD1_2: D1.2 R9.2 | length 69.3
  Top Layer w6.25: D1.2@1845.01,1696.34 1858.63,1709.96 R9.2@1858.63,1760
NetD2:A_2: D2:A.2 R1:A.2 | length 94.8
  Top Layer w6.2: v1(606.96,2251.77) 652.64,2251.77 D2:A.2@656.2,2255.33
  Bottom w6.25: v1(606.96,2251.77) 609.87,2254.68 R1:A.2@649.81,2254.68
NetD2_1: D2.1 U2.4 | length 117
  Top Layer w6.25: D2.1@1950.01,1613.66 1951.98,1613.66 1984.19,1581.45 1984.19,1573.33 v1(1987.21,1570.31)
  Bottom w6.25: U2.4@1932.41,1575.87 1937.97,1570.31 v1(1987.21,1570.31)
NetD2_2: D2.2 R10.2 | length 81
  Top Layer w6.25: D2.2@1950.01,1696.34 1951.98,1696.34 1970.51,1714.87 1970.51,1750.81 1979.69,1760 R10.2@1983.63,1760
NetD3:A_1: D3:A.1 R6:A.2 | length 149.9
  Top Layer w6.25: v1(61.96,1336.77) 61.96,1381.77 D3:A.1@86.96,1406.77
  Bottom w6.25: v1(61.96,1336.77) 82.16,1356.96 R6:A.2@82.16,1397.99
NetD4:A_1: D4:A.1 R7:A.2 | length 153.6
  Top Layer w6.25: v1(151.96,1336.77) 151.96,1376.77 175.17,1399.98 D4:A.1@182.16,1392.99
  Bottom w6.25: v1(151.96,1336.77) 155.72,1336.77 182.16,1363.2 R7:A.2@182.16,1392.99
NetD5_2: D5.2 R87.1 | length 109.1
  Bottom w6.25: D5.2@3017.92,830.04 3036.45,848.57 3106.55,848.57 3115.24,857.26 R87.1@3115.24,857.76
NetD6_1: D6.1 R102.2 | length 136.4
  Bottom w6.25: D6.1@1535,2117 1535,1996.39 R102.2@1546.15,1985.24
NetD7_1: D7.1 U20.6 | length 1133
  Top Layer w6.25: v1(3518.55,2252.65) D7.1@3518.55,2305.31 ; U20.6@3590.88,1427.6 3593.52,1427.6 3602.21,1418.91 v1(3602.21,1345.31)
  Signal Layer 8 w6.25: v1(3518.55,2252.65) 3662.33,2108.86 3662.33,1586.8 3602.21,1526.68 v1(3602.21,1345.31)
NetD7_2: D7.2 R141.1 | length 1032.2
  Top Layer w6.25: R141.1@3228.63,1400 3237.32,1408.69 3303.09,1408.69 3309.41,1415 v1(3313.67,1415) ; v1(3435.87,2254.65) D7.2@3435.87,2305.31
  Signal Layer 7 w6.25: v1(3313.67,1415) 3398.58,1499.91 3398.58,2217.36 v1(3435.87,2254.65)
NetD8_1: D8.1 U20.4 | length 1019.8
  Top Layer w6.25: v1(3313.55,2255.65) D8.1@3313.55,2305.31 ; v1(3590.21,1540.31) 3590.21,1503.07 U20.4@3590.88,1502.4
  Signal Layer 7 w6.25: v1(3313.55,2255.65) 3330.67,2272.78 3443.38,2272.78 3466.88,2249.27 3466.88,2129.76 3574.08,2022.56 3574.08,1633.48 3592.33,1615.23 3592.33,1542.44 v1(3590.21,1540.31)
NetD8_2: D8.2 R142.2 | length 971.3
  Top Layer w6.25: R142.2@3228.63,1510 3237.32,1501.31 3283.2,1501.31 v1(3284.21,1500.31) ; D8.2@3230.87,2305.31 3230.87,2303.34 3268.21,2266 v1(3268.21,2230.31)
  Signal Layer 7 w6.25: v1(3268.21,2230.31) 3268.21,2085.31 3386.33,1967.19 3386.33,1602.44 v1(3284.21,1500.31)
NetJ1:A_2: J1:A.2 U2:A.7 U3:A.5 | length 444.4
  Top Layer w6.2: J1:A.2@341.82,2104.13 v1(418.68,2104.13) v1@418.95,2104.41
  Bottom w6.25: v1(418.68,2104.13) 440.5,2104.13 447.63,2097 447.63,2086.3 468.82,2086.3 476.07,2079.04 476.07,1902.66 488.65,1890.08 U2:A.7@488.65,1791.14
NetJ1:A_3: J1:A.3 U2:A.8 U3:A.3 | length 482.2
  Top Layer w6.2: J1:A.3@341.82,2072.63 420.18,2072.63 445.89,2046.93 445.89,2005.47 468.05,1983.31 v1(504.21,1983.31)
  Bottom w6.25: U3:A.3@506.69,2046.93 506.69,1985.79 v1(504.21,1983.31) 508.34,1979.18 U2:A.8@508.34,1791.14
NetJ1_1: J1.1 R14.1 | length 105.2
  Top Layer w6.25: R14.1@2416.26,2193.93 v1(2416.26,2234.75)
  Bottom w6.25: J1.1@2416.26,2170.31 v1(2416.26,2234.75)
NetJ1_8: J1.8 R19.2 | length 106.1
  Top Layer w6.25: v1(2112.01,2113) 2112.01,2108.74 2118.76,2101.98 2118.76,2083.69 2127.45,2075 R19.2@2131.39,2075
  Bottom w6.25: v1(2112.01,2113) 2112.01,2169.21 J1.8@2113.11,2170.31
NetJ4_1: J4.1 R117.2 | length 165.2
  Bottom w6.25: R117.2@3021.51,1405 3022.49,1405 3048.06,1430.57 3158.02,1430.57 J4.1@3170.84,1443.39
NetJ4_2: J4.2 R115.1 U17.17 | length 498
  Bottom w6.25: U17.17@2759.97,1531.57 2759.97,1527.33 2780.17,1507.12 2831.76,1507.12 2833.7,1505.19 2854.7,1505.19 2925.7,1434.19 2991.71,1434.19 3016.01,1458.48 3016.01,1476.31 3024.69,1485 R115.1@3028.63,1485 3032.57,1485 3050.58,1503.01 3158.02,1503.01 J4.2@3170.84,1515.83
NetJ4_11: J4.11 R114.1 U17.24 | length 1020.3
  Top Layer w6.25: R114.1@2595.01,1561.38 2595.15,1561.23 v1(2595.15,1526.63)
  Signal Layer 4 w6.25: v1(2595.15,1526.63) 2596.21,1527.69 2760.95,1527.69 2865.95,1632.69 3028.21,1632.69 3284.01,1888.48 v1(3284.01,1891)
  Bottom w6.25: v1(2595.15,1526.63) 2620.38,1526.63 2622.17,1528.43 U17.24@2622.17,1531.57 ; J4.11@3170.84,1891.42 3171.26,1891 v1(3284.01,1891)
NetJ4_12: J4.12 R116.2 | length 172.2
  Bottom w6.25: R116.2@3163.51,2130 3170.84,2122.68 3170.84,1963.87 J4.12@3172.97,1966
NetJ5_1: J5.1 R138.2 | length 164.7
  Top Layer w6.25: R138.2@3026.51,2230 3042.08,2214.42 3070.18,2214.42 3098.96,2185.64 J5.1@3172.83,2185.64
NetJ5_12: J5.12 R129.2 | length 201.2
  Top Layer w6.25: R129.2@3105.01,1511.5 3120.59,1527.07 3120.59,1650.64 3133.41,1663.46 J5.12@3170.84,1663.46
NetJ6_1: J6.1 R161.2 | length 122.2
  Top Layer w6.25: R161.2@3036.51,1320 3045.07,1311.44 3060.5,1311.44 3073.3,1298.64 3073.3,1257.2 J6.1@3098.14,1232.36
NetJ6_12: J6.12 R153.2 | length 155
  Top Layer w6.25: R153.2@3060.01,651.5 3075.59,667.07 3075.59,689.39 3108.08,721.88 J6.12@3172.83,721.88
NetL1_1: L1.1 U14.6 | length 100.9
  Bottom w6.25: L1.1@3486.85,846.11 3486.85,847.48 3501.25,861.88 3532.52,861.88 3548.98,878.34 3548.98,894.69 3552.68,898.4 U14.6@3555.71,898.4
NetL2_1: L2.1 U14.10 | length 80.5
  Bottom w6.25: L2.1@3486.3,996.16 3486.3,990.74 3499.91,977.14 U14.10@3555.71,977.14
NetR3:A_2: R3:A.2 U2:A.24 | length 542.3
  Top Layer w6.2: v1(701.96,1946.77) 676.99,1921.79 676.99,1886.09 718.96,1844.11 718.96,1787.86 726.97,1779.86 v1(726.97,1750.07) v1@726.57,1749.67
  Bottom w6.25: R3:A.2@661.96,1945.39 663.34,1946.77 v1(701.96,1946.77) ; v1@726.57,1749.67 704.6,1749.67 651.29,1696.36 651.29,1622.07 690.88,1582.48 U2:A.24@736.69,1582.48
NetR3_2: R3.2 U1.M16 | length 218.6
  Top Layer w6.25: U1.M16@2050.4,993.11 v2(2066.14,977.36) ; v1(2202.9,954.6) 2216.93,954.6 2239.69,977.36 R3.2@2243.62,977.36
  Signal Layer 3 w4: v2(2066.14,977.36) 2081.19,962.31 2177.21,962.31
  Signal Layer 3 w6.25: 2177.21,962.31 2195.19,962.31 v1(2202.9,954.6)
NetR4:A_1: R4:A.1 U2:A.28 | length 74.7
  Bottom w6.25: U2:A.28@736.69,1503.74 R4:A.1@811.41,1503.74
NetR4_2: R4.2 U1.L16 | length 228.2
  Top Layer w6.25: U1.L16@2050.4,1024.6 v2(2066.14,1008.86) ; v1(2201.34,1001.18) 2216.09,1015.92 2234.94,1015.92 R4.2@2243.62,1024.6
  Signal Layer 4 w4: v2(2066.14,1008.86) 2084.89,1027.6 2169.07,1027.6 2195.5,1001.18 v1(2201.34,1001.18)
NetR5:A_1: R5:A.1 U2:A.32 | length 75.2
  Bottom w6.25: U2:A.32@736.69,1425 R5:A.1@811.92,1425
NetR5_2: R5.2 U1.L17 | length 299.1
  Top Layer w6.25: U1.L17@2081.89,1024.6 v2(2097.64,1008.86) ; v1(2241.21,884.31) 2241.21,927.7 R5.2@2243.62,930.12
  Bottom w4: v2(2097.64,1008.86) 2112.64,993.86 2112.64,972.64 2124.42,960.86 2166.85,960.86 2179.53,948.18 2179.53,941.99
  Bottom w6.25: 2179.53,941.99 2188.31,933.21 2188.31,901.03 2205.02,884.31 v1(2241.21,884.31)
NetR6:A_1: R6:A.1 U2:A.54 | length 351.8
  Top Layer w6.25: v1(76.96,1541.77) 208.23,1541.77 226.95,1523.05 v1(226.95,1497.41)
  Bottom w6.25: R6:A.1@82.16,1445.23 82.16,1530.11 ; v1(226.95,1497.41) 252.97,1523.42 U2:A.54@299.68,1523.42
NetR6_2: R6.2 U1.K17 | length 246
  Top Layer w6.25: U1.K17@2081.89,1056.1 v2(2097.64,1071.85) ; R6.2@2243.62,1071.85 2244.52,1071.85 2253.21,1080.53 v1(2253.21,1103.31)
  Bottom w4: v2(2097.64,1071.85) 2113.1,1087.31
  Bottom w6.25: 2113.1,1087.31 2134.79,1109 2157.52,1109 2180.64,1085.88 2235.77,1085.88 v1(2253.21,1103.31)
NetR7:A_1: R7:A.1 U2:A.55 | length 199
  Bottom w6.25: R7:A.1@182.16,1440.23 182.16,1506.61 217.95,1542.41 298.98,1542.41 U2:A.55@299.68,1543.11
NetR7_2: R7.2 U1.A17 | length 100.3
  Top Layer w6.25: U1.A17@2081.89,1339.56 v2(2097.64,1355.31) R7.2@2097.64,1433.3
NetR8:A_2: R8:A.2 R9:A.1 U4:A.4 | length 129
  Top Layer w6.25: R9:A.1@336.95,1516.78 409.7,1516.78 U4:A.4@408.32,1515.41 ; U4:A.4@404.15,1511.23 U4:A.4@408.32,1515.41 ; U4:A.4@406.96,1516.77 U4:A.4@408.32,1515.41 ; R8:A.2@411.96,1470.39 411.96,1511.77 408.5,1515.23 U4:A.4@408.32,1515.41
NetR8_2: R8.2 U1.B16 | length 150.7
  Top Layer w6.25: U1.B16@2050.4,1308.07 v2(2066.14,1323.82) ; R8.2@2050.4,1433.3 2059.08,1424.62 2059.08,1402.7 2067.21,1394.57 v1(2067.21,1390.31)
  Bottom w4: v2(2066.14,1323.82) 2081.14,1338.82 2081.14,1367
  Bottom w6.25: v1(2067.21,1390.31) 2081.14,1376.38 2081.14,1367
NetR9:A_2: R9:A.2 U2:A.61 U4:A.3 | length 339.5
  Top Layer w6.25: R9:A.2@336.95,1564.03 407.7,1564.03 410.08,1566.41 v1(467.95,1566.41)
  Bottom w6.25: U2:A.61@299.68,1661.22 344.63,1661.22 439.44,1566.41 v1(467.95,1566.41)
NetR10:A_2: R10:A.2 U2:A.14 | length 117.8
  Bottom w6.25: R10:A.2@612.16,1902.99 612.16,1886.57 626.45,1872.28 U2:A.14@626.45,1791.14
NetR12:A_2: R12:A.2 U2:A.60 | length 123.3
  Top Layer w6.25: R12:A.2@196.96,1684.52 196.96,1679.77 234.96,1641.77 v1(236.96,1641.77)
  Bottom w6.25: v1(236.96,1641.77) 237.2,1641.53 U2:A.60@299.68,1641.53
NetR13:A_2: R13:A.2 U2:A.6 | length 110.3
  Bottom w6.25: R13:A.2@420.78,1861.61 454.75,1861.61 468.97,1847.39 U2:A.6@468.97,1791.14
NetR14:A_2: R14:A.2 U2:A.36 | length 126.9
  Top Layer w6.25: v1(596.96,1291.77) 598.54,1293.34 R14:A.2@598.54,1351.61
  Bottom w6.25: v1(596.96,1291.77) 606.76,1301.57 U2:A.36@606.76,1354.13
NetR15:A_1: R15:A.1 S1:A.4 U7:A.1 U7:A.19 | length 571.3
  Top Layer w6.25: U7:A.1@1313.87,2115.16 1400.85,2115.16 v1(1426.44,2089.57) U7:A.19@1546.15,2089.57 ; v1(1560.01,2301) 1560.01,2276.84 1571.85,2265 S1:A.4@1575.01,2265
  Bottom w6.25: v1(1426.44,2089.57) 1426.44,2093.83 1422.08,2098.19 1422.08,2127.82 1442.33,2148.07 1442.33,2165.96 1527.38,2251 1551.32,2251 1560.01,2259.69 v1(1560.01,2301)
NetR15_2: R15.2 U1.W15 | length 349
  Top Layer w6.25: U1.W15@2018.9,772.63 v2(2034.65,756.89) 2034.65,725.39 1971.66,662.4 1971.66,533.23 2000.89,504 2016.32,504 2025.01,495.32 R15.2@2025.01,491.38 R15.2@2022.21,488.58
NetR35_1: R35.1 U5.3 | length 163.1
  Bottom w6.25: R35.1@3455.79,566.8 3455.79,528.71 3527.3,457.2 U5.3@3551.15,457.2
NetR36_1: R36.1 S2.3 | length 70.9
  Top Layer w6.25: S2.3@1583.36,1736.81 1590.17,1730 R36.1@1651.39,1730
NetR37_2: R37.2 S2.4 | length 68.8
  Top Layer w6.25: S2.4@1583.36,1786.81 1585.17,1785 R37.2@1651.39,1785
NetR38_1: R38.1 U5.8 | length 106
  Bottom w6.25: R38.1@3225.01,535 3225.01,533.03 3231.73,526.31 3282.24,526.31 3300.17,508.39 U5.8@3318.87,508.39
NetR40_1: R40.1 U5.5 | length 96.9
  Bottom w6.25: R40.1@3224.69,425 3231.31,431.61 U5.5@3318.87,431.61
NetR41_1: R41.1 Y1.1 | length 79.1
  Bottom w6.25: Y1.1@3688.55,576.42 3688.72,576.25 3751.32,576.25 3760.01,567.56 R41.1@3760.01,563.62
NetR42_1: R42.1 U5.7 | length 94.7
  Bottom w6.25: R42.1@3224.69,481.57 3225.92,482.8 U5.7@3318.87,482.8
NetR44_2: R44.2 R46.1 U5.2 | length 312.9
  Bottom w6.25: R46.1@3368.63,643.3 3481,643.3 3489.01,635.29 3489.01,526.24 3532.45,482.8 U5.2@3551.15,482.8
NetR45_1: R45.1 Y2.1 | length 69.1
  Bottom w6.25: Y2.1@3878.55,581.42 3878.72,581.25 3931.32,581.25 3940.01,572.56 R45.1@3940.01,568.62
NetR50_1: R50.1 S3.5 | length 843.2
  Top Layer w6.25: v1(1860.01,515) 1860.01,577.52 S3.5@1861.42,578.93
  Bottom w6.25: R50.1@1562.21,638.78 1570.12,630.86 v1(1570.12,516) 1569.38,516 1546.88,493.51 1546.88,446.77 1567.43,426.23 1567.43,379.49 1564.08,376.14 1564.08,359.8 1574.7,349.19 1676.71,349.19 1751.71,424.19 1853.71,424.19 1909.33,479.8 1909.33,494.82 1889.15,515 v1(1860.01,515)
NetR50_2: R50.2 R77.1 U1.V1 | length 183.9
  Top Layer w6.25: v2(1562.21,788.38) U1.V1@1577.96,804.13
  Bottom w6.25: R77.1@1507.09,686.02 1507.26,686.19 1546.63,686.19 R50.2@1562.21,701.77 1546.63,717.34 1546.63,743.43 1546.08,743.98 1546.08,772.26 v2(1562.21,788.38)
NetR57_1: R57.1 S3.2 | length 387.7
  Top Layer w6.25: S3.2@1861.42,433.26 1861.42,445.08 1888.19,471.85 1888.19,484.3 v1(1891.21,487.31)
  Bottom w6.25: R57.1@1735.44,638.78 1728.08,631.42 1728.08,496.8 1748.78,476.11 1875.74,476.11 1886.95,487.31 v1(1891.21,487.31)
NetR57_2: R57.2 R78.1 U1.W5 | length 164.7
  Top Layer w6.25: v2(1688.19,756.89) U1.W5@1703.94,772.63
  Bottom w6.25: v2(1688.19,756.89) 1711.08,734 1727,734 1735.44,725.56 R57.2@1735.44,701.77 1782.68,701.77 R78.1@1790.55,693.89
NetR66_1: R66.1 S4.5 | length 724.4
  Top Layer w6.25: S4.5@1586.42,578.93 1586.42,590.74 1615.23,619.55 1678.78,619.55 1706,592.34 1706,588.01 v1(1709.01,585)
  Signal Layer 8 w6.25: v1(1405.41,900.71) 1461.71,844.42 1461.71,724.21 1496.6,689.31 1614.5,689.31 1706,597.82 1706,588.01 v1(1709.01,585)
  Bottom w6.25: v1@1405.41,896.14 v1(1405.41,900.71) 1426.26,900.71 R66.1@1444.1,882.87
NetR66_2: R66.2 R79.1 U1.R1 | length 135.8
  Top Layer w6.25: v2(1562.21,882.87) U1.R1@1577.96,898.62
  Bottom w6.25: R79.1@1499.21,937.99 1499.21,890.75 R66.2@1507.09,882.87 v2(1562.21,882.87)
NetR71_1: R71.1 S4.2 | length 381.3
  Top Layer w6.25: v1(1582.21,367.31) 1582.21,429.05 S4.2@1586.42,433.26
  Bottom w6.25: v1(1582.21,367.31) 1678.13,463.24 1678.13,633.09 R71.1@1672.44,638.78
NetR71_2: R71.2 R80.1 U1.V5 | length 174
  Top Layer w6.25: v2(1688.19,788.38) U1.V5@1703.94,804.13
  Bottom w4: 1672.21,742.31 1672.21,772.4 v2(1688.19,788.38)
  Bottom w6.25: R80.1@1617.33,693.89 1664.57,693.89 R71.2@1672.44,701.77 1672.21,702 1672.21,742.31
NetR83_2: R83.2 U14.4 | length 395.5
  Signal Layer 3 w6.25: v1(3480.01,705) 3525.64,705 3702.27,881.63 3702.27,901.35 v1(3702.92,902)
  Bottom w6.25: v1(3480.01,705) 3480.01,738.6 R83.2@3481.54,740.13 ; U14.4@3665.94,918.08 3683.65,918.08 3699.73,902 v1(3702.92,902)
NetR86_1: R86.1 R88.2 | length 76.9
  Bottom w6.25: R88.2@3296.54,736.38 3297.92,737.76 R86.1@3297.92,812.76
NetR88_1: R88.1 R93.2 U14.5 | length 746.4
  Signal Layer 3 w6.25: v1(3262,640.7) 3262,706.99 3336.88,781.88 3576.88,781.88 v1(3665.01,870)
  Bottom w6.25: R93.2@3169.41,736.38 R88.1@3249.3,736.38 3249.3,653.4 v1(3262,640.7) ; v1(3665.01,870) 3665.01,897.46 U14.5@3665.94,898.4
NetR90_1: R90.1 R91.2 U14.2 | length 219
  Bottom w6.25: U14.2@3665.94,957.45 3677.53,957.45 3690.31,970.23 3690.31,1061.14 3705.88,1076.71 R91.2@3706.87,1076.71 3708.33,1078.17 R90.1@3781.7,1078.17
NetR109_1: R109.1 U17.16 | length 95.5
  Top Layer w6.25: R109.1@2785.01,1581.38 2793.7,1572.69 2793.7,1537.09 2798.21,1532.57 v1(2798.21,1528.31)
  Bottom w6.25: U17.16@2785.56,1557.17 2790.48,1557.17 2792.28,1555.37 2792.28,1538.5 2798.21,1532.57 v1(2798.21,1528.31)
NetR123_1: R123.1 U19.27 | length 101.7
  Top Layer w6.25: R123.1@2510.01,2055 2512.82,2057.81 2528.44,2057.81 2534.95,2064.31 v1(2539.21,2064.31) 2568.99,2034.53 U19.27@2595.52,2034.53
NetR124_1: R124.1 U19.16 | length 64.7
  Top Layer w6.25: U19.16@2784.5,2073.9 2813.79,2073.9 v1(2815.38,2072.31)
  Bottom w6.25: R124.1@2784.5,2077.83 2790.02,2072.31 v1(2815.38,2072.31)
NetR128_1: R128.1 U19.8 | length 190.5
  Top Layer w6.25: U19.8@2758.91,1910.51 2758.91,1903.62 2783.86,1878.67 v1(2783.86,1838.54)
  Bottom w6.25: R128.1@2723.47,1910.51 2732.16,1901.83 2751.33,1901.83 2783.86,1869.29 v1(2783.86,1838.54)
NetR130_2: R130.2 U19.24 | length 248.8
  Top Layer w6.25: v1@2593.21,2095.31 2593.21,2101.31 v1(2595.21,2103.31) 2619.32,2103.31 2621.11,2101.52 U19.24@2621.11,2099.49
  Bottom w6.25: v1(2595.21,2103.31) 2572.21,2103.31 2549.21,2126.31 2549.21,2145.31 2562.21,2158.31 2605.21,2158.31 2622.21,2175.31 R130.2@2673.58,2175.31
NetR136_2: R136.2 U19.29 | length 95.9
  Top Layer w6.25: R136.2@2508,1975 2509.66,1976.66 2530.55,1976.66 v1(2538.21,1984.31) 2549.05,1995.16 U19.29@2595.52,1995.16
NetR145_1: R145.1 U21.27 | length 132.6
  Top Layer w6.25: R145.1@2488,1165 2510.52,1165 v6(2517.21,1158.31) 2536.21,1139.31 2536.21,1128.31 2553.93,1110.59 U21.27@2591.58,1110.59
NetR146_1: R146.1 U21.29 | length 109.4
  Top Layer w6.25: R146.1@2488,1085 2488.16,1085.16 2515.74,1085.16 2515.9,1085 2517.15,1085 2530.93,1071.22 U21.29@2591.58,1071.22
  other v1: 2516.21,1085.31
NetR148_1: R148.1 U21.16 | length 87.9
  Top Layer w6.25: U21.16@2780.56,1149.96 2781.01,1149.51 2801.75,1149.51 2810.95,1140.31 v1(2815.21,1140.31)
  Bottom w6.25: R148.1@2780.56,1110.59 2780.56,1114.53 2803.33,1137.3 2812.19,1137.3 v1(2815.21,1140.31)
NetR151_1: R151.1 U21.8 | length 73.1
  Top Layer w6.25: U21.8@2754.97,986.57 2755.23,986.31 v1(2786.21,986.31)
  Bottom w6.25: R151.1@2745.01,985 2746.32,986.31 v1(2786.21,986.31)
NetR154_2: R154.2 U21.24 | length 100.3
  Top Layer w6.25: v1(2572.21,1189.31) 2576.47,1189.31 2583.51,1182.27 2615.38,1182.27 2617.17,1180.47 U21.24@2617.17,1175.55
  Bottom w6.25: v1(2572.21,1189.31) 2576.47,1189.31 2581.54,1184.24 2604.55,1184.24 R154.2@2613.24,1175.55
NetS3_3: S3.3 U13.6 U13.7 | length 1193.9
  Top Layer w6.25: U13.7@1254.14,693.6 1255.54,695 1305.01,695 ; U13.6@1254.14,718.6 1255.94,716.79 1292.05,716.79 1305.01,703.84 1305.01,695 ; S3.3@1930.32,433.26 1930.32,421.45 1896.3,387.44 1809.96,387.44 1774.9,352.38 1738.41,352.38 1687.91,301.88 1647.5,301.88 1633.07,316.31 1633.07,320.4 1604.29,349.19 1542.8,349.19 1535.11,356.88 1403.77,356.88 1362.52,398.13 1286.25,398.13 1256.88,427.49 1256.88,482.63 1305.01,530.75 1305.01,695
NetS3_6: S3.6 U13.1 U13.2 | length 1524
  Top Layer w6.25: U13.2@1230.38,817.42 1229.75,816.78 1226.16,816.78 1166.88,757.51 1166.88,457.49 1279.75,344.63 1530.03,344.63 1537.72,336.94 1599.21,336.94 1620.82,315.33 1620.82,311.23 1642.43,289.63 1692.99,289.63 1743.49,340.13 1779.98,340.13 1801.54,361.69 1860.2,361.69 1870.7,351.19 1912.33,351.19 1959.13,397.99 1959.13,538.31 1930.32,567.12 S3.6@1930.32,578.93 ; U13.2@1254.14,818.6 U13.1@1254.14,843.6
NetS4_3: S4.3 U13.15 U13.16 | length 625.3
  Top Layer w6.25: U13.16@1468.7,843.6 U13.15@1468.7,818.6 1505.92,818.6 1535.21,789.31 1535.21,753.94 1535.33,753.82 1535.33,738.8 1535.21,738.68 1535.21,688.31 1583.11,640.41 1679.23,640.41 1727.13,592.51 1727.13,572.24 1715.83,560.94 1715.83,505.59 1655.32,445.08 S4.3@1655.32,433.26
NetS4_6: S4.6 U13.10 U13.11 | length 421.8
  Top Layer w6.25: U13.10@1468.7,693.6 1512,693.6 1513.56,692.04 ; U13.11@1468.7,718.6 1503.97,718.6 1513.56,709.01 1513.56,692.04 ; S4.6@1660.01,574.24 S4.6@1655.32,578.93 1655.32,544.02 1649.61,538.31 1641.7,538.31 1562.96,538.31 1546.33,554.94 1546.33,636.64 1513.56,669.41 1513.56,692.04
NetU2:A_40: U2:A.40 U2:A.41 | length 118.3
  Bottom w6.25: U2:A.41@508.34,1354.13 508.34,1401.1 514.48,1407.24 521.15,1407.24 528.02,1400.36 U2:A.40@528.02,1354.13
NetU2:A_62: U2:A.62 U4:A.2 | length 250.6
  Top Layer w6.25: U4:A.2@409.87,1616.61 456.16,1616.61 457.46,1615.31 v1(466.21,1615.31)
  Bottom w6.25: U2:A.62@299.68,1680.9 353.95,1680.9 419.54,1615.31 v1(466.21,1615.31)
NetU2:A_63: U2:A.63 U4:A.1 | length 237.8
  Top Layer w6.25: U4:A.1@409.87,1666.61 425.5,1666.61 441.21,1682.31 v1(460.21,1682.31)
  Bottom w6.25: U2:A.63@299.68,1700.59 359.14,1700.59 392.96,1666.77 444.66,1666.77 v1(460.21,1682.31)
P0_25MHZ_CLK: R30.2 R38.2 | length 389.7
  Signal Layer 3 w6.25: v1@2910.21,593.31 3003.57,593.31 3033.7,563.19 3179.82,563.19 3183.95,567.31 v1(3188.21,567.31)
  Bottom w6.25: R30.2@2863.71,552.2 2863.71,553.19 2900.82,590.3 2907.19,590.3 v1@2910.21,593.31 ; R38.2@3185.64,535 3188.21,537.57 v1(3188.21,567.31)
  other v1: 2911.21,593.31
P0_PHY_CLK: R29.2 R30.1 TP4.1 U19.23 | length 2561.1
  Top Layer w6.25: v1(2502.21,2213.31) 2557.83,2157.69 2573.47,2157.69 2582.09,2149.06 2600.02,2149.06 2635.16,2113.93 2635.16,2112.02 2640.8,2106.38 U19.23@2640.8,2099.49 ; R29.2@2864.71,615.2 TP4.1@2864.71,693.7
  Signal Layer 7 w6.25: v1(2502.21,2213.31) 2578.27,2289.38 2804.14,2289.38 2894.88,2198.63 2894.88,2182.49 2895.21,2182.17 2895.21,2151.31 2910.21,2136.31 2988.21,2136.31 3012.21,2112.31 3012.21,1883.31 3029.21,1866.31 3029.21,1759.31 3063.21,1725.31 3063.21,1667.68 2991.34,1595.81 2971.07,1595.81 2901.08,1525.82 2901.08,1458.8 2924.13,1435.75 2924.13,1384.87 2908.08,1368.82 2908.08,1287.55 2856.08,1235.55 2856.08,1101.93 2864.58,1093.43 2864.58,959.8 2851.08,946.3 2851.08,827.04 2863.71,814.41 TP4.1@2863.71,693.7
  Bottom w6.25: R30.1@2863.71,615.2 TP4.1@2863.71,693.7
P0_RD_N: J5.8 R126.1 U19.9 | length 461.9
  Top Layer w6: U19.9@2784.5,1936.1 2791.39,1936.1 2795.23,1939.95 2802.49,1939.95 2806.01,1936.43 2806.01,1923.12 2851.59,1877.54 3030.21,1877.54 ; R126.1@3028.63,1845 3030.21,1846.58 3030.21,1877.54 ; J5.8@3172.83,1865.16 3092.15,1865.16 3079.77,1877.54 3030.21,1877.54
P0_RD_P: J5.7 R125.1 U19.10 | length 454.8
  Top Layer w6: U19.10@2784.5,1955.79 2791.39,1955.79 2795.23,1951.95 2807.47,1951.95 2818.01,1941.4 2818.01,1928.09 2856.56,1889.54 3031.21,1889.54 ; R125.1@3028.63,1915 3031.21,1912.42 3031.21,1889.54 ; J5.7@3170.84,1903.62 3092.29,1903.62 3092.29,1902.06 3079.77,1889.54 3031.21,1889.54
P0_TD_N: J5.4 R119.1 U19.11 | length 448.3
  Top Layer w6: U19.11@2784.5,1975.47 2791.39,1975.47 2795.23,1979.32 2806.76,1979.32 2838.3,2010.86 2838.3,2012.2 2864.27,2038.17 3029.21,2038.17 ; R119.1@3028.63,2010 3029.21,2010.58 3029.21,2038.17 ; J5.4@3170.84,2024.09 3092.29,2024.09 3092.29,2025.65 3079.77,2038.17 3029.21,2038.17
P0_TD_P: J5.3 R118.1 U19.12 | length 449
  Top Layer w6: U19.12@2784.5,1995.16 2791.39,1995.16 2795.23,1991.32 2801.79,1991.32 2826.3,2015.83 2826.3,2017.17 2859.3,2050.17 3029.21,2050.17 ; R118.1@3028.63,2080 3029.21,2079.42 3029.21,2050.17 ; J5.3@3170.84,2064.25 3093.85,2064.25 3079.77,2050.17 3029.21,2050.17
P1_25MHZ_CLK: R34.2 R40.2 | length 503.4
  Signal Layer 3 w6.25: v1(3141.21,581.31) 3168.53,581.31 3172.65,585.44 3195.71,585.44 3244.94,536.22 3244.94,510.58 3262.21,493.31 3262.21,454.31 v1(3261.18,453.28)
  Bottom w6.25: R34.2@2955.01,553.5 2955.01,554.49 2970.59,570.06 2992.43,570.06 3003.68,581.31 v1(3141.21,581.31) ; R40.2@3185.32,425 3185.32,426.97 3211.64,453.28 v1(3261.18,453.28)
P1_PHY_CLK: R33.2 R34.1 TP5.1 U21.23 | length 1014.3
  Top Layer w6.25: v1(2562.21,1221.31) 2599.9,1221.31 2631.22,1189.99 2631.22,1188.08 2636.86,1182.44 U21.23@2636.86,1175.55 ; R33.2@2956.01,616.5 TP5.1@2956,695
  Bottom w6.25: v1(2562.21,1221.31) 2562.21,1217.05 2554.08,1208.93 2554.08,1141.81 2679.04,1016.85 2786.3,1016.85 2851.08,952.07 2851.08,798.93 2955.01,695 R34.1@2955.01,616.5
P1_RD_N: J6.8 R150.1 U21.9 | length 485.6
  Top Layer w6: U21.9@2780.56,1012.17 2787.45,1012.17 2791.29,1016.01 2805.03,1016.01 2827.37,993.66 2827.37,976.76 2855.3,948.83 3029.21,948.83 ; R150.1@3027.76,910.75 3029.21,912.2 3029.21,948.83 ; J6.8@3172.83,911.88 3094.22,911.88 3079.91,926.19 3061.61,926.19 3058.1,929.7 3038.97,948.83 3029.21,948.83
P1_RD_P: J6.7 R149.1 U21.10 | length 476.1
  Top Layer w6: U21.10@2780.56,1031.85 2787.45,1031.85 2791.29,1028.01 2810,1028.01 2839.37,998.63 2839.37,981.73 2860.27,960.83 3028.21,960.83 ; R149.1@3028.63,990 3028.21,989.58 3028.21,960.83 ; J6.7@3172.83,952.04 3093.94,952.04 3080.09,938.19 3066.59,938.19 3043.94,960.83 3028.21,960.83
P1_TD_N: J6.4 R140.1 U21.11 | length 457
  Top Layer w6: U21.11@2780.56,1051.54 2787.45,1051.54 2791.29,1055.38 2802.83,1055.38 2831.98,1084.53 2831.98,1085.88 2855.56,1109.46 3028.21,1109.46 ; R140.1@3028.63,1085 3028.21,1085.42 3028.21,1109.46 ; J6.4@3172.83,1072.51 3095.19,1072.51 3080.8,1086.9 3067.06,1086.9 3044.5,1109.46 3028.21,1109.46
P1_TD_P: J6.3 R139.1 U21.12 | length 379.6
  Top Layer w6: U21.12@2780.56,1071.22 2787.45,1071.22 2791.29,1067.38 2797.86,1067.38 2819.98,1089.5 2819.98,1090.85 2850.59,1121.46 3029.21,1121.46 ; R139.1@3028.63,1155 3029.21,1154.42 3029.21,1121.46 ; J6.3@3088.7,1107.4 3080.2,1098.9 3072.03,1098.9 3049.47,1121.46 3029.21,1121.46
RD_N: J4.8 R111.1 U17.9 | length 535.9
  Bottom w6: U17.9@2785.56,1694.96 2792.45,1694.96 2796.29,1691.12 2810.03,1691.12 2829.18,1710.28 2829.18,1725.05 2853.92,1749.79 3029.21,1749.79 ; R111.1@3030.01,1775 3029.21,1774.2 3029.21,1749.79 ; J4.8@3092.29,1762.31 3092.29,1763.87 J4.8@3170.84,1763.87 ; J4.8@3172.83,1757.96 3094.86,1757.96 3080.6,1743.7 3069.57,1743.7 3063.48,1749.79 3029.21,1749.79
RD_P: J4.7 R110.1 U17.10 | length 447.9
  Bottom w6: U17.10@2785.56,1675.28 2792.45,1675.28 2796.29,1679.12 2815,1679.12 2841.18,1705.31 2841.18,1720.08 2858.89,1737.79 3029.21,1737.79 ; R110.1@3028.63,1710 3029.21,1710.58 3029.21,1737.79 ; J4.7@3086,1726.3 3080.6,1731.7 3064.6,1731.7 3058.51,1737.79 3029.21,1737.79 ; J4.7@3092.29,1725.26 3092.29,1723.71 J4.7@3170.84,1723.71
TD_N: J4.4 R108.1 U17.11 | length 449.7
  Bottom w6: U17.11@2785.56,1655.59 2792.45,1655.59 2796.29,1651.75 2807.83,1651.75 2837.67,1621.9 2837.67,1613.43 2861.94,1589.16 3029.21,1589.16 ; R108.1@3028.63,1620 3029.21,1619.42 3029.21,1589.16 ; J4.4@3086.5,1589.3 3086.5,1589.2 3080.5,1583.2 3061.47,1583.2 3055.51,1589.16 3029.21,1589.16 ; J4.4@3092.29,1601.68 3092.29,1603.24 J4.4@3170.84,1603.24
TD_P: J4.3 R107.1 U17.12 | length 447.5
  Bottom w6: U17.12@2785.56,1635.91 2792.45,1635.91 2796.29,1639.75 2802.86,1639.75 2825.67,1616.93 2825.67,1608.46 2856.97,1577.16 3030.21,1577.16 ; R107.1@3030.01,1550 3030.21,1550.2 3030.21,1577.16 ; J4.3@3086.5,1563.4 3086.5,1565.2 3080.5,1571.2 3056.5,1571.2 3050.54,1577.16 3030.21,1577.16 ; J4.3@3092.29,1564.63 3092.29,1563.08 J4.3@3170.84,1563.08
USB-EPEN: Q1.3 R99.2 R105.1 U15.4 | length 466.6
  Signal Layer 4 w6.25: v1(1620.01,1697) 1620.01,1773 v1(1743.01,1896)
  Bottom w6.25: R99.2@1620.01,1650 v1(1620.01,1697) ; Q1.3@1670.01,1775.59 1676.73,1782.31 1676.73,1806.21 1700.52,1830 R105.1@1701.51,1830 1711.37,1839.86 U15.4@1711.37,1895.87 1711.5,1896 v1(1743.01,1896)
USB-ID: J3.4 Q1.1 R101.2 R104.2 U16.3 | length 929
  Top Layer w6.25: v1@1741.21,2092.31 1745.86,2096.97 1789.2,2096.97 1790.01,2097.78 U16.3@1790.01,2098.62 ; J3.4@1860.55,2207.75 1860.78,2207.52 1860.78,2155.23 v1(1861.01,2155)
  Signal Layer 4 w6.25: v1(1741.21,2095.31) 1741.21,2131.68 1750.76,2141.23 1750.76,2146.38 1781.5,2177.13 1838.88,2177.13 v1(1861.01,2155)
  Signal Layer 8 w6.25: v1(1718.01,1697) 1718.01,1697.06 1703.63,1711.44 1703.63,1927.99 1719.58,1943.94 1719.58,2073.69 v1(1741.21,2095.31)
  Bottom w6.25: Q1.1@1689.69,1724.41 1689.69,1722.44 1715.14,1697 1720.01,1697 1718.01,1695 1718.01,1652 R101.2@1720.01,1650 ; v1(1861.01,2155) 1881.01,2135 1905.64,2135 1920,2149.36 1920,2161.5 R104.2@1948.5,2190
USB-PFLT: R97.2 R103.2 U15.3 | length 307.5
  Top Layer w6.25: R97.2@1702.51,2023.66 1723.08,2044.23 1723.08,2134.93 1732.21,2144.05 v1(1732.21,2148.31)
  Bottom w6.25: U15.3@1711.37,2004.13 1705.59,2009.92 1705.59,2052.93 R103.2@1690.01,2068.5 1690.01,2069.49 1717.84,2097.31 1717.84,2133.87 1732.21,2148.24 v1(1732.21,2148.31)
USB_5V0: C84.1 C85.1 R82.2 R102.1 R103.1 U15.5 | length 366.3
  Bottom w12: R102.1@1546.15,1937.99 1548.58,1940.42 1613.21,1940.42 v1(1613.21,1962.31) ; v1(1547.01,1672) 1547.01,1731.02 C85.1@1548.79,1732.8 ; C84.1@1548.79,1837.8 1559.58,1827 v1(1596.01,1827) ; 1613.21,1939.89 1621.69,1931.41 1621.69,1918.61 1636.56,1903.74 U15.5@1636.56,1895.87 ; v1(1670.21,2170.31) 1670.21,2167.61 1677.31,2160.5 1677.31,2144.2 R103.1@1690.01,2131.5 ; R82.2@3992.17,1052.9 4005.01,1065.73 v1(4005.01,1110)
USB_N: J3.2 R95.2 U16.2 | length 166.9
  Top Layer w6.1: J3.2@1809.41,2208.19 1809.41,2177.97 1816.15,2171.23 1816.15,2137.15 v1(1804.01,2125) 1809.69,2119.32 U16.2@1809.69,2098.62
  Bottom w6.1: R95.2@1790.01,2083.62 1790.01,2087.01 1804.01,2101.01 v1(1804.01,2125)
USB_P: J3.3 R96.2 U16.1 | length 165.4
  Top Layer w6.1: U16.1@1829.38,2097.64 1829.38,2117.37 v1(1837.01,2125) 1828.25,2133.75 1828.25,2171.23 1835,2177.97 J3.3@1835,2208.19
  Top Layer w7: U16.1@1829.38,2097.64 U16.1@1829.82,2098.07
  Bottom w6.1: v1(1837.01,2125) 1837.01,2091.62 R96.2@1845.01,2083.62
VDD_1V2: C54.1 C55.1 C56.1 C57.1 C58.1 C59.1 C60.1 C82.1 EC1.118 L5.2 R94.2 TP9.1 U1.E9 U1.E11 U1.F9 U1.F11 U1.G14 U1.G15 U1.J14 U1.J15 U1.K5 U1.K6 U1.P10 U1.P13 U1.R10 U1.R13 U4.3 | length 1575.1
  Top Layer w10: v2(1688.19,1071.85) U1.K5@1703.94,1056.1 ; v2(1719.69,1071.85) U1.K6@1735.44,1056.1 ; v2(1814.18,1197.83) U1.F9@1829.92,1182.08 ; v2(1814.18,1229.33) U1.E9@1829.92,1213.58 ; v2(1845.67,882.87) U1.R10@1861.42,898.62 ; v2(1845.67,914.37) U1.P10@1861.42,930.12 ; U1.F11@1892.92,1182.08 v2(1908.66,1197.83) ; U1.E11@1892.92,1213.58 v2(1908.66,1229.33) ; U1.R13@1955.91,898.62 v2(1971.66,882.87) ; U1.P13@1955.91,930.12 v2(1971.66,914.37) ; U1.J14@1987.4,1087.6 v2(2003.15,1103.34) ; U1.G14@1987.4,1150.59 v2(2003.15,1166.34) ; U1.J15@2018.9,1087.6 v2(2034.65,1103.34) ; U1.G15@2018.9,1150.59 v2(2034.65,1166.34)
  Top Layer w12: v1(2215.75,1245.74) 2249.24,1245.74 C82.1@2265,1261.5 ; U4.3@2290.88,1867.6 2291.44,1867.03 2291.44,1834.57 v1(2292.01,1834) ; L5.2@2380.01,1255 2385.01,1250 v1(2385.01,1211)
  Signal Layer 3 w12: v1(1939.9,671.5) 1939.9,521.5 2082.5,378.9 v1(2177,378.9)
  Bottom w12: C54.1@1664.57,1040.35 1668.51,1040.35 1687.04,1058.89 1687.04,1070.7 v2(1688.19,1071.85) ; v2(1814.18,1197.83) 1815.32,1196.68 1815.32,1172.15 1821.13,1166.34 C58.1@1822.05,1166.34 ; v2(1845.67,882.87) 1847.3,882.87 1861.17,869 1871.36,869 C56.1@1877.17,863.19 C56.1@1877.17,859.25 ; C59.1@1877.17,1221.45 1877.17,1222.37 1882.98,1228.18 1907.52,1228.18 v2(1908.66,1229.33) ; C55.1@1963.78,1087.6 1963.78,1089.6 1969.59,1095.41 1993.59,1095.41 2001.53,1103.34 v2(2003.15,1103.34) ; v2(1971.66,914.37) C57.1@1971.66,945.86 ; C60.1@1971.66,1040.35 1971.83,1040.18 2002.98,1040.18 v2(2003.15,1040) ; v1(2177,378.9) 2177,341.1 2282.49,235.61 EC1.118@2282.49,91 ; R94.2@2229,1394.38 2274.39,1394.38 TP9.1@2300.01,1420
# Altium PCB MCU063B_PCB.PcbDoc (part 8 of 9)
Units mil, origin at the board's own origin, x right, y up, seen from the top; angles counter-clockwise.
Board outline 4165.01 x 2371.03 mil, 10 copper layers (Top Layer, Internal Plane 2, Signal Layer 3, Signal Layer 4, Internal Plane 5, Internal Plane 6, Signal Layer 7, Signal Layer 8, Internal Plane 9, Bottom), stack 59.9 mil thick; 440 components, 394 nets, 1760 pads, 1251 vias.

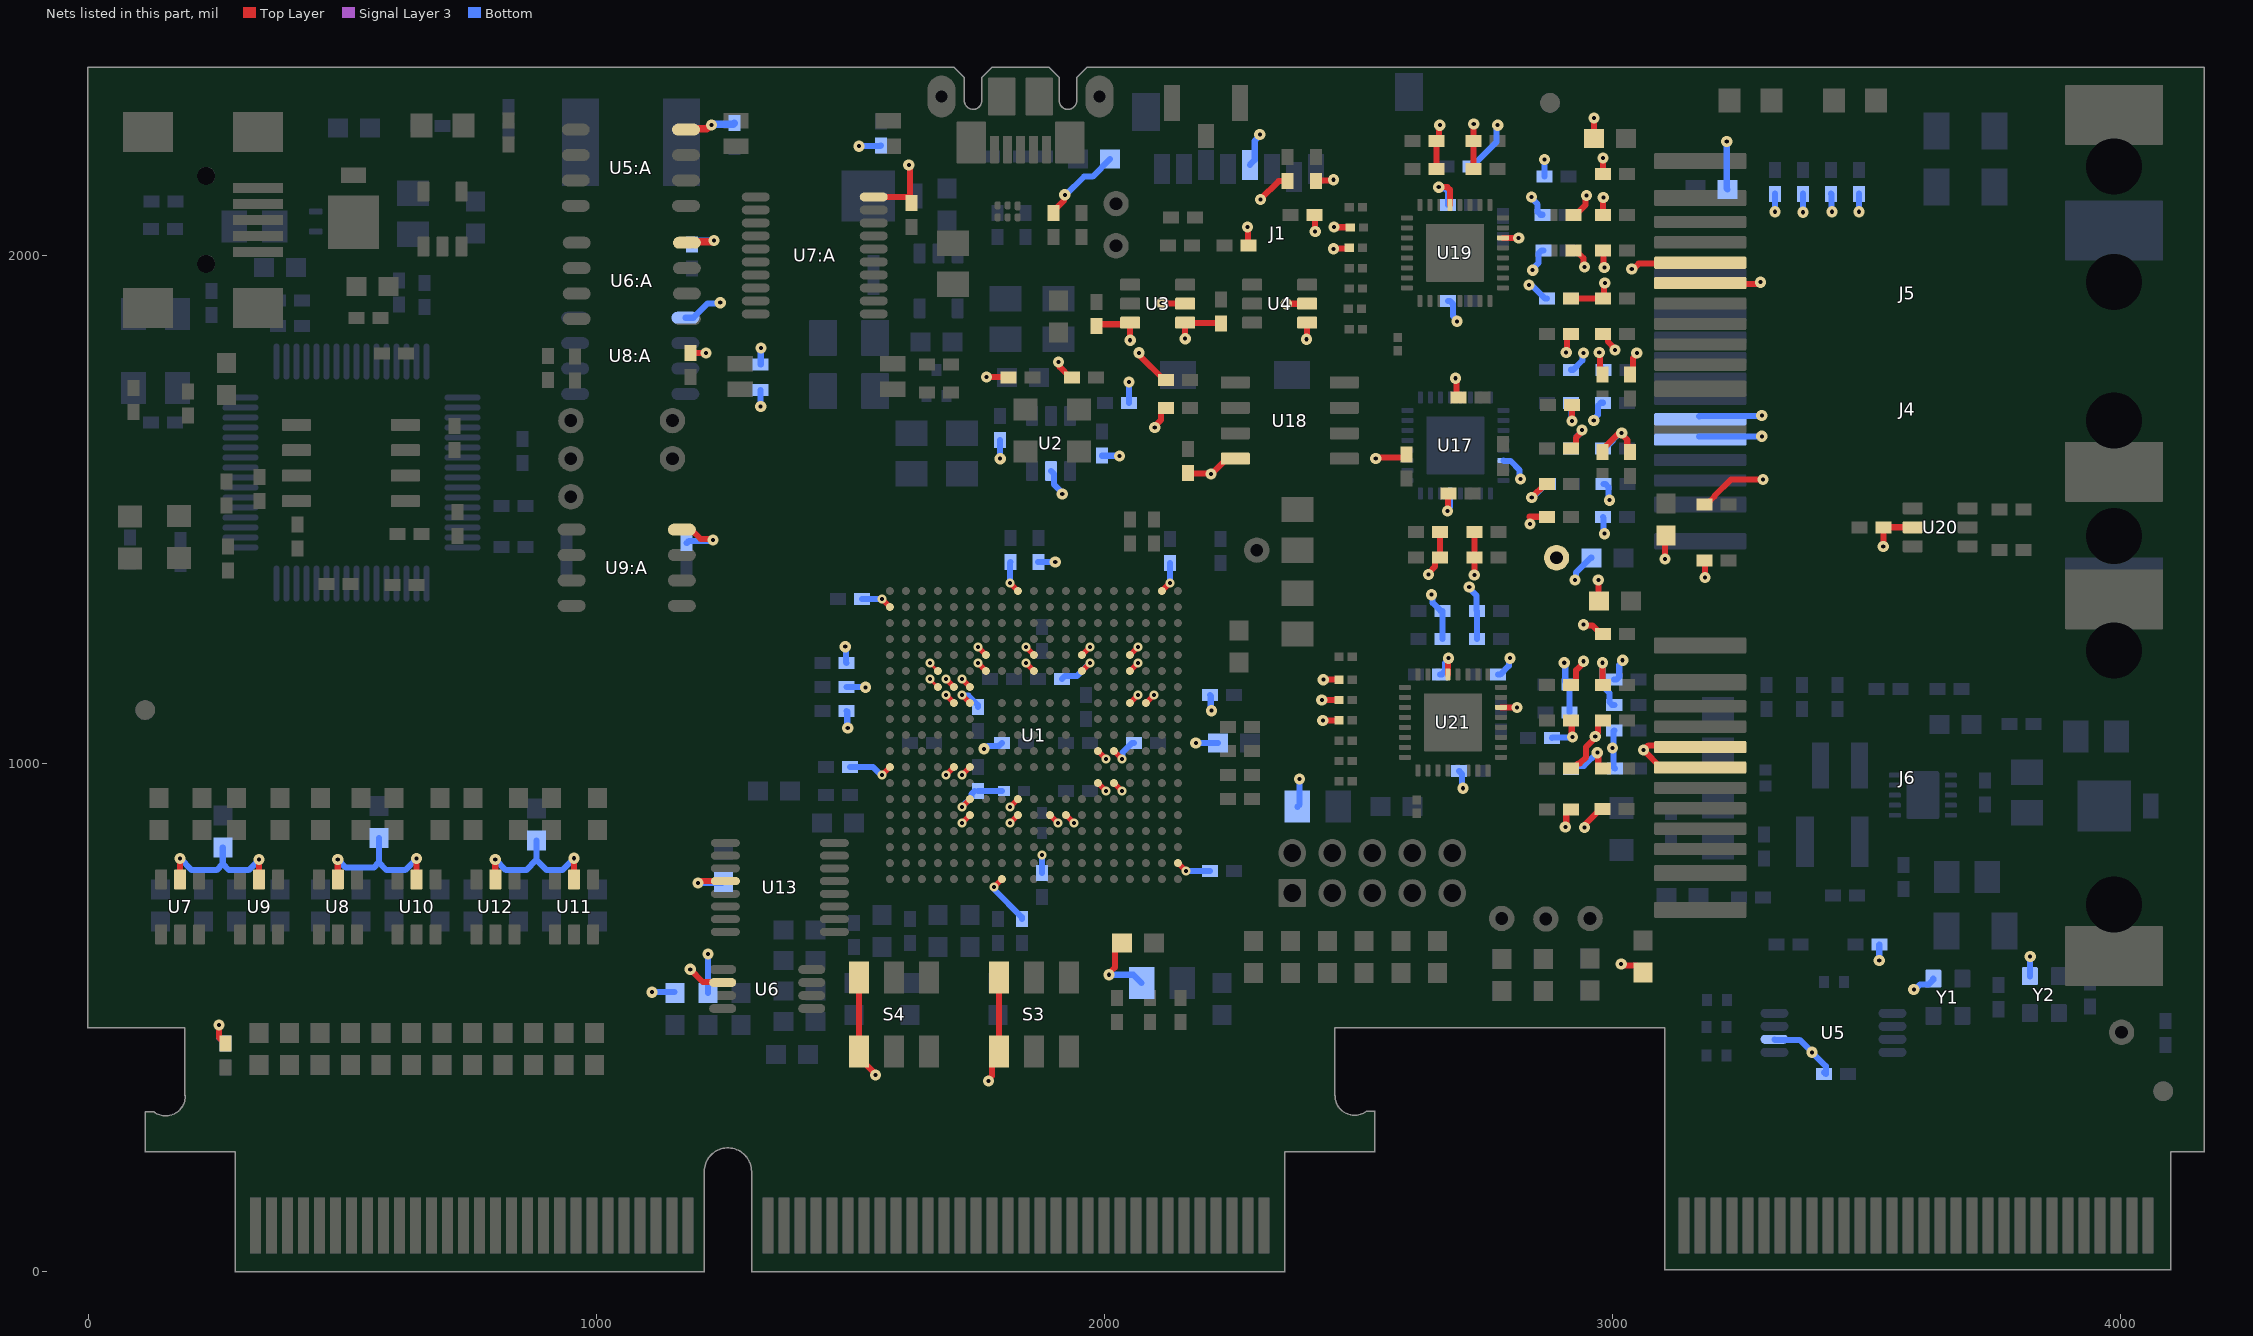
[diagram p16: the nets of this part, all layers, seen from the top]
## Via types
v1: diameter 22, hole 8, Top Layer to Bottom, tented both sides, 895 vias
v2: diameter 18, hole 8, Top Layer to Bottom, tented both sides, 334 vias
v3: diameter 19.68, hole 7.87, Top Layer to Bottom, tented both sides, 19 vias
v4: diameter 18, hole 7.87, Top Layer to Bottom, tented both sides, 1 vias
v5: diameter 18/18/18/18/18/18 (per signal layer), hole 8, Top Layer to Bottom, tented both sides, 1 vias
v6: diameter 22/22/22/22/22/22 (per signal layer), hole 8, Top Layer to Bottom, tented both sides, 1 vias

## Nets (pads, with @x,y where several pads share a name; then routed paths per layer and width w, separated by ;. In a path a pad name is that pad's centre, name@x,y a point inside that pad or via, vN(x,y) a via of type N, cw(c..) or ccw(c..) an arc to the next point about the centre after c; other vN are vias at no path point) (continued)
VDD_3V3: C1.1 C2.1 C4.1 C6.1 C7.1 C21:A.1 C23:A.1 C24:A.2 C26:A.1 C28:A.1 C53.2 C65.1 C66.1 C67.1 C68.1 C69.1 C70.1 C71.1 C72.1 C73.1 C74.1 C75.1 C76.1 C77.1 C78.1 C79.1 C80.1 C87.1 C88.1 C89.1 C90.1 C91.1 C92.1 C93.1 C94.1 C95.1 C96.1 C97.2 C98.2 C99.2 C100.2 C101.1 C102.1 C104.1 C105.1 C106.1 C107.1 C108.1 C109.1 C110.1 C111.1 C112.1 C113.1 C114.2 C115.1 C116.2 C117.2 C118.2 C119.1 C120.1 C122.1 C123.1 C124.1 C125.1 C126.1 C127.1 C128.1 C129.1 C130.1 C131.1 C132.2 C133.2 C134.1 C135.2 C136.2 C137.1 C138.1 J1.4 J4.5 J4.6 J5.5 J5.6 J6.5 J6.6 L3.2 R1.2 R2.1 R9.1 R10.1 R11.2 R12.2 R13.2 R14.2 R15:A.2 R20.2 R26.2 R31.1 R32.2 R44.1 R104.1 R107.2 R108.2 R110.2 R111.2 R112.1 R113.2 R114.2 R115.2 R116.1 R117.1 R118.2 R119.2 R120.2 R121.2 R122.2 R123.2 R125.2 R126.2 R127.1 R128.2 R129.1 R130.1 R137.2 R138.1 R139.2 R140.2 R141.2 R142.1 R145.2 R146.2 R147.2 R149.2 R150.2 R151.2 R152.1 R153.1 R154.1 R160.2 R161.1 TP8.1 U1.A9 U1.A18 U1.B1 U1.E7 U1.E10 U1.E13 U1.E16 U1.F4 U1.F7 U1.F10 U1.F13 U1.F16 U1.G4 U1.G5 U1.G6 U1.H5 U1.H6 U1.H16 U1.H17 U1.L14 U1.L15 U1.M1 U1.M5 U1.M6 U1.N14 U1.N15 U1.P9 U1.R9 U1.R11 U1.R12 U1.V19 U1.W8 U2.5 U3.3 U3.4 U3.5 U4.4 U4.5 U5.6 U5:A.8 U6:A.8 U7:A.20 U8:A.1 U9:A.8 U17.14 U17.21 U18.8 U19.14 U19.21 U20.5 U21.14 U21.21 Y1.4 Y2.4 | length 8904.9
  Top Layer w6.25: v2(1656.7,1166.34) U1.G4@1672.44,1150.59 ; v2(1656.7,1197.83) U1.F4@1672.44,1182.08
  Top Layer w10: v2(1562.21,977.36) U1.M1@1577.96,993.11 ; v2(1562.21,1323.82) U1.B1@1577.96,1308.07 ; v2(1688.19,977.36) U1.M5@1703.94,993.11 ; v2(1688.19,1134.84) U1.H5@1703.94,1119.09 ; v2(1688.19,1166.34) U1.G5@1703.94,1150.59 ; v2(1719.69,977.36) U1.M6@1735.44,993.11 ; v2(1719.69,1134.84) U1.H6@1735.44,1119.09 ; v2(1719.69,1166.34) U1.G6@1735.44,1150.59 ; v2(1751.18,1197.83) U1.F7@1766.93,1182.08 ; v2(1751.18,1229.33) U1.E7@1766.93,1213.58 ; v2(1782.68,756.89) U1.W8@1798.43,772.63 ; v2(1814.18,882.87) U1.R9@1829.92,898.62 ; v2(1814.18,914.37) U1.P9@1829.92,930.12 ; v2(1814.18,1355.31) U1.A9@1829.92,1339.56 ; v2(1845.67,1197.83) U1.F10@1861.42,1182.08 ; v2(1845.67,1229.33) U1.E10@1861.42,1213.58 ; U1.R11@1892.92,898.62 v2(1908.66,882.87) ; U1.R12@1924.41,898.62 v2(1940.16,882.87) ; U1.F13@1955.91,1182.08 v2(1971.66,1197.83) ; U1.E13@1955.91,1213.58 v2(1971.66,1229.33) ; U1.N14@1987.4,961.61 v2(2003.15,945.86) ; U1.L14@1987.4,1024.6 v2(2003.15,1008.86) ; U1.N15@2018.9,961.61 v2(2034.65,945.86) ; U1.L15@2018.9,1024.6 v2(2034.65,1008.86) ; U1.H16@2050.4,1119.09 v2(2066.14,1134.84) ; U1.F16@2050.4,1182.08 v2(2066.14,1197.83) ; U1.E16@2050.4,1213.58 v2(2066.14,1229.33) ; U1.H17@2081.89,1119.09 v2(2097.64,1134.84) ; U1.V19@2144.88,804.13 v2(2160.63,788.38)
  Top Layer w12: v1(257.21,485.31) 257.21,461.42 R1.2@270.01,448.62 ; U9:A.8@1168.51,1460.32 1187.34,1460.32 1205.75,1441.91 1228.1,1441.91 v1(1230.01,1440) ; C26:A.1@1185.03,1808.47 1185.26,1808.24 1215.77,1808.24 v1(1216.01,1808) ; U7:A.20@1546.15,2115.16 1612.41,2115.16 C24:A.2@1617.12,2110.45 ; v1(1615.21,2178.31) 1617.12,2176.4 C24:A.2@1617.12,2110.45 ; v1(1768.01,1761) 1768.51,1760.5 1810.89,1760.5 R9.1@1811.39,1760 ; R26.2@1900.01,2083.62 1900.01,2087.56 1920.29,2107.84 1920.29,2117.4 v1(1922.21,2119.31) ; v1(1910.01,1790) 1911.92,1788.09 1911.92,1780.53 1932.45,1760 R10.1@1936.39,1760 ; C4.1@1985.01,1861.38 1988.12,1864.49 2047.77,1864.49 U3.3@2050.88,1867.6 v1(2050.88,1833.13) ; v1(2068.21,1808.31) 2070.12,1806.4 2070.12,1802.33 2117.45,1755 R120.2@2121.39,1755 ; v1(2099.21,1661.31) 2099.21,1664.02 2111.64,1676.45 2111.64,1694.19 2117.45,1700 R121.2@2121.39,1700 ; v1(2113.01,1906) 2113.51,1905.5 2158.64,1905.5 U3.5@2159.14,1905 ; U1.A18@2113.39,1339.56 v2(2129.14,1355.31) ; v1(2159.14,1836.13) U3.4@2159.14,1867.6 2159.75,1866.99 2229.4,1866.99 C6.1@2230.01,1866.38 ; C115.1@2165.01,1571.38 2165.7,1570.69 2209.32,1570.69 v1(2210.01,1570) 2210.99,1570 2240.99,1600 U18.8@2257.73,1600 ; v1(2282.01,2056) 2282.82,2055.19 2282.82,2020.81 R20.2@2283.63,2020 ; v1(2307.21,2110.31) 2343.27,2146.38 R13.2@2360.01,2146.38 R13.2@2360.01,2142.44 ; v1(2358.01,1905) U4.5@2399.14,1905 ; v1(2398.01,1835) 2398.58,1835.57 2398.58,1867.03 U4.4@2399.14,1867.6 ; C2.1@2413.63,2080 2414.32,2079.31 2414.32,2047.69 v1(2415.01,2047) ; R14.2@2416.26,2146.69 2417.42,2147.85 2449.85,2147.85 v1(2451.01,2149) ; v1(2428.01,1125) R147.2@2462.02,1125 ; v1(2430.01,1085) R146.2@2462.02,1085 ; v1(2431.01,1165) R145.2@2462.02,1165 ; v1(2451.01,2013) 2452.01,2014 2481.02,2014 R122.2@2482.02,2015 ; v1(2452.01,2056) 2452.51,2055.5 2483.53,2055.5 R123.2@2484.03,2055 ; v1(2534.21,1600.31) 2536.12,1602.23 2589.2,1602.23 2595.01,1608.04 R114.2@2595.01,1608.62 ; v1(2638.21,1372.31) 2638.21,1375.02 2651.08,1387.89 2651.08,1399.5 2656.89,1405.31 C91.1@2660.83,1405.31 C94.1@2660.83,1455.31 ; C111.1@2653.63,2170 C108.1@2653.63,2225 2658.29,2229.66 2658.29,2254.4 v1(2660.21,2256.31) ; v1(2658.21,2134.31) 2675.21,2134.31 2680.17,2129.35 U19.21@2680.17,2099.49 ; v1(2675.21,1497.31) 2676.25,1498.35 2676.25,1530.53 R112.1@2677.29,1531.57 ; U21.21@2676.23,1175.55 2676.72,1176.04 2676.72,1206.82 v1(2677.21,1207.31) ; v1(2691.21,1758.31) 2693.12,1756.4 2693.12,1724.41 R113.2@2696.98,1720.55 ; C109.1@2726.39,2170 C110.1@2726.39,2225 2726.7,2225.31 2726.7,2258.69 v1(2727.01,2259) ; v1(2728.21,1371.31) 2728.4,1371.5 2728.4,1405.12 C93.1@2728.58,1405.31 C92.1@2728.58,1455.31 ; U21.14@2780.56,1110.59 2780.7,1110.45 2812.07,1110.45 v1(2812.21,1110.31) ; U19.14@2784.5,2034.53 v1(2815.48,2034.53) ; v1(2837.5,1471.4) 2837.5,1485.02 2836.86,1485.66 2870.73,1485.66 C90.1@2871.39,1485 ; v1(2841.21,1523.31) 2841.21,1523.76 2867.45,1550 C87.1@2871.39,1550 ; v1(2907.21,875.31) 2909.12,877.23 2909.12,904.19 2914.93,910 C138.1@2918.63,910 ; v1(2909.01,1809) 2910.92,1810.91 2910.92,1839.19 2916.73,1845 C120.1@2918.63,1845 ; C137.1@2918.63,990 2922.57,990 2932.88,1000.31 2935.91,1000.31 2948.21,1012.61 2948.21,1032.61 2966.21,1050.61 v1(2966.21,1053.31) 2966.21,1056.02 2971.64,1061.45 2971.64,1079.19 2977.45,1085 R140.2@2981.39,1085 ; C131.1@2918.63,1085 2919.92,1083.71 2919.92,1053.6 v1(2921.21,1052.31) ; C130.1@2918.63,1155 2922.57,1155 2928.38,1160.81 2928.38,1183.78 2943.21,1198.61 v1(2943.21,1201.31) ; C88.1@2918.63,1620 2922.57,1620 2928.38,1625.81 2928.38,1641.78 2940.21,1653.61 v1(2940.21,1656.31) ; C119.1@2918.63,1915 R125.2@2981.39,1915 2983.2,1916.81 2983.2,1944.19 v1(2985.01,1946) ; v1(2920.21,1674.31) 2920.52,1674.62 2920.52,1705 C89.1@2920.83,1705.31 ; C113.1@2923.63,2010 2927.57,2010 2943.1,1994.47 2943.1,1978.91 v1(2945.01,1977) ; C112.1@2923.63,2080 2927.57,2080 2947.1,2099.53 2947.1,2116.09 v1(2949.01,2118) ; v1(2943.21,1273.31) 2945.12,1271.4 2961.05,1271.4 2977.45,1255 R160.2@2981.39,1255 ; v1(2945.21,874.31) 2947.12,876.23 2947.12,881.3 2976.58,910.75 R150.2@2980.52,910.75 ; R138.1@2963.51,2230 v1(2963.51,2270.5) ; v1(2970.21,1021.31) 2972.12,1019.4 2972.12,995.81 2977.93,990 R149.2@2981.39,990 ; v1(2972.21,1361.31) 2972.21,1321.31 R161.1@2973.51,1320 ; v1(2974.01,1809) 2975.92,1807.09 2975.92,1769.36 C100.2@2980.01,1765.28 ; C98.2@2980.01,1613.62 2980.01,1617.56 3011.35,1648.9 3016.29,1648.9 v1(3018.21,1650.81) 3018.21,1648.11 3029.2,1637.11 3029.2,1619.43 C99.2@3035.01,1613.62 ; v1(2980.21,1198.31) 2980.8,1197.72 2980.8,1155.59 R139.2@2981.39,1155 ; R126.2@2981.39,1845 2985.32,1845 2991.14,1839.19 2991.14,1830.58 3005.01,1816.71 v1(3005.01,1814) ; R119.2@2981.39,2010 2982.7,2008.69 2982.7,1977.31 v1(2984.01,1976) ; R118.2@2981.39,2080 2981.7,2080.31 2981.7,2113.69 v1(2982.01,2114) ; R137.2@2981.39,2160 v1(2981.39,2191.62) ; v1(3017.21,605.31) 3019.91,605.31 3023.04,602.19 3047.31,602.19 3060.01,589.49 R153.1@3060.01,588.5 ; C97.2@3035.01,1765.28 3040.82,1771.09 3040.82,1798.11 3048.01,1805.29 v1(3048.01,1808) ; v1(3038.01,1973) 3040.72,1973 3051.65,1983.93 J5.5@3170.84,1983.93 ; v1(3103.21,1402.31) 3103.21,1446.7 R129.1@3105.01,1448.5 ; J6.5@3166.28,1035.8 3070.7,1035.8 v1(3061.21,1026.31) 3095.32,992.2 J6.6@3172.83,992.2 ; J5.6@3166.53,1948.09 3170.84,1943.78 3287.67,1943.78 v1(3291.21,1947.31) ; R141.2@3181.39,1400 3181.8,1399.59 3181.8,1366.72 v1(3182.21,1366.31) ; R142.1@3181.39,1510 3185.32,1510 3200.88,1525.56 3200.88,1526.78 3233.41,1559.31 v1(3296.21,1559.31) ; v1(3533.01,1427) 3533.32,1427.31 3533.32,1464.69 C134.1@3533.63,1465 U20.5@3590.88,1465 ; C24:A.2@1617.12,2110.45 1620.01,2107.56 C24:A.2@1620.01,2103.62 1617.12,2106.51 C24:A.2@1617.12,2110.45
  Top Layer w15: U5:A.8@1175.47,2247.63 1177.12,2249.28 1217.58,2249.28 1225.07,2256.77 v1(1226.96,2256.77) ; U6:A.8@1177.29,2025 1178.94,2026.65 1227.41,2026.65 1229.9,2029.13 v1(1231.79,2029.13)
  Bottom w12: v1(257.21,485.31) 257.21,461.42 R2.1@270.01,448.62 ; U8:A.1@1175.34,1877.37 1191.03,1877.37 1218.75,1905.09 1242.1,1905.09 v1(1244.01,1907) ; C28:A.1@1178.04,1433.94 1182.19,1438.09 1228.1,1438.09 v1(1230.01,1440) ; v1(1323.63,1702.62) R31.1@1323.63,1735 ; R32.2@1323.63,1785 1323.82,1785.19 1323.82,1817.81 v1(1324.01,1818) ; v1(1490.01,1230) 1491.42,1228.59 1491.42,1199.25 C74.1@1492.84,1197.83 ; C80.1@1492.84,1103.34 1493.92,1102.26 1493.92,1071.09 v1(1495.01,1070) ; C78.1@1492.84,1150.59 1493.13,1150.29 1529.72,1150.29 v1(1530.01,1150) ; C65.1@1499.21,993.11 1544.84,993.11 1560.58,977.36 v2(1562.21,977.36) ; v1(1517.01,2215) 1517.7,2215.69 1559.32,2215.69 R15:A.2@1560.01,2216.38 ; C71.1@1522.84,1323.82 v2(1562.21,1323.82) ; v2(1719.69,1134.84) 1720.84,1133.69 1732.65,1133.69 1751.18,1115.15 C73.1@1751.18,1111.22 ; v1(1763.01,1029) 1765.72,1029 1771.26,1034.54 1792.62,1034.54 C79.1@1798.43,1040.35 ; v2(1782.68,756.89) 1783.83,755.74 1783.83,751.8 1837.8,697.83 C66.1@1837.8,693.89 ; v1(1795.01,1600) R11.2@1795.01,1636.38 ; v2(1814.18,1355.31) 1814.59,1355.73 1814.59,1395.96 C70.1@1815.01,1396.38 ; C76.1@1870.01,1396.38 v1(1903.39,1396.38) ; C69.1@1877.17,785 v2(1877.17,819.88) ; U2.5@1895.01,1575.87 1900.82,1570.06 1900.82,1549.4 1917.21,1533.02 v1(1917.21,1530.31) ; C75.1@1916.54,1166.34 1922.35,1172.15 1945.97,1172.15 v2(1971.66,1197.83) ; v1(1922.21,2119.31) 1924.31,2119.31 1960,2155 1961.2,2155 1961.51,2155.31 1976.81,2155.31 R104.1@2011.5,2190 ; C1.1@1995.01,1606.38 1995.7,1605.69 2029.32,1605.69 v1(2030.01,1605) ; v2(2034.65,1008.86) 2035.8,1010 2035.8,1021.81 2054.33,1040.35 C68.1@2058.27,1040.35 ; R12.2@2048.63,1710 v1(2048.63,1750.62) ; v2(2129.14,1355.31) C72.1@2129.14,1394.68 ; v2(2160.63,788.38) C67.1@2207.88,788.38 ; v1(2180.01,1040.7) 2223.27,1040.7 C53.2@2223.62,1040.35 ; C77.1@2207.88,1134.84 2209.44,1133.27 2209.44,1105.57 v1(2211.01,1104) ; J1.4@2286.34,2178.19 2296.09,2187.93 2296.09,2225.37 2306.01,2235.29 v1(2306.01,2238) ; L3.2@2380.01,915 2384.21,919.2 v1(2384.21,969.31) ; v1(2644.21,1332.31) 2646.12,1330.4 2646.12,1316.08 2661.89,1300.31 C126.1@2665.83,1300.31 C129.1@2665.83,1245.31 ; v1@2658.21,2131.61 2671.33,2131.61 2676.23,2126.7 R127.1@2676.23,2099.49 ; R154.1@2660.48,1175.55 2664.42,1175.55 2670.23,1181.36 2670.23,1197.63 2677.21,1204.61 v1(2677.21,1207.31) ; v1(2675.21,1497.31) 2675.21,1500.02 2680.15,1504.96 2680.15,1530.5 U17.21@2681.23,1531.57 ; R128.2@2676.23,1910.51 2680.17,1910.51 2685.98,1904.7 2685.98,1881.25 2694.21,1873.02 v1(2694.21,1870.31) ; R151.2@2697.77,985 2698.48,985 2704.29,979.19 2704.29,953.23 v1(2706.21,951.31) ; v1(2718.21,1347.31) 2718.21,1344.61 2732.69,1330.12 2732.69,1301.21 C127.1@2733.58,1300.31 C128.1@2733.58,1245.31 ; R130.1@2720.83,2175.31 2724.21,2175.31 2772.21,2223.31 2772.21,2256.31 v1(2774.21,2256.31) ; R152.1@2775.01,1175 2778.95,1175 2796.29,1192.35 2796.29,1205.4 v1(2798.21,1207.31) ; U17.14@2785.56,1596.54 2786.64,1595.46 2799.5,1595.46 2817.29,1577.67 2817.29,1562.23 v1(2819.21,1560.31) ; v1(2836.01,1942) 2837.92,1940.09 2842.36,1940.09 2867.45,1915 C107.1@2871.39,1915 ; v1(2841.01,2115) 2841.01,2112.29 2852.84,2100.46 2852.84,2085.81 2858.65,2080 C104.1@2862.59,2080 ; v1(2841.21,1523.31) 2842.14,1523.31 2868.83,1550 C96.1@2872.77,1550 ; v1(2843.01,1971) 2843.01,1973.71 2854.83,1985.53 2854.83,2004.19 2860.64,2010 C105.1@2864.58,2010 ; C106.1@2866.39,2155 v1(2866.39,2188.62) ; C123.1@2880.83,1050.31 2881.83,1051.31 2920.21,1051.31 v1(2921.21,1052.31) ; v1(2905.21,1198.31) 2907.12,1196.4 2907.12,1161.12 2912.93,1155.31 C125.1@2915.83,1155.31 C124.1@2915.83,1100.31 ; C95.1@2918.63,1620 2922.57,1620 2928.38,1625.81 2928.38,1641.78 2940.21,1653.61 v1(2940.21,1656.31) ; C102.1@2918.63,1710 2919.42,1709.21 2919.42,1675.1 v1(2920.21,1674.31) ; C101.1@2918.63,1775 2922.57,1775 2941.1,1793.53 2941.1,1806.09 v1(2943.01,1808) ; C122.1@2918.83,989.31 2924.64,995.12 2944.02,995.12 v1(2970.21,1021.31) ; v1(2926.21,1361.31) 2928.12,1363.23 2928.12,1375.59 2957.53,1405 R117.1@2958.51,1405 ; v1(2963.21,1675.31) 2963.21,1678.02 2971.64,1686.45 2971.64,1704.19 2977.45,1710 R110.2@2981.39,1710 ; v1(2974.01,1809) 2975.92,1807.09 2975.92,1780.81 2981.73,1775 R111.2@2982.77,1775 ; v1(2980.21,1198.31) 2980.21,1152.65 2993.84,1139.02 2993.84,1121.12 2999.65,1115.31 C132.2@3003.58,1115.31 ; R115.2@2981.39,1485 2982.8,1483.59 2982.8,1453.72 v1(2984.21,1452.31) ; R108.2@2981.39,1620 2985.32,1620 3000.88,1635.56 3000.88,1636.78 3013,1648.9 3016.29,1648.9 v1(3018.21,1650.81) ; R107.2@2982.77,1550 2986.48,1550 2992.29,1544.19 2992.29,1520.23 v1(2994.21,1518.31) ; C133.2@3003.58,1065.31 3001.9,1063.62 3001.9,1031.38 3003.58,1029.69 3002.12,1028.23 3002.12,992.89 C135.2@3005.01,990 ; C136.2@3003.58,1165.31 3007.52,1165.31 3013.33,1171.12 3013.33,1193.73 3020.21,1200.61 v1(3020.21,1203.31) ; J4.5@3170.84,1643.39 3171.14,1643.7 3293.71,1643.7 v1(3294.01,1644) ; J4.6@3170.84,1683.55 3171.56,1684.28 3293.28,1684.28 v1(3294.01,1685) ; v1(3225.01,2224) 3225.01,2131.5 R116.1@3226.51,2130 ; U5.6@3318.87,457.2 3319.96,456.11 3368.41,456.11 3420.21,404.3 3420.21,388.6 C7.1@3416.62,392.2 ; v1(3320.01,2086) C114.2@3320.01,2121.38 ; v1(3375.01,2085) C116.2@3375.01,2121.38 ; C117.2@3430.01,2121.38 3431.01,2120.38 3431.01,2087 v1(3432.01,2086) ; v1(3485.01,2086) C118.2@3485.01,2121.38 ; v1@3524.42,611.52 v1(3525.21,612.31) 3525.21,643.38 R44.1@3525.33,643.5 ; v1(3593.21,555.31) 3595.91,555.31 3605.3,564.7 3621.72,564.7 3631.47,574.45 Y1.4@3631.47,576.42 ; Y2.4@3821.47,581.42 3821.84,581.79 3821.84,619.94 v1(3822.21,620.31)
  Bottom w15: C23:A.1@1188.79,2021.38 1188.79,2023.48 1193.1,2027.8 1230.45,2027.8 v1(1231.79,2029.13) ; v1(1226.96,2256.77) 1228.3,2258.11 1269.68,2258.11 C21:A.1@1271.96,2260.39
  other v1: 3393,431.61 3000.21,1030.31
VDDA_3V3: C8.1 C9.1 C10.1 C13.1 C14.1 C44.2 C61.1 C62.1 C64.2 L4.2 S3.1 S3.4 S4.1 S4.4 U1.P6 U1.R6 U6.2 U7.5 U8.5 U9.5 U10.5 U11.5 U12.5 U13.4 | length 1910.2
  Top Layer w10: v2(1719.69,882.87) U1.R6@1735.44,898.62 ; v2(1719.69,914.37) U1.P6@1735.44,930.12
  Top Layer w12: U7.5@181.02,772.01 v1(181.02,813.12) ; U9.5@336.42,772.01 v1(336.42,811.1) ; v1(491.21,811.31) 491.21,772.22 U8.5@491.42,772.01 ; U10.5@646.42,772.01 v1(646.42,813.1) ; v1(801.21,811.31) 801.21,772.22 U12.5@801.42,772.01 ; U11.5@956.42,772.01 v1(956.42,813.52) ; v1(1185.01,595) 1210.02,569.99 1247.73,569.99 U6.2@1248.82,568.89 ; v1@1203.28,768.27 1204.63,766.91 1206.31,768.6 U13.4@1254.14,768.6 ; S4.4@1517.52,578.93 1517.52,421.45 1549.31,389.67 v1(1549.31,387) ; v1(1772.21,375.31) 1772.21,378.02 1778.84,384.65 1778.84,419.58 S3.1@1792.52,433.26 S3.4@1792.52,578.93 ; v1(2009.21,584.31) 2009.21,587.02 2020.96,598.77 2020.96,633.95 2033.66,646.65 C64.2@2034.65,646.65
  Signal Layer 3 w12: v1@800.21,810.31 v1(801.21,811.31)
  Bottom w12: v1(181.02,813.12) 203.83,790.31 252.68,790.31 264.94,802.58 ; C8.1@264.94,834.82 264.94,802.58 ; v1(336.42,811.1) 315.63,790.31 277.21,790.31 264.94,802.58 ; v1(491.21,811.31) 507.21,795.31 562.21,795.31 572.21,805.31 ; C9.1@572.21,853.82 572.21,805.31 ; v1(646.42,813.1) 623.63,790.31 587.21,790.31 572.21,805.31 ; v1(801.21,811.31) 822.21,790.31 862.21,790.31 882.21,810.31 ; C10.1@882.21,848.82 882.21,810.31 ; v1(956.42,813.52) 933.21,790.31 902.21,790.31 882.21,810.31 ; v1(1110.01,550) C14.1@1153.54,550 ; v1(1200.01,765) 1247.88,765 C44.2@1250.01,767.12 ; C13.1@1219.92,548.62 1220.01,548.71 v1(1220.01,625) ; v2(1719.69,914.37) 1719.69,914.55 1738.69,933.55 1738.69,940.31 C61.1@1744.24,945.86 ; C61.1@1751.18,945.86 C62.1@1798.43,945.86 ; v1(2009.21,584.31) 2056.99,584.31 L4.2@2073.39,567.91
pads on no net: EC1.13 EC1.16 EC1.29 EC1.32 EC1.41 EC1.43 EC1.44 EC1.66 EC1.113 EC1.114 EC1.115 EC1.116 EC1.117 EC2.136 EC2.171 EC2.172 EC2.173 EC2.174 EC2.175 EC2.176 EC2.177 FID1.1 FID2.1 FID3.1 FID4.1 FID5.1 FID6.1 J1:A.4 J1:A.ALIGN1 J1:A.ALIGN2 J2.9 J4.9 J4.ALIGN1 J4.ALIGN2 J5.9 J5.ALIGN1 J5.ALIGN2 J6.9 J6.ALIGN1 J6.ALIGN2 LBL1.0 U1.H4 U1.J18 U1.J19 U1.V13 U1.W12 U2:A.22 U2:A.23 U2:A.26 U2:A.27 U2:A.29 U2:A.30 U2:A.33 U2:A.34 U2:A.43 U2:A.44 U2:A.45 U2:A.46 U2:A.48 U2:A.52 U2:A.53 U2:A.57 U2:A.58 U2:A.59 U3:A.2 U4:A.7 U6.1 U6.3 U6.7 U6.8 U7:A.3 U7:A.5 U7:A.7 U9:A.6 U13.8 U13.9 U16.5 U17.13 U17.15 U17.22 U17.33@2662.14,1597.13 U17.33@2662.14,1655 U17.33@2720.01,1597.13 U17.33@2720.01,1655 U19.13 U19.15 U19.22 U19.33@2661.07,1976.06 U19.33@2661.07,2033.94 U19.33@2718.95,1976.06 U19.33@2718.95,2033.94 U21.13 U21.15 U21.22 U21.33@2657.14,1052.13 U21.33@2657.14,1110 U21.33@2715.01,1052.13 U21.33@2715.01,1110
copper on no net:
  other v1: 752.21,345.31 812.21,345.31

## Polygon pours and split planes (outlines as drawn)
IN_5V0 on Bottom "BOTTOM_IN_5V0_P000" (solid, remove dead copper, pour order 0): 3704,940 3712,940 3880.01,940 3880.01,845 4035.01,845 4035.01,1000 3956,1000 3956,1150 3870.01,1150 3870.01,1187 3665.01,1187 3665.01,1120 3805.01,1120 3805.01,1040 3704,1040
1V2 on Bottom "BOTTOM_1V2_P002" (solid, remove dead copper, pour order 2): 3115.01,1070 3115.01,970 3345.01,970 3345.01,935 3450.01,935 3450.01,1075 3405.01,1075 3405.01,1130 3270.01,1130 3270.01,1070
3V3 on Bottom "BOTTOM_3V3_P004" (solid, remove dead copper, pour order 4): 3085.01,880 3160.01,880 3160.01,870 3255.01,870 3255.01,835 3324,835 3324,790 3330.01,790 3330.01,705 3455.01,705 3455.01,780 3435.01,780 3435.01,920 3335.01,920 3335.01,965 3330.01,960 3085.01,960
GND on Internal Plane 5 (split plane): 954.64,245.31 954.9,243.35 955.34,242.29 955.66,241.53 956.86,239.96 1026.86,169.96 1028.42,168.76 1030.25,168.01 1032.21,167.75 1192.51,167.75 1192.51,19.58 309.56,19.58 309.56,235.49 309.18,239.41 308.03,243.18 306.17,246.65 303.68,249.7 300.63,252.2 297.16,254.05 293.39,255.2 289.46,255.58 132.56,255.58 132.56,290.06 133.18,289.8 139.49,287.98 145.97,286.88 152.53,286.51 159.09,286.88 165.56,287.98 171.88,289.8 177.95,292.31 183.69,295.49 189.05,299.29 193.95,303.67 198.33,308.57 202.13,313.93 205.31,319.67 207.82,325.74 208.18,326.99 211.44,330.25 212.5,331.31 213.05,332.14 213.25,333.12 213.25,350.41 213.05,351.38 212.5,352.21 210.56,354.15 210.56,479.49 210.18,483.41 209.03,487.18 208.97,487.29 209.42,487.75 954.64,487.75
VDDA_3V3 on Internal Plane 5 (split plane): 1775.11,911.23 1775.11,756.89 1775.11,737.33 1775.37,735.37 1775.82,734.3 1776.13,733.55 1777.33,731.98 1869.66,639.65 1871.23,638.45 1873.05,637.69 1875.01,637.44 2014.39,637.44 2039.64,612.18 2039.64,484.45 2016.86,461.66 1894.07,338.88 1556.83,338.88 1517.57,378.13 1517.57,422.51 1517.32,424.47 1516.56,426.29 1515.36,427.86 1442.56,500.66 1440.99,501.86 1440.23,502.18 1439.16,502.62 1437.21,502.88 206.29,502.88 204.33,502.62 202.51,501.86 200.94,500.66 198.27,497.99 198.16,498.05 194.39,499.2 190.46,499.58 19.58,499.58 19.58,888.75 1512.66,888.75 1514.61,889 1515.68,889.45 1516.44,889.76 1518,890.96 1565.34,938.3 1748.05,938.3
HSEC_5V0 on Internal Plane 5 (split plane): 257 vertices, not listed, extent 969.77,19.58 4144.4,2177.75
EMU_1V8 on Internal Plane 5 (split plane): 1000.44,1300.43 950.01,1250 19.58,1250 19.58,2350.41 1000.44,2350.41
GND on Internal Plane 5 (split plane): 1527.37,1409.45 1528.94,1408.25 1530.76,1407.49 1532.72,1407.24 1649.13,1407.24 1649.13,1166.34 1649.13,953.43 1562.21,953.43 1560.25,953.17 1559.18,952.73 1558.42,952.41 1556.86,951.21 1509.52,903.88 19.58,903.88 19.58,1160.61 989.4,1160.61 990.01,1160 1115.01,1285 1115.01,1432.75 1504.07,1432.75
GND on Internal Plane 5 (split plane): 1424.64,1812.88 1115.01,1812.88 1115.01,2350.41 1424.64,2350.41
VDD_1V2 on Internal Plane 5 (split plane): 2454.64,1752.18 2454.64,1498.45 2346.86,1390.66 2345.66,1389.09 2345.34,1388.34 2344.9,1387.27 2344.64,1385.31 2344.64,1295.31 2344.9,1293.35 2345.34,1292.29 2345.66,1291.53 2346.86,1289.96 2371.86,1264.96 2373.42,1263.76 2375.25,1263.01 2377.21,1262.75 2424.07,1262.75 2454.64,1232.18 2454.64,1148.45 2316.86,1010.66 2012.17,705.97 2010.97,704.41 2010.65,703.65 2010.21,702.58 2009.95,700.62 2009.95,652.56 1878.14,652.56 1790.24,740.46 1790.24,756.89 1790.24,914.37 1789.99,916.33 1789.23,918.15 1788.03,919.72 1756.53,951.21 1754.97,952.41 1754.21,952.73 1753.14,953.17 1751.18,953.43 1664.26,953.43 1664.26,1166.34 1664.26,1411.67 1855.34,1602.75 1987.21,1602.75 1989.16,1603.01 1990.23,1603.45 1990.99,1603.76 1992.56,1604.96 2255.34,1867.75 2339.07,1867.75
3V3 on Internal Plane 5 (split plane): 2376.86,939.96 2378.42,938.76 2380.25,938.01 2380.48,937.98 2382.21,937.75 3424.07,937.75 3459.64,902.18 3459.64,828.45 3444.07,812.88 3065.32,812.88 3063.36,812.62 3061.54,811.86 3059.97,810.66 2951.88,702.56 2426.9,702.56 2426.9,702.57 2424.94,702.31 2423.87,701.86 2423.11,701.55 2421.55,700.35 2309.07,587.88 2054.77,587.88 2054.77,615.31 2054.51,617.27 2053.76,619.09 2052.56,620.66 2025.08,648.13 2025.08,697.49 2322.21,994.61
1V2 on Internal Plane 5 (split plane): 2866.86,1269.96 2868.42,1268.76 2870.25,1268.01 2872.21,1267.75 3234.07,1267.75 3414.64,1087.18 3414.64,952.88 2385.34,952.88 2332.91,1005.31 2467.56,1139.96 2468.76,1141.53 2469.51,1143.35 2469.77,1145.31 2469.77,1235.31 2469.51,1237.27 2468.76,1239.09 2467.56,1240.66 2432.56,1275.66 2430.99,1276.86 2430.23,1277.18 2429.16,1277.62 2427.21,1277.88 2380.34,1277.88 2359.77,1298.45 2359.77,1382.18 2467.56,1489.96 2468.76,1491.53 2469.26,1492.75 2644.07,1492.75
USB_5V0 on Internal Plane 5 (split plane): 1928.01,2267.42
no net on Internal Plane 5 (split plane): 1928,2267.42 1927.92,2267.43
no net on Internal Plane 5 (split plane): 3229.64,1476.18 3229.64,1282.88 2875.34,1282.88 2652.56,1505.66 2650.99,1506.86 2650.23,1507.18 2649.16,1507.62 2647.21,1507.88 2469.77,1507.88 2469.77,1755.31 2469.51,1757.27 2468.76,1759.09 2467.56,1760.66 2360.47,1867.75 2838.07,1867.75
USB_5V0 on Internal Plane 5 (split plane): 4144.4,1057.88 3920.34,1057.88 3804.77,1173.45 3804.77,1800.31 3804.51,1802.27 3803.76,1804.09 3802.56,1805.66 3417.56,2190.66 3415.99,2191.86 3415.23,2192.18 3414.16,2192.62 3412.21,2192.88 1907.21,2192.88 1905.25,2192.62 1903.42,2191.86 1901.86,2190.66 1746.86,2035.66 1745.66,2034.09 1745.34,2033.34 1744.9,2032.27 1744.64,2030.31 1744.64,1808.45 1589.07,1652.88 1515.34,1652.88 1439.77,1728.45 1439.77,2350.41 1695.51,2350.41 1704.15,2341.77 1704.15,2305.27 1704.26,2304.21 1704.49,2300.65 1705.47,2295.74 1707.07,2291.01 1709.28,2286.53 1712.06,2282.38 1715.35,2278.62 1719.11,2275.32 1723.27,2272.55 1727.75,2270.34 1732.48,2268.73 1737.38,2267.76 1740.93,2267.52 1741.59,2267.46 1742,2267.42 1742.93,2267.51 1746.61,2267.75 1751.35,2268.69 1755.92,2270.25 1760.26,2272.39 1764.28,2275.07 1767.91,2278.26 1771.1,2281.89 1773.78,2285.91 1775.92,2290.24 1777.47,2294.82 1778.42,2299.56 1778.7,2303.85 1778.75,2304.39 1778.74,2304.49 1778.75,2304.59 1778.75,2304.6 1778.75,2341.77 1786.96,2349.98 1882.95,2349.98 1891.16,2341.77 1891.16,2305.18 1889.8,2305.22 1889.54,2304.6 1891.16,2304.6 1891.16,2304.59 1891.18,2304.39 1891.49,2299.6 1892.44,2294.86 1893.99,2290.27 1896.13,2285.93 1898.82,2281.91 1902.01,2278.27 1905.65,2275.08 1909.68,2272.39 1914.02,2270.25 1918.6,2268.7 1923.34,2267.75 1926.89,2267.52 1927.31,2267.47 1927.26,2266.11 1927.78,2265.89 1928,2265.8 1928.2,2265.88 1928.19,2267.43 1928.21,2267.44 1928.29,2267.43 1933.18,2267.75 1937.98,2268.71 1942.62,2270.28 1947.01,2272.45 1951.09,2275.17 1954.77,2278.4 1958,2282.09 1960.72,2286.16 1962.89,2290.56 1964.47,2295.19 1965.42,2300 1965.64,2303.31 1965.76,2304.36 1965.76,2304.37 1965.75,2304.48 1965.76,2304.6 1965.76,2304.61 1965.76,2341.77 1974.41,2350.42 4144.4,2350.42
GND on Internal Plane 2 (split plane): 245 vertices, not listed, extent 19.58,19.58 4144.4,2350.42
EMU_GND on Internal Plane 2 (split plane): 1000.44,1300.43 950.01,1250 19.58,1250 19.58,2350.41 1000.44,2350.41
GND on Internal Plane 2 (split plane): 1928.01,2267.42
no net on Internal Plane 2 (split plane): 1928,2267.42 1927.92,2267.43
VDD_3V3 on Internal Plane 6 (split plane): 245 vertices, not listed, extent 19.58,19.58 4144.4,2350.42
EMU_3V3 on Internal Plane 6 (split plane): 1000.44,1300.43 950.01,1250 19.58,1250 19.58,2350.41 1000.44,2350.41
VDD_3V3 on Internal Plane 6 (split plane): 1928.01,2267.42
no net on Internal Plane 6 (split plane): 1928,2267.42 1927.92,2267.43
GND on Internal Plane 9 (split plane): 245 vertices, not listed, extent 19.58,19.58 4144.4,2350.42
EMU_GND on Internal Plane 9 (split plane): 1000.44,1300.43 950.01,1250 19.58,1250 19.58,2350.41 1000.44,2350.41
GND on Internal Plane 9 (split plane): 1928.01,2267.42
no net on Internal Plane 9 (split plane): 1928,2267.42 1927.92,2267.43

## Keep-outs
Keep-Out Layer:
  text ".Layer_Name" at -2483.86,-1945.78 h60

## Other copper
Top Layer:
  text ".Layer_Name" at -2483.86,-1945.78 h60
Signal Layer 3:
  text ".Layer_Name" at -2500,-1950 h60
Signal Layer 4:
  text ".Layer_Name" at -2500,-1950 h60
Signal Layer 7:
  text ".Layer_Name" at -2500,-1950 h60
Signal Layer 8:
  text ".Layer_Name" at -2500,-1950 h60
Bottom:
  text ".Layer_Name" at -2483.86,-1945.78 h60
Internal Plane 2 (plane layer: these items are gaps in the copper):
  rectangle: -1.84,1160.61 990.01,1250
  rectangle: 1000.44,1285 1115.01,2356.57
  region: 990.01,1160 1115.01,1285 1050.01,1350 925.01,1225
  lines w5: 193.87,350.41 210.7,350.41 ; 202.58,325 209.64,332.06 210.7,333.12 210.7,350.41 ; 206.11,355 210.7,350.41
  text ".Layer_Name" at -2525,-1950 h60
Internal Plane 5 (plane layer: these items are gaps in the copper):
  region: 990.01,1160 1115.01,1285 1050.01,1350 925.01,1225
  rectangle: 1000.44,1285 1115.01,2356.57
  rectangle: -1.84,1160.61 990.01,1250
  lines w5: 193.87,350.41 210.7,350.41 ; 202.58,325 209.64,332.06 210.7,333.12 210.7,350.41 ; 206.11,355 210.7,350.41
  lines w15: 0,896.31 1462.21,896.31 1512.66,896.31 1562.21,945.86 1719.69,945.86 1751.18,945.86 1782.68,914.37 1782.68,756.89 1782.68,737.33 1875.01,645 2017.52,645 ; 190.98,480 206.29,495.31 1437.21,495.31 1510.01,422.51 1510.01,375 1553.7,331.31 1835.21,331.31 1897.21,331.31 2022.21,456.31 2047.21,481.31 2047.21,615.31 2017.52,645 ; 962.21,495.31 962.21,245.31 1032.21,175.31 1212.09,175.31 ; 1077.21,1440.31 1507.21,1440.31 1532.72,1414.8 1656.7,1414.8 ; 1087.21,1805.31 1432.21,1805.31 ; 1432.21,2370.31 1432.21,1725.31 1512.21,1645.31 1592.21,1645.31 1752.21,1805.31 1752.21,2030.31 1907.21,2185.31 3412.21,2185.31 3797.21,1800.31 3797.21,1170.31 3917.21,1050.31 4163.98,1050.31 ; 1656.7,945.86 1656.7,1166.34 1656.7,1414.8 ; 2047.21,580.31 2312.21,580.31 2426.9,695 2780.01,695 2955.01,695 3065.32,805.31 3447.21,805.31 3467.21,825.31 3467.21,905.31 3427.21,945.31 2382.21,945.31 2322.21,1005.31 ; 2347.21,1875.31 2841.21,1875.31 3237.21,1479.31 3237.21,1275.31 ; 2462.21,1500.31 2647.21,1500.31 2872.21,1275.31 3237.21,1275.31 ; 3422.21,945.31 3422.21,1090.31 3237.21,1275.31 ; 1656.7,1414.8 1852.21,1610.31 1987.21,1610.31 2252.21,1875.31 2342.21,1875.31 2462.21,1755.31 2462.21,1495.31 2352.21,1385.31 2352.21,1295.31 2377.21,1270.31 2427.21,1270.31 2462.21,1235.31 2462.21,1145.31 2017.52,700.62 2017.52,645
  text ".Layer_Name" at -2500,-1950 h60
Internal Plane 6 (plane layer: these items are gaps in the copper):
  region: 990.01,1160 1115.01,1285 1050.01,1350 925.01,1225
  rectangle: 1000.44,1285 1115.01,2356.57
  rectangle: -1.84,1160.61 990.01,1250
  lines w5: 193.87,350.41 210.7,350.41 ; 202.58,325 209.64,332.06 210.7,333.12 210.7,350.41 ; 206.11,355 210.7,350.41
  text ".Layer_Name" at -2500,-1950 h60
Internal Plane 9 (plane layer: these items are gaps in the copper):
  region: 990.01,1160 1115.01,1285 1050.01,1350 925.01,1225
  rectangle: 1000.44,1285 1115.01,2356.57
  rectangle: -1.84,1160.61 990.01,1250
  lines w5: 193.87,350.41 210.7,350.41 ; 202.58,325 209.64,332.06 210.7,333.12 210.7,350.41 ; 206.11,355 210.7,350.41
  text ".Layer_Name" at -2500,-1950 h60

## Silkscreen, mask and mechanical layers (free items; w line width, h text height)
Top Overlay:
  region: 2267.21,345.31 1967.21,345.31 1967.21,245.31 2267.21,245.31
  text "P0" at 3683,2292 h40
  text "P1" at 3688,509 h40
  text "'.PRJ_Number'.PCB_Rev-" at 1413.21,260.65 h108.27
  text ".Layer_Name" at -2483.86,-1945.78 h60
Bottom Overlay:
  text "5V0" at 1090.77,1658.26 h53
  text "GND" at 1100.84,1583.05 h53
  text "3V0" at 1090.76,1508.27 h53
  text "1V2" at 2418,1405 h50
  text "3V3" at 2861.9,1390.6 h50
  text "C28x" at 2820.73,730.87 h40
  text "P0" at 2883.35,730.87 h40
  text "P1" at 2972.22,730.45 h40
  text "ERRORSTS" at 4000,245 h40 r270
  text ".Layer_Name" at -2483.86,-1945.78 h60
Top Paste:
  text ".Layer_Name" at -2483.86,-1945.78 h60
Bottom Paste:
  text ".Layer_Name" at -2483.86,-1945.78 h60
Top Solder:
  lines w1: 1778.85,2369.56 1891.06,2369.56
  lines w39.37: 1703.62,2369.99 1723.73,2349.88 1723.73,2304.6 ; 1724.4,2304.6 ccw(c1741.78,2304.39) 1759.17,2304.6 ; 1778.85,2369.56 1759.17,2349.88 1759.17,2304.6 ; 1891.06,2369.56 1910.74,2349.88 1910.74,2304.6 ccw(c1928.17,2304.43) 1928,2287 ccw(c1928.29,2304.89) 1946.18,2304.6 1946.18,2349.88 1966.3,2370 ; 1759.17,2304.6 1759.17,2304.6
  lines w50: 190.98,347 190.98,480 0.01,480 0,2370 4163.98,2370 4163.98,236.1 4098.57,236.1 4098.57,4 3103.29,4 3103.29,480 2452.98,480 2452.98,443.59 2452.98,346 ; 191.48,347.03 cw(c152.53,345.09) 128.98,314 112.98,314 112.98,236 289.98,236 289.98,0 1212.09,0 1212.09,197 cw(c1259.09,197) 1306.09,197 1306.09,0 2354.98,0 2354.98,236 2531.98,236 2531.98,315 2515.98,315 cw(c2492.48,346.12) 2453.48,346
  text ".Layer_Name" at -2483.86,-1945.78 h60
  text ".Layer_Name" at -2483.86,-1945.78 h60
Bottom Solder:
  lines w39.37: 1703.62,2369.99 1723.73,2349.88 1723.73,2304.6 ; 1724.4,2304.6 ccw(c1741.78,2304.39) 1759.17,2304.6 ; 1778.85,2369.56 1759.17,2349.88 1759.17,2304.6 ; 1891.06,2369.56 1910.74,2349.88 1910.74,2304.6 ccw(c1928.17,2304.43) 1928,2287 ccw(c1928.29,2304.89) 1946.18,2304.6 1946.18,2349.88 1966.3,2370 ; 1759.17,2304.6 1759.17,2304.6
  lines w50: 190.98,347 190.98,480 0.01,480 0,2370 4163.98,2370 4163.98,236.1 4098.57,236.1 4098.57,4 3103.29,4 3103.29,480 2452.98,480 2452.98,443.59 2452.98,346 ; 191.48,347.03 cw(c152.53,345.09) 128.98,314 112.98,314 112.98,236 289.98,236 289.98,0 1212.09,0 1212.09,197 cw(c1259.09,197) 1306.09,197 1306.09,0 2354.98,0 2354.98,236 2531.98,236 2531.98,315 2515.98,315 cw(c2492.48,346.12) 2453.48,346
  text ".Layer_Name" at -2483.86,-1945.78 h60
Drill Guide:
  text ".Layer_Name" at -2483.86,-1945.78 h60
M1 Board Outline:
  lines w10: 190.98,347 190.98,480 0.01,480 0,2369.99 1703.62,2369.99 1723.73,2349.88 1723.73,2304.6 ; 191.48,347.03 cw(c152.53,345.09) 128.98,314 112.98,314 112.98,236 289.98,236 ; 1724.4,2304.6 ccw(c1741.78,2304.39) 1759.17,2304.6 ; 2354.98,236 2531.98,236 2531.98,315 2515.98,315 cw(c2492.48,346.12) 2453.48,346 ; 2452.98,346 2452.98,443.59 2452.98,480 3103.29,480 3103.29,4 4098.57,4 4098.57,236.1 4163.98,236.1 4163.98,2370 1966.3,2370 1946.18,2349.88 1946.18,2304.6 cw(c1928.29,2304.89) 1928,2287 cw(c1928.17,2304.43) 1910.74,2304.6 1910.74,2349.88 1891.06,2369.56 1778.85,2369.56 1759.17,2349.88 1759.17,2304.6 ; 1759.17,2304.6 1759.17,2304.6
  text ".Layer_Name" at -2483.86,-1945.78 h60
M2 Board Dimensions:
  rectangle: -3060.86,-1362.29 -2935.86,-1237.29
  rectangle: -2935.86,-1487.29 -2560.86,-1362.29
  lines w5: 280,265 290,255 ; 300,265 290,255 ; 460,300 315,300 290,275 290,255 ; 2370,205 2370,220 ; 2385,220 2370,220 ; 2385,515 2385,480 2405,480 2435,480 ; 2425,470 2435,480 ; 2425,490 2435,480 ; 2620,530 2630,520 3105,520 3105,500 3105,485 ; 2755,-355 2755,-185 2400,170 2400,190 2370,220 ; 3095,495 3105,485 ; 3115,495 3105,485 ; 4060,350 4060,325 4080,305 4100,285 4100,270 4100,245 ; 4090,255 4100,245 ; 4110,255 4100,245
  lines w7: -3060.86,-1362.29 -2060.86,-1362.29 ; -2935.86,-1487.29 -2935.86,-1237.29 ; -2810.86,-1487.29 -2810.86,-1237.29 ; -2560.86,-1487.29 -2560.86,-1237.29 ; -2310.86,-1487.29 -2310.86,-1237.29 ; -3060.86,-1487.29 -2060.86,-1487.29 -2060.86,-1237.29 -3060.86,-1237.29 -3060.86,-1487.29
  lines w10: 205,520 205,500 ; 225,500 205,500 ; 300,515 220,515 205,500 ; 6777.14,-860.29 6845.14,-860.29 ; 6819.14,-889.29 6846.14,-861.29 ; 6819.14,-830.29 6846.14,-860.29 ; 6853.14,484.71 6921.14,566.71 ; 6855.14,-907.29 6855.14,-585.29 ; 6855.14,-544.29 6905.14,-598.29 7015.14,-598.29 7062.14,-541.29 ; 6855.14,-542.29 6855.14,487.71 ; 6920.14,567.71 6984.14,480.71 ; 6938.14,-692.29 7006.14,-692.29 ; 6980.14,-721.29 7007.14,-693.29 ; 6980.14,-662.29 7007.14,-692.29 ; 6985.14,479.71 7057.14,569.71 ; 7016.14,-907.29 7016.14,-625.29 ; 7062.14,-542.29 7062.14,487.71 7062.14,572.71 ; 7063.14,-907.29 7063.14,-585.29 ; 7069.1,108.34 cw(c7013.14,-599.29) 7452.47,-41.75 ; 7070.98,106.97 ccw(c7210.73,341.63) 7121.85,83.38 ; 7071.14,-857.29 7098.14,-887.29 ; 7071.14,-856.29 7098.14,-828.29 ; 7071.14,113.71 cw(c7103.59,-60.26) 7133.86,114.11 ; 7073.14,-856.29 7141.14,-856.29 ; 7073.14,-693.29 7100.14,-723.29 ; 7073.14,-692.29 7100.14,-664.29 ; 7075.14,-692.29 7143.14,-692.29 ; 7089.14,-503.29 7552.14,68.71 ; 7399.14,-27.29 ccw(c7536.66,313.14) 7453.8,-44.54 ; 7416.38,6.02 cw(c7299.53,-127.43) 7455.14,-42.29
  text "x2" at 1394,2897 h60 r90
  text "x2" at 2085,2795 h60
  text "x2" at 1584,2722 h60
  text "x2" at 2302,2529 h60 r90
  text "X2" at 2510,635 h60
  text "R 39.00" at 2225,550 h60
  text "R 39.00" at 330,495 h60
  text "R 39.00" at 3740,370 h60
  text "R 39.00" at 490,265 h60
  text "30" at 7258.14,128.71 h60
  text "R 39.00" at 2625,-440 h60
  text "18MIL" at 7184.14,-720.29 h60
  text "62MIL" at 7177.14,-884.29 h60
  text "GOLD FINGER" at 6696.14,-1121.29 h60
  text "SIDE VIEW" at 6750.14,-1234.29 h60
  text ".Layer_Name" at -2483.86,-1945.78 h60
M3 3D STEP Top:
  text ".Layer_Name" at -2483.86,-1945.78 h60
M4 3D STEP Bottom:
  text ".Layer_Name" at -2483.86,-1945.78 h60
M5 Assembly Top:
  lines w10: -3352.86,-2017.45 3247.14,-2017.45 ; -3352.86,-1814.12 3249.14,-1814.12 ; -3352.86,-1610.79 -3352.86,-2220.79 652.14,-2220.79 3249.14,-2220.79 3249.14,-1610.79 -3352.36,-1610.79 -3352.36,-2220.79 -1776.86,-2220.79 ; -887.86,-2220.79 -887.86,-1610.79 ; 379.14,-1814.12 379.14,-1610.79 ; 1219.14,-1814.12 1219.14,-1610.79 ; 1841.14,-2227.29 1841.14,-2024.45
  text "COMPONENTS MARKED 'DNP' SHOULD NOT BE POPULATED." at -1907.36,-1405.79 h60
  text "ASSEMBLY VARIANT:" at -1907.86,-1521.29 h60
  text ".VariantName" at -871.86,-1521.29 h60
  text "PCB VIEWED FROM TOP SIDE" at -3289.36,-1742.95 h60
  text "BOARD #:" at -812.86,-1742.95 h60
  text ".PRJ_Number" at -267.36,-1742.95 h60
  text "REV:" at 577.14,-1742.95 h60
  text ".PCB_Rev" at 868.64,-1742.95 h60
  text "SVN REV:" at 1415.14,-1742.95 h60
  text ".VersionControl_RevNumber" at 1921.14,-1742.95 h60
  text "TID #:" at -812.86,-1946.29 h60
  text ".TID" at -267.36,-1946.29 h60
  text "PLOT NAME =" at -3289.36,-2151.62 h60
  text ".plot_File_Name" at -2483.86,-2151.62 h60
  text "GENERATED    :" at -810.86,-2151.62 h60
  text ".Print_Date" at 58.64,-2151.62 h60
  text ".Print_Time" at 787.64,-2151.62 h60
  text "TEXAS INSTRUMENTS" at 2052.14,-2151.62 h60
M6 Assembly Bottom:
  lines w10: -3353.36,-1814.62 3248.64,-1814.62 ; -3351.36,-2017.95 3248.64,-2017.95 ; -1945.36,-2227.79 -1945.36,-2024.95 ; -1323.36,-1814.62 -1323.36,-1611.29 ; -483.36,-1814.62 -483.36,-1611.29 ; 783.64,-2221.29 783.64,-1611.29 ; 1672.64,-2221.29 3248.14,-2221.29 3248.14,-1611.29 -3353.36,-1611.29 -3353.36,-2221.29 -756.36,-2221.29 3248.64,-2221.29 3248.64,-1611.29
  text "COMPONENTS MARKED 'DNP' SHOULD NOT BE POPULATED." at 3041.14,-1405.29 h60
  text ".VariantName" at 1997.14,-1521.29 h60
  text "ASSEMBLY VARIANT:" at 3036.14,-1521.29 h60
  text ".VersionControl_RevNumber" at -2025.36,-1743.45 h60
  text "SVN REV:" at -1519.36,-1743.45 h60
  text ".PCB_Rev" at -972.86,-1743.45 h60
  text "REV:" at -681.36,-1743.45 h60
  text ".PRJ_Number" at 163.14,-1743.45 h60
  text "BOARD #:" at 708.64,-1743.45 h60
  text "PCB VIEWED FROM BOTTOM SIDE" at 3185.14,-1743.45 h60
  text ".TID" at 163.14,-1946.79 h60
  text "TID #:" at 708.64,-1946.79 h60
  text "TEXAS INSTRUMENTS" at -2156.36,-2152.12 h60
  text ".Print_Time" at -891.86,-2152.12 h60
  text ".Print_Date" at -162.86,-2152.12 h60
  text "GENERATED    :" at 706.64,-2152.12 h60
  text ".plot_File_Name" at 2379.64,-2152.12 h60
  text "PLOT NAME =" at 3185.14,-2152.12 h60
M9 Title Sheet:
  drawing of 57 lines, arcs and shapes, not listed
  text "1" at -2321.03,6949.21 h70
  text "2" at 174.64,6949.21 h70
  text "3" at 2663.98,6949.21 h70
  text "4" at 5170.65,6949.21 h70
  text "5" at 7669.64,6949.21 h70
  text "6" at 10174.64,6949.21 h70
  text "A" at -3477.36,5806.21 h70
  text "A" at 11322.64,5806.21 h70
  text "B" at -3477.36,3426.21 h70
  text "B" at 11322.64,3426.21 h70
  text "C" at -3477.36,1051.21 h70
  text "C" at 11322.64,1051.21 h70
  text "PROJECT TITLE:" at 8282.64,-809.79 h45
  text ".PRJ_Title" at 8332.64,-943.11 h70
  text "DESIGNED FOR:" at 8282.64,-1110.79 h45
  text ".PRJ_Customer" at 8332.64,-1250.79 h70
  text "D" at -3477.36,-1318.79 h70
  text "D" at 11322.64,-1318.79 h70
  text "FILE NAME:" at 8282.64,-1410.79 h45
  text ".PCB_File_Name_No_Path" at 8332.64,-1530.79 h70
  text "Texas Instruments (TI) and/or its licensors do not warrant the accuracy or completeness of this specification" at 3313.14,-1692.62 h45
  text "ENGINEER:" at 8282.64,-1700.79 h45
  text "LAYOUT BY:" at 9787.64,-1700.79 h45
  text "or any information contained therein. TI and/or its licensors do not warrant that this design will meet" at 3268.15,-1805.29 h45
  text ".PRJ_Engineer" at 8332.64,-1855.78 h70
  text ".PCB_Layout" at 9838.14,-1855.78 h70
  text "the specifications, will be suitable for your application or fit for any particular purpose, or will operate in" at 3268.15,-1917.95 h45
  text ".Layer_Name" at -2483.86,-1945.78 h60
  text "ALTIUM DESIGNER VERSION:" at 9787.64,-2010.79 h45
  text "an implementation. TI and/or its licensors do not warrant that the design is production worthy. You should" at 3268.15,-2030.62 h45
  text "completely validate and test your design implementation to confirm the system functionality for your application." at 3313.14,-2143.29 h45
  text ".print_Scale" at 8332.64,-2144.11 h70
  text ".Application_BuildNumber" at 9838.14,-2144.11 h70
  text "1" at -2321.03,-2350.79 h70
  text "2" at 174.64,-2350.79 h70
  text "3" at 2663.98,-2350.79 h70
  text "4" at 5170.65,-2350.79 h70
  text "5" at 7669.64,-2350.79 h70
  text "6" at 10174.64,-2350.79 h70
M10 Fab Notes:
  drawing of 181 lines, arcs and shapes, not listed
  text "DESIGN INFORMATION" at 9321.15,5408.89 h60
  text "4" at 9775,5280 h60
  text "MIN. TRACK WIDTH:" at 8676.6,5276.76 h60
  text "MIL" at 9927.6,5276.76 h60
  text "4" at 9785,5160 h60
  text "MIN. CLEARANCE:" at 8676.6,5152.64 h60
  text "MIL" at 9927.6,5152.64 h60
  text "MIN. VIA PAD SIZE:" at 8676.6,5028.51 h60
  text "18" at 9742.85,5028.51 h60
  text "MIL" at 9927.6,5028.51 h60
  text "0.05mm (2MIL)" at 9371.6,4898.61 h60
  text "MINIMUM ANNULAR RING" at 8347.36,4890.39 h60
  text "EXTERNAL" at 10079.6,4890.39 h60
  text "PER" at 8547.36,4780.26 h60
  text "IPC-D-275 CLASS 2 LEVEL C" at 8767.36,4780.26 h60
  text "MIL, HOLES" at 10255.6,4679.78 h60
  text "+/-" at 9863.14,4671.2 h60
  text "+/-" at 10717.14,4671.2 h60
  text "REGISTRATION TOLERANCES:" at 8347.36,4670.13 h60
  text "METAL" at 9547.14,4670.13 h60
  text "5" at 10123.34,4670.14 h60
  text "3" at 10956.34,4670.14 h60
  text "MIL" at 11072.6,4670.13 h60
  text "HOLE SIZE TOLERANCE (UNLESS OTHERWISE SPECIFIED):" at 8347.36,4571.82 h60
  text "+/-" at 10717.14,4568.95 h60
  text "3" at 10956.34,4567.88 h60
  text "MIL" at 11072.6,4567.88 h60
  text "MATERIAL:" at 8272.6,4430.23 h60
  text "FR-4 High Tg" at 9259.04,4301.71 h60
  text "X" at 9114.6,4293.72 h60
  text "FR-408" at 8693.6,4289.2 h60
  text "OTHER" at 10181.6,4289.2 h60
  text "62 MIL (1.6mm) +/-10%" at 9013.7,4146.17 h60
  text "X" at 8893.6,4143.72 h60
  text "THICKNESS:" at 8347.36,4137.95 h60
  text "OTHER" at 10298.6,4137.95 h60
  text "TOLERANCE:" at 8347.36,3999.64 h60
  text "X" at 9195.6,3999.64 h60
  text "ANSI IPC-6012 TYPE 3 CLASS 2" at 9373.61,3999.64 h60
  text "OTHER +/-" at 9373.6,3855.45 h60
  text "BOW & TWIST:" at 8347.36,3710.26 h60
  text "X" at 9195.6,3710.26 h60
  text "ANSI IPC-6012 TYPE 3 CLASS 2" at 9373.61,3710.26 h60
  text "OTHER +/-" at 9373.6,3563.56 h60
  text "DRILLING:" at 8272.6,3432.94 h60
  text "NC_DRILL FILES" at 10033.6,3327.75 h60
  text "REFERENCE:" at 8347.36,3323.82 h60
  text "X" at 9004.6,3323.72 h60
  text "AS SHOWN" at 9182.6,3323.82 h60
  text "X" at 9905.6,3323.82 h60
  text "OTHER" at 10331.6,3181.57 h60
  text "PTH COPPER THICKNESS:" at 8347.04,3178.04 h60
  text "X" at 9486.28,3178.04 h60
  text "20-30 um" at 9614.27,3178.04 h60
  text "BOARD FINISH:" at 8272.6,3030.44 h60
  text "SILKSCREEN:" at 8427.82,2920.31 h60
  text "X" at 9385.6,2920.31 h60
  text "TOP" at 9502.6,2920.31 h60
  text "X" at 9895.6,2920.31 h60
  text "BOTTOM" at 10013.6,2920.31 h60
  text "SILKSCREEN COLOR:" at 8427.82,2765.12 h60
  text "X" at 9384.6,2765.12 h60
  text "WHITE" at 9502.6,2765.12 h60
  text "OTHER" at 10013.6,2765.12 h60
  text "BLUE" at 10668.6,2631.68 h60
  text "GREEN" at 9633.6,2621.68 h60
  text "X" at 10105.6,2621.68 h60
  text "OTHER" at 10251.6,2621.68 h60
  text "SOLDER RESIST COLOR:" at 8427.82,2614.81 h60
  text "X" at 10106,2469.7 h60
  text "MATTE" at 9633.6,2467.42 h60
  text "SEMI-GLOSS" at 10251.14,2466.79 h60
  text "IMMERSION GOLD (ENIG)" at 9333.59,2294.65 h60
  text "ENEPIG" at 10671.14,2287.43 h60
  text "SURFACE FINISH:" at 8272.6,2286.43 h60
  text "X" at 9155.6,2286.43 h60
  text "IMM. TIN/SILVER OR EQUIV" at 8602.14,2149.12 h60
  text "HARD GOLD OVER NICKEL 30u/80u, ON EDGEFINGERS" at 8976.56,1996.11 h60
  text "X" at 8445.6,1986.43 h60
  text "OTHER" at 8623.6,1985.18 h60
  text "ARRAY/PANEL:" at 8272.6,1849.8 h60
  text "CUT AND TRIM PER M1 BOARD OUTLINE" at 9333.6,1841.58 h60
  text "N.C. ROUTE" at 9333.6,1705.61 h60
  text "X" at 10021.6,1705.61 h60
  text "V. SCORE" at 10199.6,1705.61 h60
  text "CERTIFICATION:" at 8272.6,1576.49 h60
  text "MATERIALS AND WORKMANSHIP FOR ALL PCBS" at 8997.6,1576.49 h60
  text "J4-J6: NPTH on SMT pads are intentional per manufacturers footprint.  SMT pad copper may be pulled back 5-8Mil from holes as needed for processing." at 4711,1557 h59
  text "TO MEET OR EXCEED THE REQUIREMENTS OF:" at 8997.6,1482.42 h60
  text "X" at 8635.1,1353.79 h60
  text "ANSI IPC-A-600F CLASS ->" at 8763.1,1353.79 h60
  text "X" at 10411.1,1353.79 h60
  text "2" at 10521.1,1353.79 h60
  text "1" at 10206.1,1352.3 h60
  text "3" at 10875.1,1352.3 h60
  text "X" at 9447.1,1206.11 h60
  text "RoHS" at 9575.1,1206.11 h60
  text "OTHER" at 10219.5,1206.11 h60
  text "PER ORDER" at 10616.56,1206.11 h60
  text "ALL BOARDS MUST MEET OR EXCEED UL94-V0 REQUIREMENTS." at 8300.14,1052.28 h60
  text "PCB MUST BEAR THE UL94V-0 UL REGISTERED MATERIAL ID NUMBER" at 8300.14,936.22 h60
  text "ADDITIONAL REQUIREMENTS:" at 8272.6,766.79 h60
  text "REQUIRED" at 10054.6,645.34 h60
  text "BARE BOARD ELEC. TEST:" at 8287.36,642.48 h60
  text "NONE" at 9593.1,642.48 h60
  text "X" at 10529.14,642.71 h60
  text "PER ORDER" at 10646.6,642.48 h60
  text "OUTER LAYERS 6 MIL WIDE, 6 MIL SPACE / TRACES REQUIRE 100 OHM DIFFERENTIAL IMPEDANCE" at 8524.21,340.78 h60
  text "X" at 8340.1,333.79 h60
  text "X" at 8350.1,163.79 h60
  text "INNER LAYERS 5 MIL WIDE, 7 MIL SPACE / TRACES REQUIRE 100 OHM DIFFERENTIAL IMPEDANCE" at 8494.21,155.78 h60
  text "X" at 8350.1,-1.21 h60
  text "OUTER LAYERS 6.1 MIL WIDE, 6 MIL SPACE / TRACES REQUIRE 90 OHM DIFFERENTIAL IMPEDANCE" at 8506.53,-30.07 h60
  text ".Layer_Name" at -2483.86,-1945.78 h60
M11 Gerber Information:
  lines w10: -3352.86,-2017.45 3247.14,-2017.45 ; -3352.86,-1814.12 3249.14,-1814.12 ; -3352.86,-1610.79 -3352.86,-2220.79 652.14,-2220.79 3249.14,-2220.79 3249.14,-1610.79 -3352.36,-1610.79 -3352.36,-2220.79 -1776.86,-2220.79 ; -887.86,-2220.79 -887.86,-1610.79 ; 379.14,-1814.12 379.14,-1610.79 ; 1219.14,-1814.12 1219.14,-1610.79 ; 1841.14,-2227.29 1841.14,-2024.45
  text "ALL ARTWORK VIEWED FROM TOP SIDE" at -3289.36,-1742.95 h60
  text "BOARD #:" at -812.86,-1742.95 h60
  text ".PRJ_Number" at -267.36,-1742.95 h60
  text "REV:" at 577.14,-1742.95 h60
  text ".PCB_Rev" at 868.64,-1742.95 h60
  text "SVN REV:" at 1415.14,-1742.95 h60
  text ".VersionControl_RevNumber" at 1921.14,-1742.95 h60
  text "LAYER NAME =" at -3289.36,-1945.78 h60
  text "TID #:" at -812.86,-1946.29 h60
  text ".TID" at -267.36,-1946.29 h60
  text "PLOT NAME =" at -3289.36,-2151.62 h60
  text ".plot_File_Name" at -2483.86,-2151.62 h60
  text "GENERATED    :" at -810.86,-2151.62 h60
  text ".Print_Date" at 58.64,-2151.62 h60
  text ".Print_Time" at 787.64,-2151.62 h60
  text "TEXAS INSTRUMENTS" at 2052.14,-2151.62 h60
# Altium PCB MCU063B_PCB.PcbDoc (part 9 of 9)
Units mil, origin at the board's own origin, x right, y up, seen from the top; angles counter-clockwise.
Board outline 4165.01 x 2371.03 mil, 10 copper layers (Top Layer, Internal Plane 2, Signal Layer 3, Signal Layer 4, Internal Plane 5, Internal Plane 6, Signal Layer 7, Signal Layer 8, Internal Plane 9, Bottom), stack 59.9 mil thick; 440 components, 394 nets, 1760 pads, 1251 vias.

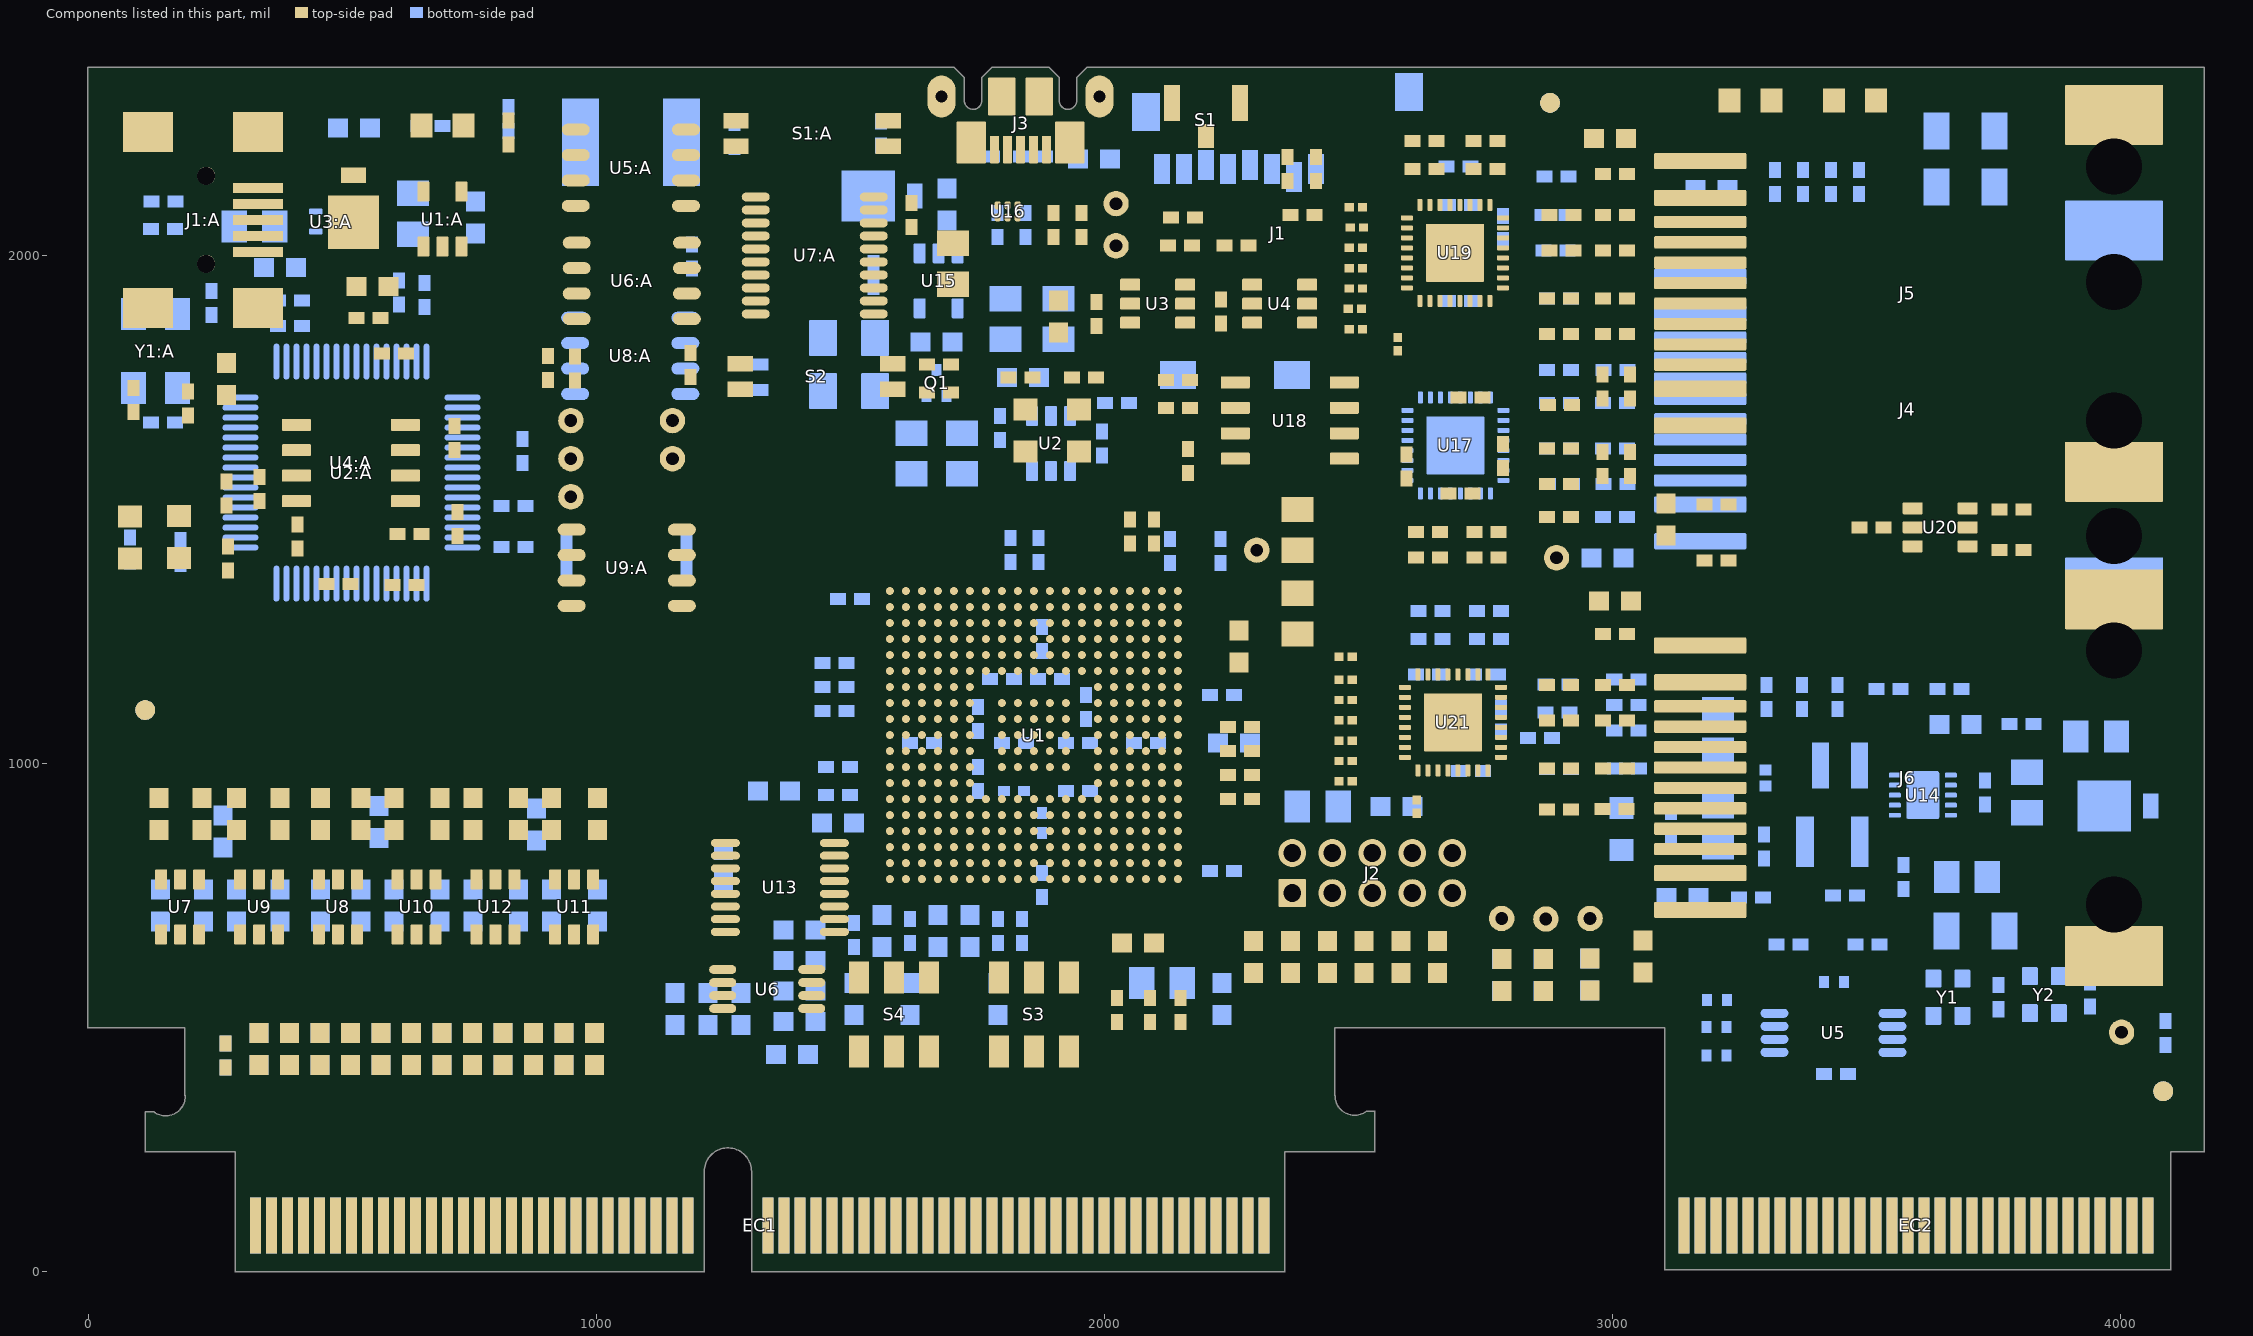
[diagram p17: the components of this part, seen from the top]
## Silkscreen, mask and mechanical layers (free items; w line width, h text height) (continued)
M12 Stackup:
  drawing of 607 lines, arcs and shapes, not listed
  text "Layer" at 3492.28,6369.4 h60
  text "Name" at 3902.19,6369.4 h60
  text "Material" at 4941.9,6369.4 h60
  text "Thickness" at 5801.66,6369.4 h60
  text "Constant" at 6451.5,6369.4 h60
  text "Board Layer Stack" at 7021.36,6369.4 h60
  text "Top Overlay" at 3902.19,6249.4 h60
  text "Top Solder" at 3902.19,6129.4 h60
  text "Solder Resist" at 4941.9,6129.4 h60
  text "0.80mil" at 5801.66,6129.4 h60
  text "3.6" at 6451.5,6129.4 h60
  text "1" at 3492.28,6009.4 h60
  text "Top Layer" at 3902.19,6009.4 h60
  text "1.45mil" at 5801.66,6009.4 h60
  text "Dielectric 1" at 3902.19,5889.4 h60
  text "FR-4" at 4941.9,5889.4 h60
  text "4.86mil" at 5801.66,5889.4 h60
  text "3.7" at 6451.5,5889.4 h60
  text "2" at 3492.28,5769.4 h60
  text "Internal Plane 2" at 3902.19,5769.4 h60
  text "1.20mil" at 5801.66,5769.4 h60
  text "Dielectric 2" at 3902.19,5649.4 h60
  text "FR-4" at 4941.9,5649.4 h60
  text "5.00mil" at 5801.66,5649.4 h60
  text "3.7" at 6451.5,5649.4 h60
  text "3" at 3492.28,5529.4 h60
  text "Signal Layer 3" at 3902.19,5529.4 h60
  text "1.20mil" at 5801.66,5529.4 h60
  text "Dielectric 3" at 3902.19,5409.4 h60
  text "FR-4" at 4941.9,5409.4 h60
  text "6.28mil" at 5801.66,5409.4 h60
  text "4.1" at 6451.5,5409.4 h60
  text "4" at 3492.28,5289.4 h60
  text "Signal Layer 4" at 3902.19,5289.4 h60
  text "1.20mil" at 5801.66,5289.4 h60
  text "Dielectric 4" at 3902.19,5169.4 h60
  text "FR-4" at 4941.9,5169.4 h60
  text "5.00mil" at 5801.66,5169.4 h60
  text "3.7" at 6451.5,5169.4 h60
  text "5" at 3492.28,5049.4 h60
  text "Internal Plane 5" at 3902.19,5049.4 h60
  text "1.20mil" at 5801.66,5049.4 h60
  text "Dielectric 5" at 3902.19,4929.4 h60
  text "FR-4" at 4941.9,4929.4 h60
  text "5.12mil" at 5801.66,4929.4 h60
  text "3.7" at 6451.5,4929.4 h60
  text "6" at 3492.28,4809.4 h60
  text "Internal Plane 6" at 3902.19,4809.4 h60
  text "1.20mil" at 5801.66,4809.4 h60
  text "Dielectric 6" at 3902.19,4689.4 h60
  text "FR-4" at 4941.9,4689.4 h60
  text "5.00mil" at 5801.66,4689.4 h60
  text "3.7" at 6451.5,4689.4 h60
  text "7" at 3492.28,4569.4 h60
  text "Signal Layer 7" at 3902.19,4569.4 h60
  text "1.20mil" at 5801.66,4569.4 h60
  text "Dielectric 7" at 3902.19,4449.4 h60
  text "FR-4" at 4941.9,4449.4 h60
  text "6.28mil" at 5801.66,4449.4 h60
  text "4.1" at 6451.5,4449.4 h60
  text "8" at 3492.28,4329.4 h60
  text "Signal Layer 8" at 3902.19,4329.4 h60
  text "1.20mil" at 5801.66,4329.4 h60
  text "Dielectric 8" at 3902.19,4209.4 h60
  text "FR-4" at 4941.9,4209.4 h60
  text "5.00mil" at 5801.66,4209.4 h60
  text "3.7" at 6451.5,4209.4 h60
  text "9" at 3492.28,4089.4 h60
  text "Internal Plane 9" at 3902.19,4089.4 h60
  text "1.20mil" at 5801.66,4089.4 h60
  text "Dielectric 9" at 3902.19,3969.4 h60
  text "FR-4" at 4941.9,3969.4 h60
  text "4.86mil" at 5801.66,3969.4 h60
  text "3.7" at 6451.5,3969.4 h60
  text "10" at 3492.28,3849.4 h60
  text "Bottom" at 3902.19,3849.4 h60
  text "1.45mil" at 5801.66,3849.4 h60
  text "Bottom Solder" at 3902.19,3729.4 h60
  text "Solder Resist" at 4941.9,3729.4 h60
  text "0.80mil" at 5801.66,3729.4 h60
  text "3.6" at 6451.5,3729.4 h60
  text "Bottom Overlay" at 3902.19,3609.4 h60
  text ".Layer_Name" at -2483.86,-1945.78 h60
M13 Component Bodies Top:
  text ".Layer_Name" at -2483.86,-1945.78 h60
M14 Component Bodies Bottom:
  text ".Layer_Name" at -2483.86,-1945.78 h60
M15 Courtyards Top:
  text ".Layer_Name" at -2483.86,-1945.78 h60
M16 Courtyards Bottom:
  text ".Layer_Name" at -2483.86,-1945.78 h60
Drill Drawing:
  circle w10: c-3052.38,4878.27 r33.33
  lines w10: -3085.71,4094.94 -3052.38,4111.61 -3019.04,4094.94 -3035.71,4128.27 -3019.04,4161.61 -3052.38,4144.94 -3085.71,4161.61 -3069.04,4128.27 -3085.71,4094.94 ; -3085.71,4244.94 -3085.71,4261.61 -3069.04,4278.27 -3085.71,4294.94 -3085.71,4311.61 -3069.04,4311.61 -3052.38,4294.94 -3035.71,4311.61 -3019.04,4311.61 -3019.04,4294.94 -3035.71,4278.27 -3019.04,4261.61 -3019.04,4244.94 -3035.71,4244.94 -3052.38,4261.61 -3069.04,4244.94 -3085.71,4244.94 ; -3085.71,4411.61 -3069.04,4411.61 -3052.38,4394.94 -3035.71,4411.61 -3019.04,4411.61 -3035.71,4428.27 -3019.04,4444.94 -3035.71,4444.94 -3052.38,4461.61 -3069.04,4444.94 -3085.71,4444.94 -3069.04,4428.27 -3085.71,4411.61 ; -3085.71,4611.61 -3019.04,4611.61 -3052.38,4544.94 -3085.71,4611.61 ; -3085.71,4694.94 -3019.04,4694.94 -3019.04,4761.61 -3085.71,4761.61 -3085.71,4694.94 ; -3085.71,5028.27 -3052.38,4994.94 -3019.04,5028.27 -3052.38,5061.61 -3085.71,5028.27
  lines w15: -3145.5,4049.94 2412.96,4049.94 ; -3145.5,5099.94 2412.96,5099.94 ; -2594.62,3899.94 -2594.62,5249.94 ; -1454.96,3899.94 -1454.96,5249.94 ; -121.35,3899.94 -121.35,5249.94 ; 1212.26,3899.94 1212.26,5249.94 ; 1718.13,3899.94 1718.13,5249.94 ; -3145.5,3899.94 2412.96,3899.94 2412.96,5249.94 -3145.5,5249.94 -3145.5,3899.94
  text "Symbol" at -3055.5,5144.94 h72
  text "Hole Size" at -2549.62,5144.94 h72
  text "Hole Tolerance (+)" at -1409.96,5144.94 h72
  text "Hole Tolerance (-)" at -76.35,5144.94 h72
  text "Plated" at 1257.26,5144.94 h72
  text "Count" at 1763.13,5144.94 h72
  text "7.87mil (0.200mm)" at -2549.62,4994.94 h60
  text "PTH" at 1257.26,4994.94 h60
  text "20" at 1763.13,4994.94 h60
  text "8.00mil (0.203mm)" at -2549.62,4844.94 h60
  text "PTH" at 1257.26,4844.94 h60
  text "1231" at 1763.13,4844.94 h60
  text "23.62mil (0.600mm)" at -2549.62,4694.94 h60
  text "PTH" at 1257.26,4694.94 h60
  text "2" at 1763.13,4694.94 h60
  text "25.00mil (0.635mm)" at -2549.62,4544.94 h60
  text "PTH" at 1257.26,4544.94 h60
  text "13" at 1763.13,4544.94 h60
  text "35.04mil (0.890mm)" at -2549.62,4394.94 h60
  text "PTH" at 1257.26,4394.94 h60
  text "10" at 1763.13,4394.94 h60
  text "35.43mil (0.900mm)" at -2549.62,4244.94 h60
  text "NPTH" at 1257.26,4244.94 h60
  text "2" at 1763.13,4244.94 h60
  text "110.24mil (2.800mm)" at -2549.62,4094.94 h60
  text "1.97mil (0.050mm)" at -1409.96,4094.94 h60
  text "1.18mil (0.030mm)" at -76.35,4094.94 h60
  text "NPTH" at 1257.26,4094.94 h60
  text "6" at 1763.13,4094.94 h60
  text "1284 Total" at 1763.13,3944.94 h60
  text "Slot definitions :" at -3055.5,3799.97 h60
  text "Routed Path Length" at -2022.81,3799.97 h60
  text "= Calculated from tool start centre position to tool end centre position." at -920.14,3799.97 h60
  text "Hole Length" at -2022.81,3699.99 h60
  text "= Routed Path Length + Tool Size = Slot length as defined in the PCB layout" at -1330.01,3699.99 h60
  text ".Layer_Name" at -2483.86,-1945.78 h60
M17 Embedded Cavity:
  text ".Layer_Name" at -2483.86,-1945.78 h60
M18 Embedded Assembly:
  text ".Layer_Name" at -2483.86,-1945.78 h60
M19 Embedded Keepout:
  text ".Layer_Name" at -2483.86,-1945.78 h60

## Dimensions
-3060.86,-1487.29 to -2060.86,-1487.29 on M2 Board Dimensions
0.01,480 to 0,2370 on M2 Board Dimensions
4098.57,4 to 4163.98,236.1 on M2 Board Dimensions
4163.98,236.1 to 4163.98,2370 on M2 Board Dimensions
4098.57,4 to 3103.29,4 on M2 Board Dimensions
2452.98,480 to 3103.29,480 on M2 Board Dimensions
1306.09,0 to 2354.98,0 on M2 Board Dimensions
190.98,347 to 0,480 on M2 Board Dimensions
112.98,314 to 289.98,0 on M2 Board Dimensions
1212.09,0 to 289.98,0 on M2 Board Dimensions
1212.09,0 to 1306.09,0 on M2 Board Dimensions
2531.98,236 to 2354.98,0 on M2 Board Dimensions
2492.48,346.12 to 2604,145 on M2 Board Dimensions
1259.09,197 to 1165,250 on M2 Board Dimensions
152.53,345.09 to 32,202 on M2 Board Dimensions
289.98,236 to 289.98,0 on M2 Board Dimensions
1259.09,244 to 1306.09,0 on M2 Board Dimensions
2354.98,236 to 2354.98,0 on M2 Board Dimensions
3103.29,480 to 3103.29,4 on M2 Board Dimensions
4098.57,236.1 to 4098.57,4 on M2 Board Dimensions
0,2369.99 to 1703.62,2369.99 on M2 Board Dimensions
1723.78,2350.31 to 1704.09,2370 on M2 Board Dimensions
1910.79,2350.31 to 1946.22,2350.31 on M2 Board Dimensions
1928,2287 to 2041.69,2370 on M2 Board Dimensions
1741.78,2304.39 to 1381,2599 on M2 Board Dimensions
0,2369.99 to 4163.98,2370 on M2 Board Dimensions
1966.3,2370 to 4163.98,2370 on M2 Board Dimensions
4163.98,2370 to 4098.57,4 on M2 Board Dimensions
